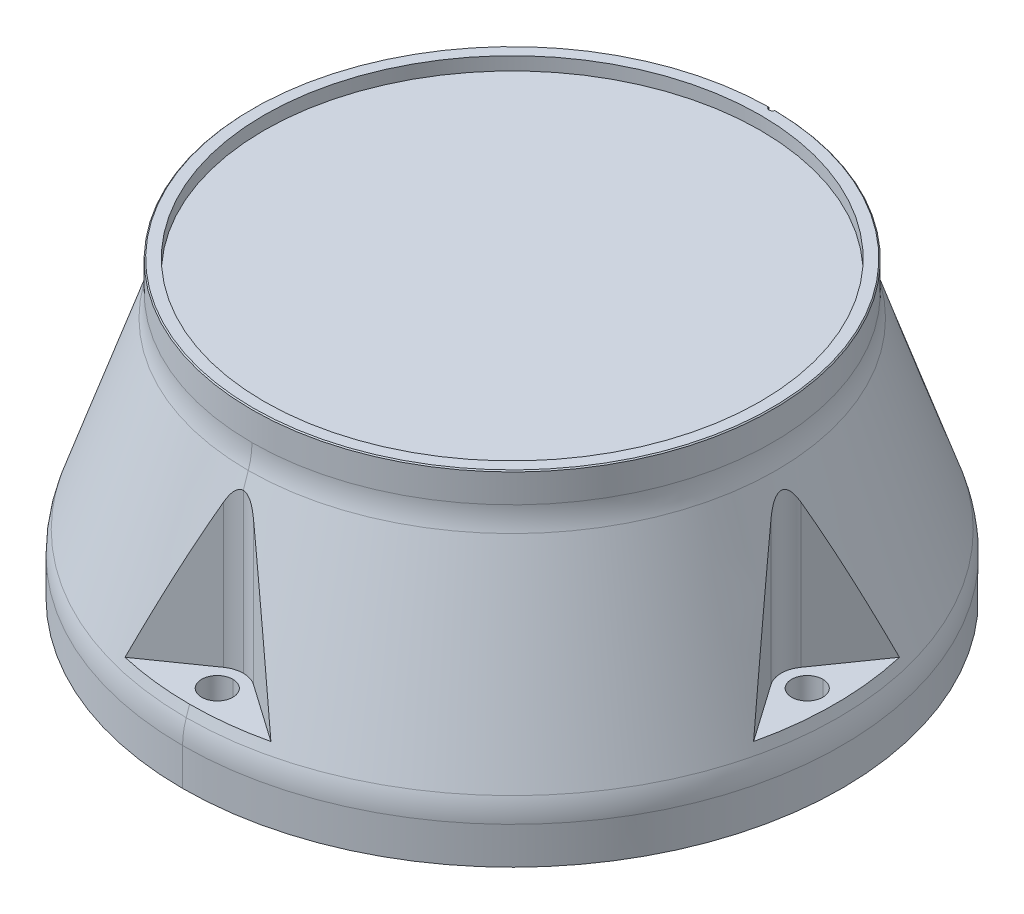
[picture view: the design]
ISO-10303-21;
HEADER;
FILE_DESCRIPTION(('STEP AP214'),'2;1');
FILE_NAME('part.step','',(''),(''),'','','');
FILE_SCHEMA(('AUTOMOTIVE_DESIGN { 1 0 10303 214 1 1 1 1 }'));
ENDSEC;
DATA;
#1=APPLICATION_CONTEXT('core data for automotive mechanical design processes');
#2=APPLICATION_PROTOCOL_DEFINITION('international standard','automotive_design',2000,#1);
#3=PRODUCT_CONTEXT('',#1,'mechanical');
#4=PRODUCT('Part','Part','',(#3));
#5=PRODUCT_RELATED_PRODUCT_CATEGORY('part','',(#4));
#6=PRODUCT_DEFINITION_FORMATION('','',#4);
#7=PRODUCT_DEFINITION_CONTEXT('part definition',#1,'design');
#8=PRODUCT_DEFINITION('design','',#6,#7);
#9=PRODUCT_DEFINITION_SHAPE('','',#8);
#10=(LENGTH_UNIT() NAMED_UNIT(*) SI_UNIT(.MILLI.,.METRE.));
#11=(NAMED_UNIT(*) PLANE_ANGLE_UNIT() SI_UNIT($,.RADIAN.));
#12=(NAMED_UNIT(*) SI_UNIT($,.STERADIAN.) SOLID_ANGLE_UNIT());
#13=UNCERTAINTY_MEASURE_WITH_UNIT(LENGTH_MEASURE(1.E-05),#10,'distance_accuracy_value','');
#14=(GEOMETRIC_REPRESENTATION_CONTEXT(3) GLOBAL_UNCERTAINTY_ASSIGNED_CONTEXT((#13)) GLOBAL_UNIT_ASSIGNED_CONTEXT((#10,
#11,#12)) REPRESENTATION_CONTEXT('',''));
#15=CARTESIAN_POINT('',(0.,0.,0.));
#16=DIRECTION('',(0.,0.,1.));
#17=DIRECTION('',(1.,0.,0.));
#18=AXIS2_PLACEMENT_3D('',#15,#16,#17);
#19=CARTESIAN_POINT('',(0.,82.,-75.));
#20=DIRECTION('',(0.,1.,0.));
#21=DIRECTION('',(0.,0.,1.));
#22=AXIS2_PLACEMENT_3D('',#19,#20,#21);
#23=CYLINDRICAL_SURFACE('',#22,1.);
#24=CARTESIAN_POINT('',(0.,84.8,-75.));
#25=DIRECTION('',(0.,1.,0.));
#26=DIRECTION('',(0.,0.,1.));
#27=AXIS2_PLACEMENT_3D('',#24,#25,#26);
#28=CIRCLE('',#27,1.);
#29=CARTESIAN_POINT('',(0.952397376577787,84.8000000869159,-74.6939519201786));
#30=VERTEX_POINT('',#29);
#31=CARTESIAN_POINT('',(0.,84.8,-74.));
#32=VERTEX_POINT('',#31);
#33=EDGE_CURVE('E2148',#30,#32,#28,.F.);
#34=ORIENTED_EDGE('',*,*,#33,.F.);
#35=CARTESIAN_POINT('',(0.952044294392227,84.7999875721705,-74.6940397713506));
#36=CARTESIAN_POINT('',(0.956875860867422,84.7849145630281,-74.7090742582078));
#37=CARTESIAN_POINT('',(0.961331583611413,84.769776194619,-74.7241610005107));
#38=CARTESIAN_POINT('',(0.967342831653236,84.7474166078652,-74.7464208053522));
#39=CARTESIAN_POINT('',(0.969186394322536,84.7402403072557,-74.753561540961));
#40=CARTESIAN_POINT('',(0.973275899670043,84.7235551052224,-74.7701550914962));
#41=CARTESIAN_POINT('',(0.97546092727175,84.7140372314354,-74.7796139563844));
#42=CARTESIAN_POINT('',(0.979838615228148,84.6936336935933,-74.7999035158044));
#43=CARTESIAN_POINT('',(0.981988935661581,84.6827443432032,-74.81073963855));
#44=CARTESIAN_POINT('',(0.986169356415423,84.6595957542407,-74.8337961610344));
#45=CARTESIAN_POINT('',(0.988151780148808,84.6473334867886,-74.8460221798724));
#46=CARTESIAN_POINT('',(0.991851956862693,84.6214387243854,-74.8718660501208));
#47=CARTESIAN_POINT('',(0.993516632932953,84.6078038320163,-74.8854891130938));
#48=CARTESIAN_POINT('',(0.996419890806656,84.579163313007,-74.9141250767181));
#49=CARTESIAN_POINT('',(0.997599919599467,84.5641557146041,-74.9291419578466));
#50=CARTESIAN_POINT('',(0.999356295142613,84.532769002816,-74.9605506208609));
#51=CARTESIAN_POINT('',(0.999868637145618,84.5163882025,-74.9769443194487));
#52=CARTESIAN_POINT('',(0.999977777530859,84.5000000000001,-74.9933333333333));
#53=B_SPLINE_CURVE_WITH_KNOTS('',3,(#35,#36,#37,#38,#39,#40,#41,#42,#43,#44,#45,#46,#47,#48,#49,
#50,#51,#52),.UNSPECIFIED.,.F.,.F.,(4,2,2,2,2,2,2,2,4),(0.,0.065484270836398,0.0963536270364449,
0.137136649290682,0.183668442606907,0.235949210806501,0.293979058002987,0.357758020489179,
0.427286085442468),.UNSPECIFIED.);
#54=CARTESIAN_POINT('',(0.999977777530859,84.5,-74.9933333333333));
#55=VERTEX_POINT('',#54);
#56=EDGE_CURVE('E766',#30,#55,#53,.T.);
#57=ORIENTED_EDGE('',*,*,#56,.T.);
#58=DIRECTION('',(0.,-1.,0.));
#59=VECTOR('',#58,1.);
#60=CARTESIAN_POINT('',(0.999977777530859,83.5,-74.9933333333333));
#61=LINE('',#60,#59);
#62=CARTESIAN_POINT('',(0.999977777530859,82.,-74.9933333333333));
#63=VERTEX_POINT('',#62);
#64=EDGE_CURVE('E688',#55,#63,#61,.T.);
#65=ORIENTED_EDGE('',*,*,#64,.T.);
#66=CARTESIAN_POINT('',(0.,82.,-75.));
#67=DIRECTION('',(0.,1.,0.));
#68=DIRECTION('',(0.,0.,1.));
#69=AXIS2_PLACEMENT_3D('',#66,#67,#68);
#70=CIRCLE('',#69,1.);
#71=CARTESIAN_POINT('',(0.,82.,-74.));
#72=VERTEX_POINT('',#71);
#73=EDGE_CURVE('E569',#72,#63,#70,.T.);
#74=ORIENTED_EDGE('',*,*,#73,.F.);
#75=DIRECTION('',(0.,1.,0.));
#76=VECTOR('',#75,1.);
#77=CARTESIAN_POINT('',(0.,82.,-74.));
#78=LINE('',#77,#76);
#79=EDGE_CURVE('E743',#72,#32,#78,.T.);
#80=ORIENTED_EDGE('',*,*,#79,.T.);
#81=EDGE_LOOP('',(#34,#57,#65,#74,#80));
#82=FACE_BOUND('',#81,.T.);
#83=ADVANCED_FACE('F15',(#82),#23,.F.);
#84=CARTESIAN_POINT('',(0.,100.390423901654,0.));
#85=DIRECTION('',(0.,1.,0.));
#86=DIRECTION('',(0.,0.,1.));
#87=AXIS2_PLACEMENT_3D('',#84,#85,#86);
#88=CYLINDRICAL_SURFACE('',#87,71.5);
#89=DIRECTION('',(0.,1.,0.));
#90=VECTOR('',#89,1.);
#91=CARTESIAN_POINT('',(0.,100.390423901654,71.5));
#92=LINE('',#91,#90);
#93=CARTESIAN_POINT('',(0.,81.,71.5));
#94=VERTEX_POINT('',#93);
#95=CARTESIAN_POINT('',(0.,81.5,71.5));
#96=VERTEX_POINT('',#95);
#97=EDGE_CURVE('E576',#94,#96,#92,.T.);
#98=ORIENTED_EDGE('',*,*,#97,.T.);
#99=ORIENTED_EDGE('',*,*,#97,.F.);
#100=CARTESIAN_POINT('',(0.,81.,0.));
#101=DIRECTION('',(0.,1.,0.));
#102=DIRECTION('',(0.,0.,1.));
#103=AXIS2_PLACEMENT_3D('',#100,#101,#102);
#104=CIRCLE('',#103,71.5);
#105=CARTESIAN_POINT('',(0.,81.,-71.5));
#106=VERTEX_POINT('',#105);
#107=EDGE_CURVE('E563',#106,#94,#104,.T.);
#108=ORIENTED_EDGE('',*,*,#107,.F.);
#109=DIRECTION('',(0.,1.,0.));
#110=VECTOR('',#109,1.);
#111=CARTESIAN_POINT('',(0.,100.390423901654,-71.5));
#112=LINE('',#111,#110);
#113=CARTESIAN_POINT('',(0.,84.8,-71.5));
#114=VERTEX_POINT('',#113);
#115=EDGE_CURVE('E689',#106,#114,#112,.T.);
#116=ORIENTED_EDGE('',*,*,#115,.T.);
#117=CARTESIAN_POINT('',(0.,84.8,0.));
#118=DIRECTION('',(0.,1.,0.));
#119=DIRECTION('',(0.,0.,1.));
#120=AXIS2_PLACEMENT_3D('',#117,#118,#119);
#121=CIRCLE('',#120,71.5);
#122=CARTESIAN_POINT('',(0.,84.8,71.5));
#123=VERTEX_POINT('',#122);
#124=EDGE_CURVE('E37',#123,#114,#121,.F.);
#125=ORIENTED_EDGE('',*,*,#124,.F.);
#126=DIRECTION('',(0.,1.,0.));
#127=VECTOR('',#126,1.);
#128=CARTESIAN_POINT('',(0.,100.390423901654,71.5));
#129=LINE('',#128,#127);
#130=CARTESIAN_POINT('',(-8.28313419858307E-13,84.5000000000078,71.5));
#131=VERTEX_POINT('',#130);
#132=EDGE_CURVE('E1265',#131,#123,#129,.T.);
#133=ORIENTED_EDGE('',*,*,#132,.F.);
#134=ORIENTED_EDGE('',*,*,#132,.T.);
#135=CARTESIAN_POINT('',(0.,84.8,0.));
#136=DIRECTION('',(0.,1.,0.));
#137=DIRECTION('',(0.,0.,1.));
#138=AXIS2_PLACEMENT_3D('',#135,#136,#137);
#139=CIRCLE('',#138,71.5);
#140=EDGE_CURVE('E2149',#114,#123,#139,.F.);
#141=ORIENTED_EDGE('',*,*,#140,.F.);
#142=ORIENTED_EDGE('',*,*,#115,.F.);
#143=CARTESIAN_POINT('',(0.,81.,0.));
#144=DIRECTION('',(0.,1.,0.));
#145=DIRECTION('',(0.,0.,1.));
#146=AXIS2_PLACEMENT_3D('',#143,#144,#145);
#147=CIRCLE('',#146,71.5);
#148=EDGE_CURVE('E551',#94,#106,#147,.T.);
#149=ORIENTED_EDGE('',*,*,#148,.F.);
#150=EDGE_LOOP('',(#98,#99,#108,#116,#125,#133,#134,#141,#142,#149));
#151=FACE_BOUND('',#150,.T.);
#152=ADVANCED_FACE('F1210',(#151),#88,.F.);
#153=CARTESIAN_POINT('',(0.,82.,-75.));
#154=DIRECTION('',(0.,1.,0.));
#155=DIRECTION('',(0.,0.,1.));
#156=AXIS2_PLACEMENT_3D('',#153,#154,#155);
#157=CYLINDRICAL_SURFACE('',#156,1.);
#158=CARTESIAN_POINT('',(0.,84.8,-75.));
#159=DIRECTION('',(0.,1.,0.));
#160=DIRECTION('',(0.,0.,1.));
#161=AXIS2_PLACEMENT_3D('',#158,#159,#160);
#162=CIRCLE('',#161,1.);
#163=CARTESIAN_POINT('',(-0.952291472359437,84.8000001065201,-74.693618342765));
#164=VERTEX_POINT('',#163);
#165=EDGE_CURVE('E537',#32,#164,#162,.F.);
#166=ORIENTED_EDGE('',*,*,#165,.F.);
#167=ORIENTED_EDGE('',*,*,#79,.F.);
#168=CARTESIAN_POINT('',(0.,82.,-75.));
#169=DIRECTION('',(0.,1.,0.));
#170=DIRECTION('',(0.,0.,1.));
#171=AXIS2_PLACEMENT_3D('',#168,#169,#170);
#172=CIRCLE('',#171,1.);
#173=CARTESIAN_POINT('',(-0.999977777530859,82.,-74.9933333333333));
#174=VERTEX_POINT('',#173);
#175=EDGE_CURVE('E571',#174,#72,#172,.T.);
#176=ORIENTED_EDGE('',*,*,#175,.F.);
#177=DIRECTION('',(0.,1.,0.));
#178=VECTOR('',#177,1.);
#179=CARTESIAN_POINT('',(-0.999977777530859,83.5,-74.9933333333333));
#180=LINE('',#179,#178);
#181=CARTESIAN_POINT('',(-0.999977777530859,84.5,-74.9933333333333));
#182=VERTEX_POINT('',#181);
#183=EDGE_CURVE('E956',#174,#182,#180,.T.);
#184=ORIENTED_EDGE('',*,*,#183,.T.);
#185=CARTESIAN_POINT('',(-0.999977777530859,84.5000000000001,-74.9933333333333));
#186=CARTESIAN_POINT('',(-0.999882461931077,84.514311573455,-74.979021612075));
#187=CARTESIAN_POINT('',(-0.999479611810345,84.5286090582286,-74.9646977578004));
#188=CARTESIAN_POINT('',(-0.998080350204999,84.5566851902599,-74.9365376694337));
#189=CARTESIAN_POINT('',(-0.997104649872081,84.5704649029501,-74.9227014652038));
#190=CARTESIAN_POINT('',(-0.994619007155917,84.5975055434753,-74.8955373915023));
#191=CARTESIAN_POINT('',(-0.993129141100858,84.6107676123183,-74.8822088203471));
#192=CARTESIAN_POINT('',(-0.989673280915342,84.6367728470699,-74.8560760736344));
#193=CARTESIAN_POINT('',(-0.987726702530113,84.649517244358,-74.8432705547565));
#194=CARTESIAN_POINT('',(-0.983413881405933,84.6744870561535,-74.8181957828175));
#195=CARTESIAN_POINT('',(-0.981066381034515,84.6867138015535,-74.8059246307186));
#196=CARTESIAN_POINT('',(-0.976006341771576,84.7106481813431,-74.7819266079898));
#197=CARTESIAN_POINT('',(-0.973311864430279,84.7223572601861,-74.7701973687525));
#198=CARTESIAN_POINT('',(-0.967610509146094,84.7452562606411,-74.7472877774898));
#199=CARTESIAN_POINT('',(-0.96462100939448,84.7564477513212,-74.7361046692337));
#200=CARTESIAN_POINT('',(-0.958379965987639,84.7783111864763,-74.7142886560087));
#201=CARTESIAN_POINT('',(-0.955145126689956,84.7889848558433,-74.7036526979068));
#202=CARTESIAN_POINT('',(-0.951727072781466,84.7996373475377,-74.6930544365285));
#203=B_SPLINE_CURVE_WITH_KNOTS('',3,(#185,#186,#187,#188,#189,#190,#191,#192,#193,#194,#195,
#196,#197,#198,#199,#200,#201,#202),.UNSPECIFIED.,.F.,.F.,(4,2,2,2,2,2,2,2,4),(0.,
0.0607175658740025,0.119364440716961,0.175940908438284,0.230447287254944,0.282883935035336,
0.333251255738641,0.381549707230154,0.427779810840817),.UNSPECIFIED.);
#204=EDGE_CURVE('E1529',#182,#164,#203,.T.);
#205=ORIENTED_EDGE('',*,*,#204,.T.);
#206=EDGE_LOOP('',(#166,#167,#176,#184,#205));
#207=FACE_BOUND('',#206,.T.);
#208=ADVANCED_FACE('F1055',(#207),#157,.F.);
#209=CARTESIAN_POINT('',(0.,85.,0.));
#210=DIRECTION('',(0.,-1.,0.));
#211=DIRECTION('',(0.,0.,-1.));
#212=AXIS2_PLACEMENT_3D('',#209,#210,#211);
#213=CONICAL_SURFACE('',#212,74.5,0.785398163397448);
#214=ORIENTED_EDGE('',*,*,#56,.F.);
#215=CARTESIAN_POINT('',(0.,84.8,0.));
#216=DIRECTION('',(0.,1.,0.));
#217=DIRECTION('',(0.,0.,1.));
#218=AXIS2_PLACEMENT_3D('',#215,#216,#217);
#219=CIRCLE('',#218,74.7);
#220=EDGE_CURVE('E10',#30,#164,#219,.F.);
#221=ORIENTED_EDGE('',*,*,#220,.T.);
#222=ORIENTED_EDGE('',*,*,#204,.F.);
#223=CARTESIAN_POINT('',(0.,84.5,0.));
#224=DIRECTION('',(0.,-1.,0.));
#225=DIRECTION('',(0.,0.,1.));
#226=AXIS2_PLACEMENT_3D('',#223,#224,#225);
#227=CIRCLE('',#226,75.);
#228=EDGE_CURVE('E731',#55,#182,#227,.T.);
#229=ORIENTED_EDGE('',*,*,#228,.F.);
#230=EDGE_LOOP('',(#214,#221,#222,#229));
#231=FACE_BOUND('',#230,.T.);
#232=ADVANCED_FACE('F1251',(#231),#213,.T.);
#233=CARTESIAN_POINT('',(63.6396103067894,2.5,-42.4264068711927));
#234=DIRECTION('',(0.,-1.,0.));
#235=DIRECTION('',(0.,0.,-1.));
#236=AXIS2_PLACEMENT_3D('',#233,#234,#235);
#237=CYLINDRICAL_SURFACE('',#236,1.24999999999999);
#238=CARTESIAN_POINT('',(63.6396103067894,10.,-42.4264068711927));
#239=DIRECTION('',(0.,-1.,0.));
#240=DIRECTION('',(0.,0.,-1.));
#241=AXIS2_PLACEMENT_3D('',#238,#239,#240);
#242=CIRCLE('',#241,1.24999999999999);
#243=CARTESIAN_POINT('',(63.6396103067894,10.,-41.1764068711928));
#244=VERTEX_POINT('',#243);
#245=CARTESIAN_POINT('',(63.6396103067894,10.,-43.6764068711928));
#246=VERTEX_POINT('',#245);
#247=EDGE_CURVE('E614',#244,#246,#242,.T.);
#248=ORIENTED_EDGE('',*,*,#247,.F.);
#249=DIRECTION('',(0.,-1.,0.));
#250=VECTOR('',#249,1.);
#251=CARTESIAN_POINT('',(63.6396103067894,2.5,-41.1764068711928));
#252=LINE('',#251,#250);
#253=CARTESIAN_POINT('',(63.6396103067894,2.5,-41.1764068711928));
#254=VERTEX_POINT('',#253);
#255=EDGE_CURVE('E24',#244,#254,#252,.T.);
#256=ORIENTED_EDGE('',*,*,#255,.T.);
#257=CARTESIAN_POINT('',(63.6396103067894,2.5,-42.4264068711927));
#258=DIRECTION('',(0.,-1.,0.));
#259=DIRECTION('',(0.,0.,-1.));
#260=AXIS2_PLACEMENT_3D('',#257,#258,#259);
#261=CIRCLE('',#260,1.24999999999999);
#262=CARTESIAN_POINT('',(63.6396103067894,2.5,-43.6764068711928));
#263=VERTEX_POINT('',#262);
#264=EDGE_CURVE('E613',#254,#263,#261,.T.);
#265=ORIENTED_EDGE('',*,*,#264,.T.);
#266=DIRECTION('',(0.,-1.,0.));
#267=VECTOR('',#266,1.);
#268=CARTESIAN_POINT('',(63.6396103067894,2.5,-43.6764068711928));
#269=LINE('',#268,#267);
#270=EDGE_CURVE('E853',#246,#263,#269,.T.);
#271=ORIENTED_EDGE('',*,*,#270,.F.);
#272=EDGE_LOOP('',(#248,#256,#265,#271));
#273=FACE_BOUND('',#272,.T.);
#274=ADVANCED_FACE('F1550',(#273),#237,.F.);
#275=CARTESIAN_POINT('',(63.6396103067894,10.,-42.4264068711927));
#276=DIRECTION('',(0.,-1.,0.));
#277=DIRECTION('',(0.,0.,-1.));
#278=AXIS2_PLACEMENT_3D('',#275,#276,#277);
#279=CONICAL_SURFACE('',#278,1.24999999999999,1.02974425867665);
#280=DIRECTION('',(0.,-0.515038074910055,-0.857167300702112));
#281=VECTOR('',#280,1.);
#282=CARTESIAN_POINT('',(63.6396103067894,10.,-43.6764068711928));
#283=LINE('',#282,#281);
#284=CARTESIAN_POINT('',(63.6396103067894,10.7510757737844,-42.4264068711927));
#285=VERTEX_POINT('',#284);
#286=EDGE_CURVE('E801',#285,#246,#283,.T.);
#287=ORIENTED_EDGE('',*,*,#286,.F.);
#288=DIRECTION('',(0.,-0.515038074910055,0.857167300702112));
#289=VECTOR('',#288,1.);
#290=CARTESIAN_POINT('',(63.6396103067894,10.,-41.1764068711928));
#291=LINE('',#290,#289);
#292=EDGE_CURVE('E609',#285,#244,#291,.T.);
#293=ORIENTED_EDGE('',*,*,#292,.T.);
#294=ORIENTED_EDGE('',*,*,#247,.T.);
#295=EDGE_LOOP('',(#287,#293,#294));
#296=FACE_BOUND('',#295,.T.);
#297=ADVANCED_FACE('F1685',(#296),#279,.F.);
#298=CARTESIAN_POINT('',(42.4264068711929,2.5,-63.6396103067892));
#299=DIRECTION('',(0.,-1.,0.));
#300=DIRECTION('',(0.,0.,-1.));
#301=AXIS2_PLACEMENT_3D('',#298,#299,#300);
#302=CYLINDRICAL_SURFACE('',#301,1.24999999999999);
#303=CARTESIAN_POINT('',(42.4264068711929,10.,-63.6396103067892));
#304=DIRECTION('',(0.,-1.,0.));
#305=DIRECTION('',(0.,0.,-1.));
#306=AXIS2_PLACEMENT_3D('',#303,#304,#305);
#307=CIRCLE('',#306,1.24999999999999);
#308=CARTESIAN_POINT('',(42.4264068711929,10.,-62.3896103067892));
#309=VERTEX_POINT('',#308);
#310=CARTESIAN_POINT('',(42.4264068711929,10.,-64.8896103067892));
#311=VERTEX_POINT('',#310);
#312=EDGE_CURVE('E714',#309,#311,#307,.T.);
#313=ORIENTED_EDGE('',*,*,#312,.F.);
#314=DIRECTION('',(0.,-1.,0.));
#315=VECTOR('',#314,1.);
#316=CARTESIAN_POINT('',(42.4264068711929,2.5,-62.3896103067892));
#317=LINE('',#316,#315);
#318=CARTESIAN_POINT('',(42.4264068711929,2.5,-62.3896103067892));
#319=VERTEX_POINT('',#318);
#320=EDGE_CURVE('E625',#309,#319,#317,.T.);
#321=ORIENTED_EDGE('',*,*,#320,.T.);
#322=CARTESIAN_POINT('',(42.4264068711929,2.5,-63.6396103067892));
#323=DIRECTION('',(0.,-1.,0.));
#324=DIRECTION('',(0.,0.,-1.));
#325=AXIS2_PLACEMENT_3D('',#322,#323,#324);
#326=CIRCLE('',#325,1.24999999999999);
#327=CARTESIAN_POINT('',(42.4264068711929,2.5,-64.8896103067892));
#328=VERTEX_POINT('',#327);
#329=EDGE_CURVE('E621',#319,#328,#326,.T.);
#330=ORIENTED_EDGE('',*,*,#329,.T.);
#331=DIRECTION('',(0.,-1.,0.));
#332=VECTOR('',#331,1.);
#333=CARTESIAN_POINT('',(42.4264068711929,2.5,-64.8896103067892));
#334=LINE('',#333,#332);
#335=EDGE_CURVE('E747',#311,#328,#334,.T.);
#336=ORIENTED_EDGE('',*,*,#335,.F.);
#337=EDGE_LOOP('',(#313,#321,#330,#336));
#338=FACE_BOUND('',#337,.T.);
#339=ADVANCED_FACE('F1681',(#338),#302,.F.);
#340=CARTESIAN_POINT('',(42.4264068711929,10.,-63.6396103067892));
#341=DIRECTION('',(0.,-1.,0.));
#342=DIRECTION('',(0.,0.,-1.));
#343=AXIS2_PLACEMENT_3D('',#340,#341,#342);
#344=CONICAL_SURFACE('',#343,1.24999999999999,1.02974425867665);
#345=DIRECTION('',(0.,-0.515038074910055,-0.857167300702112));
#346=VECTOR('',#345,1.);
#347=CARTESIAN_POINT('',(42.4264068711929,10.,-64.8896103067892));
#348=LINE('',#347,#346);
#349=CARTESIAN_POINT('',(42.4264068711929,10.7510757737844,-63.6396103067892));
#350=VERTEX_POINT('',#349);
#351=EDGE_CURVE('E797',#350,#311,#348,.T.);
#352=ORIENTED_EDGE('',*,*,#351,.F.);
#353=DIRECTION('',(0.,-0.515038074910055,0.857167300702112));
#354=VECTOR('',#353,1.);
#355=CARTESIAN_POINT('',(42.4264068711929,10.,-62.3896103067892));
#356=LINE('',#355,#354);
#357=EDGE_CURVE('E626',#350,#309,#356,.T.);
#358=ORIENTED_EDGE('',*,*,#357,.T.);
#359=ORIENTED_EDGE('',*,*,#312,.T.);
#360=EDGE_LOOP('',(#352,#358,#359));
#361=FACE_BOUND('',#360,.T.);
#362=ADVANCED_FACE('F1684',(#361),#344,.F.);
#363=CARTESIAN_POINT('',(70.0035713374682,10.,41.7193000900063));
#364=DIRECTION('',(0.,-1.,0.));
#365=DIRECTION('',(0.,0.,-1.));
#366=AXIS2_PLACEMENT_3D('',#363,#364,#365);
#367=CYLINDRICAL_SURFACE('',#366,4.);
#368=CARTESIAN_POINT('',(70.0035713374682,10.,41.7193000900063));
#369=DIRECTION('',(0.,-1.,0.));
#370=DIRECTION('',(0.,0.,-1.));
#371=AXIS2_PLACEMENT_3D('',#368,#369,#370);
#372=CIRCLE('',#371,4.);
#373=CARTESIAN_POINT('',(70.0035713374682,10.,37.7193000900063));
#374=VERTEX_POINT('',#373);
#375=CARTESIAN_POINT('',(72.8319984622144,10.,38.8908729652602));
#376=VERTEX_POINT('',#375);
#377=EDGE_CURVE('E671',#374,#376,#372,.T.);
#378=ORIENTED_EDGE('',*,*,#377,.F.);
#379=DIRECTION('',(0.,-1.,0.));
#380=VECTOR('',#379,1.);
#381=CARTESIAN_POINT('',(70.0035713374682,10.,37.7193000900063));
#382=LINE('',#381,#380);
#383=CARTESIAN_POINT('',(70.0035713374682,0.,37.7193000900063));
#384=VERTEX_POINT('',#383);
#385=EDGE_CURVE('E718',#374,#384,#382,.T.);
#386=ORIENTED_EDGE('',*,*,#385,.T.);
#387=CARTESIAN_POINT('',(70.0035713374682,0.,41.7193000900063));
#388=DIRECTION('',(0.,-1.,0.));
#389=DIRECTION('',(0.,0.,-1.));
#390=AXIS2_PLACEMENT_3D('',#387,#388,#389);
#391=CIRCLE('',#390,4.);
#392=CARTESIAN_POINT('',(72.8319984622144,0.,38.8908729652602));
#393=VERTEX_POINT('',#392);
#394=EDGE_CURVE('E643',#384,#393,#391,.T.);
#395=ORIENTED_EDGE('',*,*,#394,.T.);
#396=DIRECTION('',(0.,-1.,0.));
#397=VECTOR('',#396,1.);
#398=CARTESIAN_POINT('',(72.8319984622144,10.,38.8908729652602));
#399=LINE('',#398,#397);
#400=EDGE_CURVE('E594',#376,#393,#399,.T.);
#401=ORIENTED_EDGE('',*,*,#400,.F.);
#402=EDGE_LOOP('',(#378,#386,#395,#401));
#403=FACE_BOUND('',#402,.T.);
#404=ADVANCED_FACE('F1192',(#403),#367,.F.);
#405=CARTESIAN_POINT('',(-42.4264068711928,10.,-70.7106781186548));
#406=DIRECTION('',(0.,-1.,0.));
#407=DIRECTION('',(0.,0.,-1.));
#408=AXIS2_PLACEMENT_3D('',#405,#406,#407);
#409=CYLINDRICAL_SURFACE('',#408,4.);
#410=CARTESIAN_POINT('',(-42.4264068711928,10.,-70.7106781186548));
#411=DIRECTION('',(0.,-1.,0.));
#412=DIRECTION('',(0.,0.,-1.));
#413=AXIS2_PLACEMENT_3D('',#410,#411,#412);
#414=CIRCLE('',#413,4.);
#415=CARTESIAN_POINT('',(-42.4264068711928,10.,-66.7106781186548));
#416=VERTEX_POINT('',#415);
#417=CARTESIAN_POINT('',(-42.4264068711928,10.,-74.7106781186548));
#418=VERTEX_POINT('',#417);
#419=EDGE_CURVE('E592',#416,#418,#414,.T.);
#420=ORIENTED_EDGE('',*,*,#419,.F.);
#421=DIRECTION('',(0.,-1.,0.));
#422=VECTOR('',#421,1.);
#423=CARTESIAN_POINT('',(-42.4264068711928,10.,-66.7106781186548));
#424=LINE('',#423,#422);
#425=CARTESIAN_POINT('',(-42.4264068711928,0.,-66.7106781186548));
#426=VERTEX_POINT('',#425);
#427=EDGE_CURVE('E639',#416,#426,#424,.T.);
#428=ORIENTED_EDGE('',*,*,#427,.T.);
#429=CARTESIAN_POINT('',(-42.4264068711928,0.,-70.7106781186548));
#430=DIRECTION('',(0.,-1.,0.));
#431=DIRECTION('',(0.,0.,-1.));
#432=AXIS2_PLACEMENT_3D('',#429,#430,#431);
#433=CIRCLE('',#432,4.);
#434=CARTESIAN_POINT('',(-42.4264068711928,0.,-74.7106781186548));
#435=VERTEX_POINT('',#434);
#436=EDGE_CURVE('E644',#426,#435,#433,.T.);
#437=ORIENTED_EDGE('',*,*,#436,.T.);
#438=DIRECTION('',(0.,-1.,0.));
#439=VECTOR('',#438,1.);
#440=CARTESIAN_POINT('',(-42.4264068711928,10.,-74.7106781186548));
#441=LINE('',#440,#439);
#442=EDGE_CURVE('E699',#418,#435,#441,.T.);
#443=ORIENTED_EDGE('',*,*,#442,.F.);
#444=EDGE_LOOP('',(#420,#428,#437,#443));
#445=FACE_BOUND('',#444,.T.);
#446=ADVANCED_FACE('F1015',(#445),#409,.F.);
#447=CARTESIAN_POINT('',(0.,10.7023274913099,0.));
#448=DIRECTION('',(0.,-1.,0.));
#449=DIRECTION('',(0.,0.,-1.));
#450=AXIS2_PLACEMENT_3D('',#447,#448,#449);
#451=TOROIDAL_SURFACE('',#450,75.,20.);
#452=CARTESIAN_POINT('',(0.,17.1231131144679,0.));
#453=DIRECTION('',(0.,1.,0.));
#454=DIRECTION('',(0.,0.,1.));
#455=AXIS2_PLACEMENT_3D('',#452,#453,#454);
#456=CIRCLE('',#455,93.941317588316);
#457=CARTESIAN_POINT('',(0.,17.1231131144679,93.941317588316));
#458=VERTEX_POINT('',#457);
#459=CARTESIAN_POINT('',(0.,17.1231131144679,-93.941317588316));
#460=VERTEX_POINT('',#459);
#461=EDGE_CURVE('E872',#458,#460,#456,.T.);
#462=ORIENTED_EDGE('',*,*,#461,.F.);
#463=CARTESIAN_POINT('',(0.,10.7023274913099,75.));
#464=DIRECTION('',(1.,0.,0.));
#465=DIRECTION('',(0.,0.,-1.));
#466=AXIS2_PLACEMENT_3D('',#463,#464,#465);
#467=CIRCLE('',#466,20.);
#468=CARTESIAN_POINT('',(0.,10.7023274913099,95.));
#469=VERTEX_POINT('',#468);
#470=EDGE_CURVE('E787',#458,#469,#467,.T.);
#471=ORIENTED_EDGE('',*,*,#470,.T.);
#472=CARTESIAN_POINT('',(0.,10.7023274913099,0.));
#473=DIRECTION('',(0.,-1.,0.));
#474=DIRECTION('',(0.,0.,-1.));
#475=AXIS2_PLACEMENT_3D('',#472,#473,#474);
#476=CIRCLE('',#475,95.);
#477=CARTESIAN_POINT('',(70.4307481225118,10.7023274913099,-63.7535075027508));
#478=VERTEX_POINT('',#477);
#479=EDGE_CURVE('E680',#478,#469,#476,.T.);
#480=ORIENTED_EDGE('',*,*,#479,.F.);
#481=CARTESIAN_POINT('',(70.4307481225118,10.7023274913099,-63.7535075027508));
#482=CARTESIAN_POINT('',(70.3838464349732,10.7913709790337,-63.805323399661));
#483=CARTESIAN_POINT('',(70.3347730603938,10.878460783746,-63.8585335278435));
#484=CARTESIAN_POINT('',(70.2327006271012,11.0481313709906,-63.9674861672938));
#485=CARTESIAN_POINT('',(70.1797157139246,11.1307266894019,-64.0232192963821));
#486=CARTESIAN_POINT('',(70.0699280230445,11.2914003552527,-64.1373025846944));
#487=CARTESIAN_POINT('',(70.0131264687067,11.3694801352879,-64.1956519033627));
#488=CARTESIAN_POINT('',(69.8958172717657,11.5211329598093,-64.3150335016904));
#489=CARTESIAN_POINT('',(69.8352995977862,11.5946926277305,-64.3760729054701));
#490=CARTESIAN_POINT('',(69.710759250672,11.7371972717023,-64.5007937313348));
#491=CARTESIAN_POINT('',(69.6467228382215,11.8061214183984,-64.5644852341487));
#492=CARTESIAN_POINT('',(69.5158720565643,11.9384832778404,-64.69396363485));
#493=CARTESIAN_POINT('',(69.4490683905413,12.001939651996,-64.7597422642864));
#494=CARTESIAN_POINT('',(69.3127888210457,12.1233849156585,-64.8934686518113));
#495=CARTESIAN_POINT('',(69.2433139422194,12.1813758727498,-64.9614155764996));
#496=CARTESIAN_POINT('',(69.1017846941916,12.2919135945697,-65.0995436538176));
#497=CARTESIAN_POINT('',(69.0297236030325,12.3444445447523,-65.1697305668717));
#498=CARTESIAN_POINT('',(68.8836485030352,12.4437126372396,-65.3118632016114));
#499=CARTESIAN_POINT('',(68.8096376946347,12.4904586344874,-65.3838060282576));
#500=CARTESIAN_POINT('',(68.6601075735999,12.5778619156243,-65.5291670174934));
#501=CARTESIAN_POINT('',(68.5845946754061,12.6185405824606,-65.6025789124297));
#502=CARTESIAN_POINT('',(68.4321322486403,12.6938363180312,-65.7509340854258));
#503=CARTESIAN_POINT('',(68.3551833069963,12.7284558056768,-65.8258767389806));
#504=CARTESIAN_POINT('',(68.199905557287,12.7916613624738,-65.9773396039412));
#505=CARTESIAN_POINT('',(68.1215734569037,12.8202300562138,-66.0538636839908));
#506=CARTESIAN_POINT('',(67.9635384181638,12.87137040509,-66.2085582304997));
#507=CARTESIAN_POINT('',(67.8838299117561,12.8939024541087,-66.2867361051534));
#508=CARTESIAN_POINT('',(67.7240984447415,12.9324967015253,-66.4437925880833));
#509=CARTESIAN_POINT('',(67.6440775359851,12.9485810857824,-66.5226678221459));
#510=CARTESIAN_POINT('',(67.4837502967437,12.9743011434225,-66.6811462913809));
#511=CARTESIAN_POINT('',(67.4034440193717,12.9839379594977,-66.7607493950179));
#512=CARTESIAN_POINT('',(67.2425532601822,12.9968049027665,-66.9206966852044));
#513=CARTESIAN_POINT('',(67.1619686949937,13.0000148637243,-67.0010424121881));
#514=CARTESIAN_POINT('',(67.0815085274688,13.,-67.0815085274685));
#515=B_SPLINE_CURVE_WITH_KNOTS('',3,(#481,#482,#483,#484,#485,#486,#487,#488,#489,#490,#491,
#492,#493,#494,#495,#496,#497,#498,#499,#500,#501,#502,#503,#504,#505,#506,#507,#508,#509,#510,
#511,#512,#513,#514),.UNSPECIFIED.,.F.,.F.,(4,2,2,2,2,2,2,2,2,2,2,2,2,2,2,2,4),(0.,
0.339544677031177,0.677916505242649,1.01618038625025,1.35540136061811,1.69605678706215,
2.035499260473,2.37481280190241,2.71508325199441,3.05482623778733,3.39334204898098,
3.73172241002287,4.0710616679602,4.4125756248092,4.75290416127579,5.09317236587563,
5.43450660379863),.UNSPECIFIED.);
#516=CARTESIAN_POINT('',(67.0815085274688,13.,-67.0815085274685));
#517=VERTEX_POINT('',#516);
#518=EDGE_CURVE('E857',#478,#517,#515,.T.);
#519=ORIENTED_EDGE('',*,*,#518,.T.);
#520=CARTESIAN_POINT('',(67.0815085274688,13.,-67.0815085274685));
#521=CARTESIAN_POINT('',(67.0015213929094,13.0000144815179,-67.1614898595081));
#522=CARTESIAN_POINT('',(66.9216532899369,12.9968418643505,-67.2415940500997));
#523=CARTESIAN_POINT('',(66.7626467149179,12.9841253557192,-67.4015332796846));
#524=CARTESIAN_POINT('',(66.6835067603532,12.9746009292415,-67.4813683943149));
#525=CARTESIAN_POINT('',(66.525940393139,12.9491812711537,-67.6407626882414));
#526=CARTESIAN_POINT('',(66.4475141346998,12.9332846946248,-67.7203218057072));
#527=CARTESIAN_POINT('',(66.2913420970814,12.8951417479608,-67.8791395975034));
#528=CARTESIAN_POINT('',(66.2135996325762,12.8728734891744,-67.9583962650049));
#529=CARTESIAN_POINT('',(66.0590998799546,12.822113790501,-68.1162166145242));
#530=CARTESIAN_POINT('',(65.9823450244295,12.7936092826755,-68.1947784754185));
#531=CARTESIAN_POINT('',(65.8304208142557,12.7304937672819,-68.3505192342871));
#532=CARTESIAN_POINT('',(65.7552476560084,12.6958998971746,-68.427701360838));
#533=CARTESIAN_POINT('',(65.6064311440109,12.6206174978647,-68.5806334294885));
#534=CARTESIAN_POINT('',(65.53278853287,12.5799260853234,-68.6563826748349));
#535=CARTESIAN_POINT('',(65.3869648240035,12.4924603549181,-68.8063886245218));
#536=CARTESIAN_POINT('',(65.3147901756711,12.445663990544,-68.8806387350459));
#537=CARTESIAN_POINT('',(65.1726204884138,12.3465519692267,-69.026755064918));
#538=CARTESIAN_POINT('',(65.1026173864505,12.2942610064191,-69.0986301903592));
#539=CARTESIAN_POINT('',(64.9648364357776,12.1842268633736,-69.2398129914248));
#540=CARTESIAN_POINT('',(64.8970530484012,12.1264989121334,-69.3091271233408));
#541=CARTESIAN_POINT('',(64.7636335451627,12.0056039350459,-69.4451114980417));
#542=CARTESIAN_POINT('',(64.6979984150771,11.9424344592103,-69.5117805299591));
#543=CARTESIAN_POINT('',(64.5687874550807,11.8106707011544,-69.6423891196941));
#544=CARTESIAN_POINT('',(64.5052199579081,11.742057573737,-69.7063179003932));
#545=CARTESIAN_POINT('',(64.3801787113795,11.5995679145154,-69.8312198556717));
#546=CARTESIAN_POINT('',(64.3187160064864,11.5256685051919,-69.8921779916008));
#547=CARTESIAN_POINT('',(64.1985187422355,11.3732738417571,-70.0103280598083));
#548=CARTESIAN_POINT('',(64.1397769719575,11.2947921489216,-70.0675301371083));
#549=CARTESIAN_POINT('',(64.0249377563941,11.1332530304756,-70.1780774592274));
#550=CARTESIAN_POINT('',(63.9688412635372,11.0501939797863,-70.231421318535));
#551=CARTESIAN_POINT('',(63.8591888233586,10.8795349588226,-70.3341686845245));
#552=CARTESIAN_POINT('',(63.805642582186,10.7919199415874,-70.3835575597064));
#553=CARTESIAN_POINT('',(63.7535075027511,10.7023274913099,-70.4307481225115));
#554=B_SPLINE_CURVE_WITH_KNOTS('',3,(#520,#521,#522,#523,#524,#525,#526,#527,#528,#529,#530,
#531,#532,#533,#534,#535,#536,#537,#538,#539,#540,#541,#542,#543,#544,#545,#546,#547,#548,#549,
#550,#551,#552,#553),.UNSPECIFIED.,.F.,.F.,(4,2,2,2,2,2,2,2,2,2,2,2,2,2,2,2,4),(0.,
0.339303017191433,0.677570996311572,1.01591040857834,1.35542636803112,1.69566070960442,
2.03495239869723,2.37440503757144,2.71511933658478,3.05436304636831,3.39268329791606,
3.73115667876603,4.07085773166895,4.41213004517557,4.75243906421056,5.0928696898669,
5.43450655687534),.UNSPECIFIED.);
#555=CARTESIAN_POINT('',(63.7535075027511,10.7023274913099,-70.4307481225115));
#556=VERTEX_POINT('',#555);
#557=EDGE_CURVE('E1037',#517,#556,#554,.T.);
#558=ORIENTED_EDGE('',*,*,#557,.T.);
#559=CARTESIAN_POINT('',(0.,10.7023274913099,0.));
#560=DIRECTION('',(0.,-1.,0.));
#561=DIRECTION('',(0.,0.,-1.));
#562=AXIS2_PLACEMENT_3D('',#559,#560,#561);
#563=CIRCLE('',#562,95.);
#564=CARTESIAN_POINT('',(0.,10.7023274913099,-95.));
#565=VERTEX_POINT('',#564);
#566=EDGE_CURVE('E771',#565,#556,#563,.T.);
#567=ORIENTED_EDGE('',*,*,#566,.F.);
#568=CARTESIAN_POINT('',(0.,10.7023274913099,-75.));
#569=DIRECTION('',(-1.,0.,0.));
#570=DIRECTION('',(0.,0.,1.));
#571=AXIS2_PLACEMENT_3D('',#568,#569,#570);
#572=CIRCLE('',#571,20.);
#573=EDGE_CURVE('E695',#460,#565,#572,.T.);
#574=ORIENTED_EDGE('',*,*,#573,.F.);
#575=EDGE_LOOP('',(#462,#471,#480,#519,#558,#567,#574));
#576=FACE_BOUND('',#575,.T.);
#577=ADVANCED_FACE('F1004',(#576),#451,.T.);
#578=CARTESIAN_POINT('',(8.90327741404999E-13,85.,85.));
#579=DIRECTION('',(0.,-1.,0.));
#580=DIRECTION('',(0.,0.,-1.));
#581=AXIS2_PLACEMENT_3D('',#578,#579,#580);
#582=CYLINDRICAL_SURFACE('',#581,7.5);
#583=CARTESIAN_POINT('',(4.30182327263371,61.2778492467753,78.8563596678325));
#584=CARTESIAN_POINT('',(4.24545980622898,61.4031296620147,78.8169004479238));
#585=CARTESIAN_POINT('',(4.18776122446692,61.5278813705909,78.7776484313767));
#586=CARTESIAN_POINT('',(4.07175334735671,61.7712053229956,78.7011525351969));
#587=CARTESIAN_POINT('',(4.01355870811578,61.8898266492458,78.6638906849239));
#588=CARTESIAN_POINT('',(3.88547793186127,62.1429432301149,78.584430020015));
#589=CARTESIAN_POINT('',(3.81512547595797,62.2772269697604,78.5423048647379));
#590=CARTESIAN_POINT('',(3.68727408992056,62.5120552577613,78.468684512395));
#591=CARTESIAN_POINT('',(3.63068428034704,62.6130478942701,78.4370378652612));
#592=CARTESIAN_POINT('',(3.50331818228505,62.8334320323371,78.3680320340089));
#593=CARTESIAN_POINT('',(3.43194830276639,62.952515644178,78.3307797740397));
#594=CARTESIAN_POINT('',(3.28836054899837,63.1825840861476,78.2588710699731));
#595=CARTESIAN_POINT('',(3.21634672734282,63.293683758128,78.2241757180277));
#596=CARTESIAN_POINT('',(3.07156106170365,63.5077716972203,78.1573723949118));
#597=CARTESIAN_POINT('',(2.99900173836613,63.6108897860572,78.1252212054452));
#598=CARTESIAN_POINT('',(2.8532076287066,63.8090025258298,78.0634912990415));
#599=CARTESIAN_POINT('',(2.78019369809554,63.9041439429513,78.033864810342));
#600=CARTESIAN_POINT('',(2.65789387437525,64.0560741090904,77.9865742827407));
#601=CARTESIAN_POINT('',(2.60997667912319,64.1138667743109,77.9685902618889));
#602=CARTESIAN_POINT('',(2.51384860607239,64.2261400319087,77.9336646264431));
#603=CARTESIAN_POINT('',(2.46569773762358,64.2806672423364,77.9167081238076));
#604=CARTESIAN_POINT('',(2.36912511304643,64.386405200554,77.8838379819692));
#605=CARTESIAN_POINT('',(2.32076378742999,64.4376660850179,77.867908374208));
#606=CARTESIAN_POINT('',(2.22379223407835,64.5368681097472,77.8370920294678));
#607=CARTESIAN_POINT('',(2.17524252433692,64.5848629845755,77.82218822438));
#608=CARTESIAN_POINT('',(2.07791667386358,64.6775292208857,77.7934230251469));
#609=CARTESIAN_POINT('',(2.02920067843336,64.7222579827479,77.7795434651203));
#610=CARTESIAN_POINT('',(1.93156475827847,64.8083884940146,77.7528257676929));
#611=CARTESIAN_POINT('',(1.88270406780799,64.8498512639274,77.739968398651));
#612=CARTESIAN_POINT('',(1.78480232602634,64.9294455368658,77.7152937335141));
#613=CARTESIAN_POINT('',(1.73581892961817,64.967641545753,77.703456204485));
#614=CARTESIAN_POINT('',(1.63769340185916,65.0407010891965,77.6808187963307));
#615=CARTESIAN_POINT('',(1.58860668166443,65.0756321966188,77.6699978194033));
#616=CARTESIAN_POINT('',(1.50723247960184,65.1306966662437,77.6529405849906));
#617=CARTESIAN_POINT('',(1.47545509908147,65.1515198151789,77.6464903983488));
#618=CARTESIAN_POINT('',(1.41182386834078,65.1918053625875,77.6340116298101));
#619=CARTESIAN_POINT('',(1.37998269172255,65.2112859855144,77.6279774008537));
#620=CARTESIAN_POINT('',(1.31623097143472,65.2488862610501,77.6163310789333));
#621=CARTESIAN_POINT('',(1.28433230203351,65.2670242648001,77.6107132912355));
#622=CARTESIAN_POINT('',(1.22047165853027,65.3019392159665,77.5999000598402));
#623=CARTESIAN_POINT('',(1.18852069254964,65.3187345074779,77.5946989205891));
#624=CARTESIAN_POINT('',(1.1245618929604,65.3509640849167,77.5847191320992));
#625=CARTESIAN_POINT('',(1.09256411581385,65.3664165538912,77.5799348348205));
#626=CARTESIAN_POINT('',(1.02851812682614,65.3959606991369,77.5707887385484));
#627=CARTESIAN_POINT('',(0.996478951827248,65.4100702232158,77.566421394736));
#628=CARTESIAN_POINT('',(0.932356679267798,65.4369288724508,77.5581090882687));
#629=CARTESIAN_POINT('',(0.900281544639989,65.4496953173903,77.5541587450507));
#630=CARTESIAN_POINT('',(0.836093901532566,65.4738684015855,77.5466801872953));
#631=CARTESIAN_POINT('',(0.803988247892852,65.4852916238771,77.5431468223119));
#632=CARTESIAN_POINT('',(0.739746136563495,65.5067790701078,77.5365018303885));
#633=CARTESIAN_POINT('',(0.70761541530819,65.5168589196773,77.5333853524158));
#634=CARTESIAN_POINT('',(0.643329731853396,65.5356606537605,77.5275736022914));
#635=CARTESIAN_POINT('',(0.611179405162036,65.5443969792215,77.5248738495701));
#636=CARTESIAN_POINT('',(0.546861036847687,65.560512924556,77.5198948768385));
#637=CARTESIAN_POINT('',(0.514696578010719,65.5679055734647,77.5176116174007));
#638=CARTESIAN_POINT('',(0.450356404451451,65.5813356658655,77.51346481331));
#639=CARTESIAN_POINT('',(0.418183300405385,65.5873845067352,77.5115977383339));
#640=CARTESIAN_POINT('',(0.35383218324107,65.5981286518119,77.5082823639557));
#641=CARTESIAN_POINT('',(0.321655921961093,65.6028335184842,77.5068311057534));
#642=CARTESIAN_POINT('',(0.257304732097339,65.6108917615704,77.5043462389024));
#643=CARTESIAN_POINT('',(0.225130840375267,65.614252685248,77.5033102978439));
#644=CARTESIAN_POINT('',(0.160790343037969,65.6196245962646,77.501655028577));
#645=CARTESIAN_POINT('',(0.128624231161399,65.6216409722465,77.5010340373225));
#646=CARTESIAN_POINT('',(0.0643054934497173,65.6243279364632,77.5002067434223));
#647=CARTESIAN_POINT('',(0.0321530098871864,65.6250016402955,77.4999994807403));
#648=CARTESIAN_POINT('',(8.90327741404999E-13,65.625,77.5));
#649=B_SPLINE_CURVE_WITH_KNOTS('',3,(#583,#584,#585,#586,#587,#588,#589,#590,#591,#592,#593,
#594,#595,#596,#597,#598,#599,#600,#601,#602,#603,#604,#605,#606,#607,#608,#609,#610,#611,#612,
#613,#614,#615,#616,#617,#618,#619,#620,#621,#622,#623,#624,#625,#626,#627,#628,#629,#630,#631,
#632,#633,#634,#635,#636,#637,#638,#639,#640,#641,#642,#643,#644,#645,#646,#647,#648),
.UNSPECIFIED.,.F.,.F.,(4,2,2,2,2,2,2,2,2,2,2,2,2,2,2,2,2,2,2,2,2,2,2,2,2,2,2,2,2,2,2,2,4),(0.,
0.428790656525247,0.840601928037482,1.31255029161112,1.67255991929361,2.10371031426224,
2.51422645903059,2.90449782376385,3.27497773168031,3.50653808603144,3.73058278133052,
3.9472956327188,4.15687974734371,4.35955966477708,4.55558365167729,4.74522611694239,
4.92879009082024,5.04438046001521,5.15779731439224,5.26914401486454,5.37852979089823,
5.4860698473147,5.59188541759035,5.69610375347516,5.79885804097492,5.90028723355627,
6.0005357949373,6.09975334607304,6.1980942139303,6.29571688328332,6.39278335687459,
6.48945843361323,6.58590891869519),.UNSPECIFIED.);
#650=CARTESIAN_POINT('',(4.3018232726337,61.2778492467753,78.8563596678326));
#651=VERTEX_POINT('',#650);
#652=CARTESIAN_POINT('',(0.,65.625,77.5));
#653=VERTEX_POINT('',#652);
#654=EDGE_CURVE('E1809',#651,#653,#649,.T.);
#655=ORIENTED_EDGE('',*,*,#654,.T.);
#656=DIRECTION('',(0.,-1.,0.));
#657=VECTOR('',#656,1.);
#658=CARTESIAN_POINT('',(8.90327741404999E-13,85.,77.5));
#659=LINE('',#658,#657);
#660=CARTESIAN_POINT('',(8.90327741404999E-13,20.,77.5));
#661=VERTEX_POINT('',#660);
#662=EDGE_CURVE('E659',#653,#661,#659,.T.);
#663=ORIENTED_EDGE('',*,*,#662,.T.);
#664=CARTESIAN_POINT('',(8.90327741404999E-13,20.,85.));
#665=DIRECTION('',(0.,-1.,0.));
#666=DIRECTION('',(1.,0.,0.));
#667=AXIS2_PLACEMENT_3D('',#664,#665,#666);
#668=CIRCLE('',#667,7.5);
#669=CARTESIAN_POINT('',(4.3018232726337,20.,78.8563596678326));
#670=VERTEX_POINT('',#669);
#671=EDGE_CURVE('E655',#661,#670,#668,.T.);
#672=ORIENTED_EDGE('',*,*,#671,.T.);
#673=DIRECTION('',(0.,-1.,0.));
#674=VECTOR('',#673,1.);
#675=CARTESIAN_POINT('',(4.3018232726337,85.,78.8563596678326));
#676=LINE('',#675,#674);
#677=EDGE_CURVE('E1431',#651,#670,#676,.T.);
#678=ORIENTED_EDGE('',*,*,#677,.F.);
#679=EDGE_LOOP('',(#655,#663,#672,#678));
#680=FACE_BOUND('',#679,.T.);
#681=ADVANCED_FACE('F1014',(#680),#582,.F.);
#682=CARTESIAN_POINT('',(-85.,85.,0.));
#683=DIRECTION('',(0.,-1.,0.));
#684=DIRECTION('',(0.,0.,-1.));
#685=AXIS2_PLACEMENT_3D('',#682,#683,#684);
#686=CYLINDRICAL_SURFACE('',#685,4.5);
#687=CARTESIAN_POINT('',(-85.,20.,0.));
#688=DIRECTION('',(0.,1.,0.));
#689=DIRECTION('',(0.,0.,-1.));
#690=AXIS2_PLACEMENT_3D('',#687,#688,#689);
#691=CIRCLE('',#690,4.5);
#692=CARTESIAN_POINT('',(-85.,20.,-4.5));
#693=VERTEX_POINT('',#692);
#694=CARTESIAN_POINT('',(-85.,20.,4.5));
#695=VERTEX_POINT('',#694);
#696=EDGE_CURVE('E660',#693,#695,#691,.T.);
#697=ORIENTED_EDGE('',*,*,#696,.T.);
#698=DIRECTION('',(0.,-1.,0.));
#699=VECTOR('',#698,1.);
#700=CARTESIAN_POINT('',(-85.,85.,4.5));
#701=LINE('',#700,#699);
#702=CARTESIAN_POINT('',(-85.,0.,4.5));
#703=VERTEX_POINT('',#702);
#704=EDGE_CURVE('E752',#695,#703,#701,.T.);
#705=ORIENTED_EDGE('',*,*,#704,.T.);
#706=CARTESIAN_POINT('',(-85.,0.,0.));
#707=DIRECTION('',(0.,-1.,0.));
#708=DIRECTION('',(0.,0.,1.));
#709=AXIS2_PLACEMENT_3D('',#706,#707,#708);
#710=CIRCLE('',#709,4.5);
#711=CARTESIAN_POINT('',(-85.,0.,-4.5));
#712=VERTEX_POINT('',#711);
#713=EDGE_CURVE('E756',#703,#712,#710,.T.);
#714=ORIENTED_EDGE('',*,*,#713,.T.);
#715=DIRECTION('',(0.,-1.,0.));
#716=VECTOR('',#715,1.);
#717=CARTESIAN_POINT('',(-85.,85.,-4.5));
#718=LINE('',#717,#716);
#719=EDGE_CURVE('E898',#693,#712,#718,.T.);
#720=ORIENTED_EDGE('',*,*,#719,.F.);
#721=EDGE_LOOP('',(#697,#705,#714,#720));
#722=FACE_BOUND('',#721,.T.);
#723=ADVANCED_FACE('F1793',(#722),#686,.F.);
#724=CARTESIAN_POINT('',(8.90327741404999E-13,85.,85.));
#725=DIRECTION('',(0.,-1.,0.));
#726=DIRECTION('',(0.,0.,-1.));
#727=AXIS2_PLACEMENT_3D('',#724,#725,#726);
#728=CYLINDRICAL_SURFACE('',#727,4.5);
#729=CARTESIAN_POINT('',(8.90327741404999E-13,20.,85.));
#730=DIRECTION('',(0.,1.,0.));
#731=DIRECTION('',(0.,0.,-1.));
#732=AXIS2_PLACEMENT_3D('',#729,#730,#731);
#733=CIRCLE('',#732,4.5);
#734=CARTESIAN_POINT('',(8.90327741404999E-13,20.,80.5));
#735=VERTEX_POINT('',#734);
#736=CARTESIAN_POINT('',(8.90878832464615E-13,20.,89.5));
#737=VERTEX_POINT('',#736);
#738=EDGE_CURVE('E619',#735,#737,#733,.T.);
#739=ORIENTED_EDGE('',*,*,#738,.T.);
#740=DIRECTION('',(0.,-1.,0.));
#741=VECTOR('',#740,1.);
#742=CARTESIAN_POINT('',(8.90878832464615E-13,85.,89.5));
#743=LINE('',#742,#741);
#744=CARTESIAN_POINT('',(8.90878832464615E-13,0.,89.5));
#745=VERTEX_POINT('',#744);
#746=EDGE_CURVE('E615',#737,#745,#743,.T.);
#747=ORIENTED_EDGE('',*,*,#746,.T.);
#748=CARTESIAN_POINT('',(8.90327741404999E-13,0.,85.));
#749=DIRECTION('',(0.,-1.,0.));
#750=DIRECTION('',(1.,0.,0.));
#751=AXIS2_PLACEMENT_3D('',#748,#749,#750);
#752=CIRCLE('',#751,4.5);
#753=CARTESIAN_POINT('',(8.90327741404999E-13,0.,80.5));
#754=VERTEX_POINT('',#753);
#755=EDGE_CURVE('E620',#745,#754,#752,.T.);
#756=ORIENTED_EDGE('',*,*,#755,.T.);
#757=DIRECTION('',(0.,-1.,0.));
#758=VECTOR('',#757,1.);
#759=CARTESIAN_POINT('',(8.90327741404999E-13,85.,80.5));
#760=LINE('',#759,#758);
#761=EDGE_CURVE('E813',#735,#754,#760,.T.);
#762=ORIENTED_EDGE('',*,*,#761,.F.);
#763=EDGE_LOOP('',(#739,#747,#756,#762));
#764=FACE_BOUND('',#763,.T.);
#765=ADVANCED_FACE('F1189',(#764),#728,.F.);
#766=CARTESIAN_POINT('',(-2.96775913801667E-13,85.,-85.));
#767=DIRECTION('',(0.,-1.,0.));
#768=DIRECTION('',(0.,0.,-1.));
#769=AXIS2_PLACEMENT_3D('',#766,#767,#768);
#770=CYLINDRICAL_SURFACE('',#769,4.5);
#771=CARTESIAN_POINT('',(-2.96775913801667E-13,20.,-85.));
#772=DIRECTION('',(0.,1.,0.));
#773=DIRECTION('',(0.,0.,-1.));
#774=AXIS2_PLACEMENT_3D('',#771,#772,#773);
#775=CIRCLE('',#774,4.5);
#776=CARTESIAN_POINT('',(-2.96775913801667E-13,20.,-89.5));
#777=VERTEX_POINT('',#776);
#778=CARTESIAN_POINT('',(-2.9622482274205E-13,20.,-80.5));
#779=VERTEX_POINT('',#778);
#780=EDGE_CURVE('E966',#777,#779,#775,.T.);
#781=ORIENTED_EDGE('',*,*,#780,.T.);
#782=DIRECTION('',(0.,-1.,0.));
#783=VECTOR('',#782,1.);
#784=CARTESIAN_POINT('',(-2.9622482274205E-13,85.,-80.5));
#785=LINE('',#784,#783);
#786=CARTESIAN_POINT('',(-2.9622482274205E-13,0.,-80.5));
#787=VERTEX_POINT('',#786);
#788=EDGE_CURVE('E736',#779,#787,#785,.T.);
#789=ORIENTED_EDGE('',*,*,#788,.T.);
#790=CARTESIAN_POINT('',(-2.96775913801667E-13,0.,-85.));
#791=DIRECTION('',(0.,-1.,0.));
#792=DIRECTION('',(-1.,0.,0.));
#793=AXIS2_PLACEMENT_3D('',#790,#791,#792);
#794=CIRCLE('',#793,4.5);
#795=CARTESIAN_POINT('',(-2.96775913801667E-13,0.,-89.5));
#796=VERTEX_POINT('',#795);
#797=EDGE_CURVE('E732',#787,#796,#794,.T.);
#798=ORIENTED_EDGE('',*,*,#797,.T.);
#799=DIRECTION('',(0.,-1.,0.));
#800=VECTOR('',#799,1.);
#801=CARTESIAN_POINT('',(-2.96775913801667E-13,85.,-89.5));
#802=LINE('',#801,#800);
#803=EDGE_CURVE('E607',#777,#796,#802,.T.);
#804=ORIENTED_EDGE('',*,*,#803,.F.);
#805=EDGE_LOOP('',(#781,#789,#798,#804));
#806=FACE_BOUND('',#805,.T.);
#807=ADVANCED_FACE('F1186',(#806),#770,.F.);
#808=CARTESIAN_POINT('',(85.,85.,0.));
#809=DIRECTION('',(0.,-1.,0.));
#810=DIRECTION('',(0.,0.,-1.));
#811=AXIS2_PLACEMENT_3D('',#808,#809,#810);
#812=CYLINDRICAL_SURFACE('',#811,4.5);
#813=CARTESIAN_POINT('',(85.,20.,0.));
#814=DIRECTION('',(0.,1.,0.));
#815=DIRECTION('',(0.,0.,-1.));
#816=AXIS2_PLACEMENT_3D('',#813,#814,#815);
#817=CIRCLE('',#816,4.5);
#818=CARTESIAN_POINT('',(85.,20.,-4.5));
#819=VERTEX_POINT('',#818);
#820=CARTESIAN_POINT('',(85.,20.,4.5));
#821=VERTEX_POINT('',#820);
#822=EDGE_CURVE('E737',#819,#821,#817,.T.);
#823=ORIENTED_EDGE('',*,*,#822,.T.);
#824=DIRECTION('',(0.,-1.,0.));
#825=VECTOR('',#824,1.);
#826=CARTESIAN_POINT('',(85.,85.,4.5));
#827=LINE('',#826,#825);
#828=CARTESIAN_POINT('',(85.,0.,4.5));
#829=VERTEX_POINT('',#828);
#830=EDGE_CURVE('E742',#821,#829,#827,.T.);
#831=ORIENTED_EDGE('',*,*,#830,.T.);
#832=CARTESIAN_POINT('',(85.,0.,0.));
#833=DIRECTION('',(0.,-1.,0.));
#834=DIRECTION('',(0.,0.,-1.));
#835=AXIS2_PLACEMENT_3D('',#832,#833,#834);
#836=CIRCLE('',#835,4.5);
#837=CARTESIAN_POINT('',(85.,0.,-4.5));
#838=VERTEX_POINT('',#837);
#839=EDGE_CURVE('E738',#829,#838,#836,.T.);
#840=ORIENTED_EDGE('',*,*,#839,.T.);
#841=DIRECTION('',(0.,-1.,0.));
#842=VECTOR('',#841,1.);
#843=CARTESIAN_POINT('',(85.,85.,-4.5));
#844=LINE('',#843,#842);
#845=EDGE_CURVE('E599',#819,#838,#844,.T.);
#846=ORIENTED_EDGE('',*,*,#845,.F.);
#847=EDGE_LOOP('',(#823,#831,#840,#846));
#848=FACE_BOUND('',#847,.T.);
#849=ADVANCED_FACE('F1016',(#848),#812,.F.);
#850=CARTESIAN_POINT('',(0.,76.2976725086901,0.));
#851=DIRECTION('',(0.,1.,0.));
#852=DIRECTION('',(0.,0.,1.));
#853=AXIS2_PLACEMENT_3D('',#850,#851,#852);
#854=TOROIDAL_SURFACE('',#853,95.,20.);
#855=CARTESIAN_POINT('',(0.,76.2976725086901,0.));
#856=DIRECTION('',(0.,1.,0.));
#857=DIRECTION('',(0.,0.,1.));
#858=AXIS2_PLACEMENT_3D('',#855,#856,#857);
#859=CIRCLE('',#858,75.);
#860=CARTESIAN_POINT('',(0.,76.2976725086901,-75.));
#861=VERTEX_POINT('',#860);
#862=CARTESIAN_POINT('',(0.,76.2976725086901,75.));
#863=VERTEX_POINT('',#862);
#864=EDGE_CURVE('E779',#861,#863,#859,.T.);
#865=ORIENTED_EDGE('',*,*,#864,.F.);
#866=CARTESIAN_POINT('',(0.,76.2976725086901,-95.));
#867=DIRECTION('',(1.,0.,0.));
#868=DIRECTION('',(0.,0.,-1.));
#869=AXIS2_PLACEMENT_3D('',#866,#867,#868);
#870=CIRCLE('',#869,20.);
#871=CARTESIAN_POINT('',(0.,69.8768868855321,-76.058682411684));
#872=VERTEX_POINT('',#871);
#873=EDGE_CURVE('E685',#861,#872,#870,.T.);
#874=ORIENTED_EDGE('',*,*,#873,.T.);
#875=CARTESIAN_POINT('',(0.,69.8768868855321,0.));
#876=DIRECTION('',(0.,-1.,0.));
#877=DIRECTION('',(0.,0.,-1.));
#878=AXIS2_PLACEMENT_3D('',#875,#876,#877);
#879=CIRCLE('',#878,76.058682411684);
#880=CARTESIAN_POINT('',(0.,69.8768868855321,76.058682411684));
#881=VERTEX_POINT('',#880);
#882=EDGE_CURVE('E577',#881,#872,#879,.T.);
#883=ORIENTED_EDGE('',*,*,#882,.F.);
#884=CARTESIAN_POINT('',(0.,76.2976725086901,95.));
#885=DIRECTION('',(-1.,0.,0.));
#886=DIRECTION('',(0.,0.,1.));
#887=AXIS2_PLACEMENT_3D('',#884,#885,#886);
#888=CIRCLE('',#887,20.);
#889=EDGE_CURVE('E952',#863,#881,#888,.T.);
#890=ORIENTED_EDGE('',*,*,#889,.F.);
#891=EDGE_LOOP('',(#865,#874,#883,#890));
#892=FACE_BOUND('',#891,.T.);
#893=ADVANCED_FACE('F1452',(#892),#854,.F.);
#894=CARTESIAN_POINT('',(0.,100.390423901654,0.));
#895=DIRECTION('',(0.,1.,0.));
#896=DIRECTION('',(0.,0.,1.));
#897=AXIS2_PLACEMENT_3D('',#894,#895,#896);
#898=CYLINDRICAL_SURFACE('',#897,70.);
#899=DIRECTION('',(0.,1.,0.));
#900=VECTOR('',#899,1.);
#901=CARTESIAN_POINT('',(0.,100.390423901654,-70.));
#902=LINE('',#901,#900);
#903=CARTESIAN_POINT('',(0.,0.,-70.));
#904=VERTEX_POINT('',#903);
#905=CARTESIAN_POINT('',(0.,15.,-70.));
#906=VERTEX_POINT('',#905);
#907=EDGE_CURVE('E543',#904,#906,#902,.T.);
#908=ORIENTED_EDGE('',*,*,#907,.T.);
#909=CARTESIAN_POINT('',(0.,15.,0.));
#910=DIRECTION('',(0.,-1.,0.));
#911=DIRECTION('',(0.,0.,-1.));
#912=AXIS2_PLACEMENT_3D('',#909,#910,#911);
#913=CIRCLE('',#912,70.);
#914=CARTESIAN_POINT('',(0.,15.,70.));
#915=VERTEX_POINT('',#914);
#916=EDGE_CURVE('E30',#915,#906,#913,.T.);
#917=ORIENTED_EDGE('',*,*,#916,.F.);
#918=DIRECTION('',(0.,1.,0.));
#919=VECTOR('',#918,1.);
#920=CARTESIAN_POINT('',(0.,100.390423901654,70.));
#921=LINE('',#920,#919);
#922=CARTESIAN_POINT('',(0.,0.,70.));
#923=VERTEX_POINT('',#922);
#924=EDGE_CURVE('E541',#923,#915,#921,.T.);
#925=ORIENTED_EDGE('',*,*,#924,.F.);
#926=CARTESIAN_POINT('',(0.,0.,0.));
#927=DIRECTION('',(0.,1.,0.));
#928=DIRECTION('',(0.,0.,1.));
#929=AXIS2_PLACEMENT_3D('',#926,#927,#928);
#930=CIRCLE('',#929,70.);
#931=EDGE_CURVE('E567',#904,#923,#930,.T.);
#932=ORIENTED_EDGE('',*,*,#931,.F.);
#933=EDGE_LOOP('',(#908,#917,#925,#932));
#934=FACE_BOUND('',#933,.T.);
#935=ADVANCED_FACE('F540',(#934),#898,.F.);
#936=CARTESIAN_POINT('',(0.,100.390423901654,0.));
#937=DIRECTION('',(0.,1.,0.));
#938=DIRECTION('',(0.,0.,1.));
#939=AXIS2_PLACEMENT_3D('',#936,#937,#938);
#940=CYLINDRICAL_SURFACE('',#939,95.);
#941=CARTESIAN_POINT('',(0.,0.,0.));
#942=DIRECTION('',(0.,1.,0.));
#943=DIRECTION('',(0.,0.,1.));
#944=AXIS2_PLACEMENT_3D('',#941,#942,#943);
#945=CIRCLE('',#944,95.);
#946=CARTESIAN_POINT('',(62.7983915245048,0.,-71.2836728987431));
#947=VERTEX_POINT('',#946);
#948=CARTESIAN_POINT('',(0.,0.,-95.));
#949=VERTEX_POINT('',#948);
#950=EDGE_CURVE('E727',#947,#949,#945,.T.);
#951=ORIENTED_EDGE('',*,*,#950,.T.);
#952=DIRECTION('',(0.,1.,0.));
#953=VECTOR('',#952,1.);
#954=CARTESIAN_POINT('',(0.,100.390423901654,-95.));
#955=LINE('',#954,#953);
#956=EDGE_CURVE('E767',#949,#565,#955,.T.);
#957=ORIENTED_EDGE('',*,*,#956,.T.);
#958=ORIENTED_EDGE('',*,*,#566,.T.);
#959=CARTESIAN_POINT('',(63.7535075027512,10.7023274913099,-70.4307481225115));
#960=CARTESIAN_POINT('',(63.7152146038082,10.6365455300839,-70.4654106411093));
#961=CARTESIAN_POINT('',(63.6778878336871,10.5697076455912,-70.4991417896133));
#962=CARTESIAN_POINT('',(63.6054574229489,10.4343647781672,-70.5644964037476));
#963=CARTESIAN_POINT('',(63.5703431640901,10.3658703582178,-70.5961299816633));
#964=CARTESIAN_POINT('',(63.5023463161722,10.2272145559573,-70.6573003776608));
#965=CARTESIAN_POINT('',(63.4694562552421,10.1570599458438,-70.6868442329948));
#966=CARTESIAN_POINT('',(63.4059125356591,10.0150886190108,-70.7438483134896));
#967=CARTESIAN_POINT('',(63.3752549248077,9.94327515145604,-70.7713122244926));
#968=CARTESIAN_POINT('',(63.3161806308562,9.79798932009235,-70.8241684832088));
#969=CARTESIAN_POINT('',(63.2877638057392,9.72451706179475,-70.8495609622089));
#970=CARTESIAN_POINT('',(63.2331745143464,9.57591684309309,-70.8982861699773));
#971=CARTESIAN_POINT('',(63.2070059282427,9.50078629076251,-70.9216153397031));
#972=CARTESIAN_POINT('',(63.1569158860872,9.34887196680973,-70.9662250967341));
#973=CARTESIAN_POINT('',(63.1330024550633,9.27208340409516,-70.987498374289));
#974=CARTESIAN_POINT('',(63.0874245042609,9.11685559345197,-71.0280071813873));
#975=CARTESIAN_POINT('',(63.0657721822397,9.03840988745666,-71.0472316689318));
#976=CARTESIAN_POINT('',(63.024835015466,8.88031690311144,-71.0835488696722));
#977=CARTESIAN_POINT('',(63.0055528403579,8.80066838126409,-71.100639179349));
#978=CARTESIAN_POINT('',(62.9695621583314,8.64078897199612,-71.1325158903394));
#979=CARTESIAN_POINT('',(62.9528407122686,8.5605633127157,-71.1473138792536));
#980=CARTESIAN_POINT('',(62.9219722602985,8.39953255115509,-71.1746150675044));
#981=CARTESIAN_POINT('',(62.9078163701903,8.31873049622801,-71.1871261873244));
#982=CARTESIAN_POINT('',(62.8820789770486,8.15654897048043,-71.209861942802));
#983=CARTESIAN_POINT('',(62.8704929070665,8.07517079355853,-71.2200906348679));
#984=CARTESIAN_POINT('',(62.8498941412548,7.91183876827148,-71.2382691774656));
#985=CARTESIAN_POINT('',(62.8408813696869,7.82988493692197,-71.2462190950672));
#986=CARTESIAN_POINT('',(62.8254269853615,7.66540270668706,-71.2598472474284));
#987=CARTESIAN_POINT('',(62.8189898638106,7.58287355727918,-71.2655215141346));
#988=CARTESIAN_POINT('',(62.8086850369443,7.41724169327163,-71.2746037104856));
#989=CARTESIAN_POINT('',(62.8048263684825,7.33413798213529,-71.2780036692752));
#990=CARTESIAN_POINT('',(62.7996713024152,7.16735592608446,-71.2825454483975));
#991=CARTESIAN_POINT('',(62.7983883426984,7.0836768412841,-71.2836754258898));
#992=CARTESIAN_POINT('',(62.798391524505,6.99999999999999,-71.283672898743));
#993=B_SPLINE_CURVE_WITH_KNOTS('',3,(#959,#960,#961,#962,#963,#964,#965,#966,#967,#968,#969,
#970,#971,#972,#973,#974,#975,#976,#977,#978,#979,#980,#981,#982,#983,#984,#985,#986,#987,#988,
#989,#990,#991,#992),.UNSPECIFIED.,.F.,.F.,(4,2,2,2,2,2,2,2,2,2,2,2,2,2,2,2,4),(0.,
0.250895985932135,0.50047810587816,0.749175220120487,0.997420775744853,1.24565058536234,
1.49430054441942,1.74380434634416,1.9945912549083,2.24565810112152,2.49541120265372,
2.74428218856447,2.99270728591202,3.24112507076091,3.48997415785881,3.73969088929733,
3.99070708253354),.UNSPECIFIED.);
#994=CARTESIAN_POINT('',(62.7983915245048,7.,-71.2836728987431));
#995=VERTEX_POINT('',#994);
#996=EDGE_CURVE('E889',#556,#995,#993,.T.);
#997=ORIENTED_EDGE('',*,*,#996,.T.);
#998=DIRECTION('',(0.,1.,0.));
#999=VECTOR('',#998,1.);
#1000=CARTESIAN_POINT('',(62.7983915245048,100.390423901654,-71.2836728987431));
#1001=LINE('',#1000,#999);
#1002=EDGE_CURVE('E705',#947,#995,#1001,.T.);
#1003=ORIENTED_EDGE('',*,*,#1002,.F.);
#1004=EDGE_LOOP('',(#951,#957,#958,#997,#1003));
#1005=FACE_BOUND('',#1004,.T.);
#1006=ADVANCED_FACE('F1058',(#1005),#940,.T.);
#1007=CARTESIAN_POINT('',(0.,100.390423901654,0.));
#1008=DIRECTION('',(0.,1.,0.));
#1009=DIRECTION('',(0.,0.,1.));
#1010=AXIS2_PLACEMENT_3D('',#1007,#1008,#1009);
#1011=CYLINDRICAL_SURFACE('',#1010,95.);
#1012=ORIENTED_EDGE('',*,*,#956,.F.);
#1013=CARTESIAN_POINT('',(0.,0.,0.));
#1014=DIRECTION('',(0.,1.,0.));
#1015=DIRECTION('',(0.,0.,1.));
#1016=AXIS2_PLACEMENT_3D('',#1013,#1014,#1015);
#1017=CIRCLE('',#1016,95.);
#1018=CARTESIAN_POINT('',(0.,0.,95.));
#1019=VERTEX_POINT('',#1018);
#1020=EDGE_CURVE('E586',#949,#1019,#1017,.T.);
#1021=ORIENTED_EDGE('',*,*,#1020,.T.);
#1022=DIRECTION('',(0.,1.,0.));
#1023=VECTOR('',#1022,1.);
#1024=CARTESIAN_POINT('',(0.,100.390423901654,95.));
#1025=LINE('',#1024,#1023);
#1026=EDGE_CURVE('E582',#1019,#469,#1025,.T.);
#1027=ORIENTED_EDGE('',*,*,#1026,.T.);
#1028=CARTESIAN_POINT('',(0.,10.7023274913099,0.));
#1029=DIRECTION('',(0.,-1.,0.));
#1030=DIRECTION('',(0.,0.,-1.));
#1031=AXIS2_PLACEMENT_3D('',#1028,#1029,#1030);
#1032=CIRCLE('',#1031,95.);
#1033=EDGE_CURVE('E587',#469,#565,#1032,.T.);
#1034=ORIENTED_EDGE('',*,*,#1033,.T.);
#1035=EDGE_LOOP('',(#1012,#1021,#1027,#1034));
#1036=FACE_BOUND('',#1035,.T.);
#1037=ADVANCED_FACE('F1567',(#1036),#1011,.T.);
#1038=CARTESIAN_POINT('',(0.,73.,0.));
#1039=DIRECTION('',(0.,-1.,0.));
#1040=DIRECTION('',(0.,0.,-1.));
#1041=AXIS2_PLACEMENT_3D('',#1038,#1039,#1040);
#1042=CONICAL_SURFACE('',#1041,75.,0.32682665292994);
#1043=CARTESIAN_POINT('',(0.,69.8768868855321,0.));
#1044=DIRECTION('',(0.,-1.,0.));
#1045=DIRECTION('',(0.,0.,-1.));
#1046=AXIS2_PLACEMENT_3D('',#1043,#1044,#1045);
#1047=CIRCLE('',#1046,76.058682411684);
#1048=EDGE_CURVE('E645',#872,#881,#1047,.T.);
#1049=ORIENTED_EDGE('',*,*,#1048,.T.);
#1050=DIRECTION('',(0.,-0.947065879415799,0.321039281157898));
#1051=VECTOR('',#1050,1.);
#1052=CARTESIAN_POINT('',(0.,73.,75.));
#1053=LINE('',#1052,#1051);
#1054=EDGE_CURVE('E649',#881,#653,#1053,.T.);
#1055=ORIENTED_EDGE('',*,*,#1054,.T.);
#1056=ORIENTED_EDGE('',*,*,#654,.F.);
#1057=CARTESIAN_POINT('',(21.0157340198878,20.,90.5595659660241));
#1058=CARTESIAN_POINT('',(16.8320417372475,31.2081645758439,87.6301130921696));
#1059=CARTESIAN_POINT('',(12.9658213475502,40.8242057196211,84.9229564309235));
#1060=CARTESIAN_POINT('',(8.45174540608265,52.0515894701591,81.7621664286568));
#1061=CARTESIAN_POINT('',(4.3018232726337,61.2778492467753,78.8563596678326));
#1062=B_SPLINE_CURVE_WITH_KNOTS('',2,(#1057,#1058,#1059,#1060,#1061),.UNSPECIFIED.,.F.,.F.,(3,2,
3),(0.,0.5,1.),.UNSPECIFIED.);
#1063=CARTESIAN_POINT('',(21.0157340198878,20.,90.559565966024));
#1064=VERTEX_POINT('',#1063);
#1065=EDGE_CURVE('E1821',#1064,#651,#1062,.T.);
#1066=ORIENTED_EDGE('',*,*,#1065,.F.);
#1067=CARTESIAN_POINT('',(0.,20.,0.));
#1068=DIRECTION('',(0.,1.,0.));
#1069=DIRECTION('',(0.,0.,-1.));
#1070=AXIS2_PLACEMENT_3D('',#1067,#1068,#1069);
#1071=CIRCLE('',#1070,92.9661016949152);
#1072=CARTESIAN_POINT('',(0.,20.,92.9661016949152));
#1073=VERTEX_POINT('',#1072);
#1074=EDGE_CURVE('E1427',#1073,#1064,#1071,.T.);
#1075=ORIENTED_EDGE('',*,*,#1074,.F.);
#1076=DIRECTION('',(0.,-0.947065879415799,0.321039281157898));
#1077=VECTOR('',#1076,1.);
#1078=CARTESIAN_POINT('',(0.,73.,75.));
#1079=LINE('',#1078,#1077);
#1080=EDGE_CURVE('E942',#1073,#458,#1079,.T.);
#1081=ORIENTED_EDGE('',*,*,#1080,.T.);
#1082=ORIENTED_EDGE('',*,*,#461,.T.);
#1083=DIRECTION('',(0.,-0.947065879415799,-0.321039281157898));
#1084=VECTOR('',#1083,1.);
#1085=CARTESIAN_POINT('',(0.,73.,-75.));
#1086=LINE('',#1085,#1084);
#1087=CARTESIAN_POINT('',(0.,20.,-92.9661016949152));
#1088=VERTEX_POINT('',#1087);
#1089=EDGE_CURVE('E793',#1088,#460,#1086,.T.);
#1090=ORIENTED_EDGE('',*,*,#1089,.F.);
#1091=CARTESIAN_POINT('',(0.,20.,0.));
#1092=DIRECTION('',(0.,1.,0.));
#1093=DIRECTION('',(0.,0.,-1.));
#1094=AXIS2_PLACEMENT_3D('',#1091,#1092,#1093);
#1095=CIRCLE('',#1094,92.9661016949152);
#1096=CARTESIAN_POINT('',(21.0157340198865,20.,-90.5595659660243));
#1097=VERTEX_POINT('',#1096);
#1098=EDGE_CURVE('E899',#1097,#1088,#1095,.T.);
#1099=ORIENTED_EDGE('',*,*,#1098,.F.);
#1100=CARTESIAN_POINT('',(4.3018232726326,61.2778492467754,-78.8563596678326));
#1101=CARTESIAN_POINT('',(8.45156624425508,52.0519877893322,-81.7620409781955));
#1102=CARTESIAN_POINT('',(12.965821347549,40.8242057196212,-84.9229564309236));
#1103=CARTESIAN_POINT('',(16.831830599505,31.2087302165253,-87.6299652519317));
#1104=CARTESIAN_POINT('',(21.0157340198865,20.,-90.5595659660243));
#1105=B_SPLINE_CURVE_WITH_KNOTS('',2,(#1100,#1101,#1102,#1103,#1104),.UNSPECIFIED.,.F.,.F.,(3,2,
3),(0.,0.5,1.),.UNSPECIFIED.);
#1106=CARTESIAN_POINT('',(4.3018232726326,61.2778492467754,-78.8563596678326));
#1107=VERTEX_POINT('',#1106);
#1108=EDGE_CURVE('E762',#1107,#1097,#1105,.T.);
#1109=ORIENTED_EDGE('',*,*,#1108,.F.);
#1110=CARTESIAN_POINT('',(0.,65.625,-77.5));
#1111=CARTESIAN_POINT('',(0.0427781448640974,65.6250050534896,-77.4999983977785));
#1112=CARTESIAN_POINT('',(0.0855542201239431,65.6238103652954,-77.5003659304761));
#1113=CARTESIAN_POINT('',(0.171128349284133,65.6190548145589,-77.5018304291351));
#1114=CARTESIAN_POINT('',(0.213925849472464,65.6154848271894,-77.5029302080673));
#1115=CARTESIAN_POINT('',(0.299529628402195,65.6059799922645,-77.5058602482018));
#1116=CARTESIAN_POINT('',(0.342333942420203,65.6000290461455,-77.5076954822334));
#1117=CARTESIAN_POINT('',(0.427940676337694,65.58577071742,-77.5120950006));
#1118=CARTESIAN_POINT('',(0.470738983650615,65.5774408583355,-77.5146662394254));
#1119=CARTESIAN_POINT('',(0.556323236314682,65.5584304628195,-77.5205369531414));
#1120=CARTESIAN_POINT('',(0.599102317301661,65.5477217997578,-77.5238451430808));
#1121=CARTESIAN_POINT('',(0.68463829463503,65.5239592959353,-77.5311887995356));
#1122=CARTESIAN_POINT('',(0.727385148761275,65.5108725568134,-77.5352344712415));
#1123=CARTESIAN_POINT('',(0.812847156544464,65.4823583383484,-77.5440522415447));
#1124=CARTESIAN_POINT('',(0.855548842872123,65.4668941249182,-77.5488357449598));
#1125=CARTESIAN_POINT('',(0.940911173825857,65.4336284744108,-77.5591283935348));
#1126=CARTESIAN_POINT('',(0.983554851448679,65.4157874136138,-77.5646498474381));
#1127=CARTESIAN_POINT('',(1.06879181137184,65.3777706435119,-77.5764176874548));
#1128=CARTESIAN_POINT('',(1.11136470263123,65.3575533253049,-77.5826770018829));
#1129=CARTESIAN_POINT('',(1.19645062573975,65.3147856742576,-77.5959199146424));
#1130=CARTESIAN_POINT('',(1.23894004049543,65.2921925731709,-77.6029167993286));
#1131=CARTESIAN_POINT('',(1.32384917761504,65.2446744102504,-77.6176342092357));
#1132=CARTESIAN_POINT('',(1.3662423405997,65.2197061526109,-77.6253681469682));
#1133=CARTESIAN_POINT('',(1.45094927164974,65.167437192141,-77.6415591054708));
#1134=CARTESIAN_POINT('',(1.49323389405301,65.1400934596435,-77.6500294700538));
#1135=CARTESIAN_POINT('',(1.5679057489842,65.0896943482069,-77.6656420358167));
#1136=CARTESIAN_POINT('',(1.60051446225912,65.0669371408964,-77.6726918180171));
#1137=CARTESIAN_POINT('',(1.66570721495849,65.0200016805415,-77.6872331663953));
#1138=CARTESIAN_POINT('',(1.69827533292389,64.9958032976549,-77.6947310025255));
#1139=CARTESIAN_POINT('',(1.79701892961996,64.9202466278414,-77.7181457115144));
#1140=CARTESIAN_POINT('',(1.86199108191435,64.8674473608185,-77.7345128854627));
#1141=CARTESIAN_POINT('',(1.99182643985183,64.7562382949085,-77.7690013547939));
#1142=CARTESIAN_POINT('',(2.05655166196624,64.6976827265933,-77.7871685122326));
#1143=CARTESIAN_POINT('',(2.1858523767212,64.5749452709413,-77.8252668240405));
#1144=CARTESIAN_POINT('',(2.25028695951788,64.5106286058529,-77.8452406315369));
#1145=CARTESIAN_POINT('',(2.37895393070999,64.376358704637,-77.8869586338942));
#1146=CARTESIAN_POINT('',(2.4430443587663,64.3062821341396,-77.9087420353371));
#1147=CARTESIAN_POINT('',(2.57097384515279,64.1604815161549,-77.9540860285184));
#1148=CARTESIAN_POINT('',(2.63467191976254,64.0846452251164,-77.9776824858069));
#1149=CARTESIAN_POINT('',(2.74353611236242,63.9498607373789,-78.0196337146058));
#1150=CARTESIAN_POINT('',(2.78937189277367,63.8914021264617,-78.0378329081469));
#1151=CARTESIAN_POINT('',(2.880946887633,63.7713612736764,-78.075213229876));
#1152=CARTESIAN_POINT('',(2.92663020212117,63.7097403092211,-78.094406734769));
#1153=CARTESIAN_POINT('',(3.0657658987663,63.5170644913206,-78.1544443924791));
#1154=CARTESIAN_POINT('',(3.15647711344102,63.384206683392,-78.1958760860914));
#1155=CARTESIAN_POINT('',(3.33742971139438,63.1061169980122,-78.2826885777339));
#1156=CARTESIAN_POINT('',(3.42725602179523,62.960642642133,-78.3281508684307));
#1157=CARTESIAN_POINT('',(3.60622305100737,62.6572681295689,-78.42306772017));
#1158=CARTESIAN_POINT('',(3.69497061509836,62.4991593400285,-78.4725942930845));
#1159=CARTESIAN_POINT('',(3.87156372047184,62.1704960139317,-78.5756646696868));
#1160=CARTESIAN_POINT('',(3.95903770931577,61.9997627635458,-78.6292715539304));
#1161=CARTESIAN_POINT('',(4.13281860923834,61.6457841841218,-78.7405311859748));
#1162=CARTESIAN_POINT('',(4.21877178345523,61.4623822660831,-78.7982398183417));
#1163=CARTESIAN_POINT('',(4.3018232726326,61.2778492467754,-78.8563596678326));
#1164=B_SPLINE_CURVE_WITH_KNOTS('',3,(#1110,#1111,#1112,#1113,#1114,#1115,#1116,#1117,#1118,
#1119,#1120,#1121,#1122,#1123,#1124,#1125,#1126,#1127,#1128,#1129,#1130,#1131,#1132,#1133,#1134,
#1135,#1136,#1137,#1138,#1139,#1140,#1141,#1142,#1143,#1144,#1145,#1146,#1147,#1148,#1149,#1150,
#1151,#1152,#1153,#1154,#1155,#1156,#1157,#1158,#1159,#1160,#1161,#1162,#1163),.UNSPECIFIED.,
.F.,.F.,(4,2,2,2,2,2,2,2,2,2,2,2,2,2,2,2,2,2,2,2,2,2,2,2,2,2,4),(0.,0.128312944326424,
0.257121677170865,0.386816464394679,0.517779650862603,0.65038261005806,0.784983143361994,
0.921923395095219,1.06152830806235,1.2041046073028,1.34994027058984,1.49930442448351,
1.65244759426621,1.77358307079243,1.89734978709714,2.15312017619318,2.42046499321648,
2.69997841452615,2.99218039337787,3.29752607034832,3.52694617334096,3.76414013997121,
4.26229393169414,4.79287963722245,5.35660116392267,5.95404530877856,6.585704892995),.UNSPECIFIED.);
#1165=CARTESIAN_POINT('',(0.,65.625,-77.5));
#1166=VERTEX_POINT('',#1165);
#1167=EDGE_CURVE('E1138',#1166,#1107,#1164,.T.);
#1168=ORIENTED_EDGE('',*,*,#1167,.F.);
#1169=DIRECTION('',(0.,-0.947065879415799,-0.321039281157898));
#1170=VECTOR('',#1169,1.);
#1171=CARTESIAN_POINT('',(0.,73.,-75.));
#1172=LINE('',#1171,#1170);
#1173=EDGE_CURVE('E581',#872,#1166,#1172,.T.);
#1174=ORIENTED_EDGE('',*,*,#1173,.F.);
#1175=EDGE_LOOP('',(#1049,#1055,#1056,#1066,#1075,#1081,#1082,#1090,#1099,#1109,#1168,#1174));
#1176=FACE_BOUND('',#1175,.T.);
#1177=CARTESIAN_POINT('',(78.8563596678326,61.2778492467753,-4.30182327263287));
#1178=CARTESIAN_POINT('',(78.8114921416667,61.4202968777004,-4.23772721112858));
#1179=CARTESIAN_POINT('',(78.7668894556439,61.5620752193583,-4.17191106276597));
#1180=CARTESIAN_POINT('',(78.6802955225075,61.8375854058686,-4.03947399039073));
#1181=CARTESIAN_POINT('',(78.6382774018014,61.9713911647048,-3.97302408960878));
#1182=CARTESIAN_POINT('',(78.5646145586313,62.2061164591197,-3.85221613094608));
#1183=CARTESIAN_POINT('',(78.5328413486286,62.3074106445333,-3.79866331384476));
#1184=CARTESIAN_POINT('',(78.4475129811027,62.5795866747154,-3.6505530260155));
#1185=CARTESIAN_POINT('',(78.394349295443,62.7493231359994,-3.55363792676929));
#1186=CARTESIAN_POINT('',(78.3008599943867,63.0481974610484,-3.37334920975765));
#1187=CARTESIAN_POINT('',(78.2602377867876,63.1781982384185,-3.29156118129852));
#1188=CARTESIAN_POINT('',(78.1823638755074,63.427648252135,-3.12692594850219));
#1189=CARTESIAN_POINT('',(78.1450502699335,63.5472825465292,-3.04438976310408));
#1190=CARTESIAN_POINT('',(78.0737751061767,63.7759811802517,-2.87838442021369));
#1191=CARTESIAN_POINT('',(78.0397440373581,63.8852582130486,-2.79524027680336));
#1192=CARTESIAN_POINT('',(77.9856975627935,64.0588895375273,-2.65571834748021));
#1193=CARTESIAN_POINT('',(77.9652607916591,64.1245654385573,-2.60114614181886));
#1194=CARTESIAN_POINT('',(77.9257418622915,64.2516134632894,-2.49161328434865));
#1195=CARTESIAN_POINT('',(77.9066375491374,64.3130549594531,-2.43674136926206));
#1196=CARTESIAN_POINT('',(77.8697842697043,64.4316271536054,-2.32664278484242));
#1197=CARTESIAN_POINT('',(77.8520113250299,64.4888331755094,-2.27150545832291));
#1198=CARTESIAN_POINT('',(77.8178206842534,64.5989289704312,-2.16090813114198));
#1199=CARTESIAN_POINT('',(77.8013771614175,64.6519001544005,-2.10553741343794));
#1200=CARTESIAN_POINT('',(77.7698448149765,64.7535190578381,-1.99450765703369));
#1201=CARTESIAN_POINT('',(77.7547283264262,64.8022543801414,-1.938936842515));
#1202=CARTESIAN_POINT('',(77.7258473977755,64.8953987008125,-1.82753676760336));
#1203=CARTESIAN_POINT('',(77.7120535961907,64.9399011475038,-1.77179371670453));
#1204=CARTESIAN_POINT('',(77.6921956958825,65.0039839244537,-1.6872471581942));
#1205=CARTESIAN_POINT('',(77.6858015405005,65.0246209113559,-1.65931790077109));
#1206=CARTESIAN_POINT('',(77.6733465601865,65.0648229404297,-1.60341959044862));
#1207=CARTESIAN_POINT('',(77.6672817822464,65.0844006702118,-1.57546055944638));
#1208=CARTESIAN_POINT('',(77.6537908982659,65.1279512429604,-1.51147188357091));
#1209=CARTESIAN_POINT('',(77.6464329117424,65.1517043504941,-1.47527778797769));
#1210=CARTESIAN_POINT('',(77.6322651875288,65.1974414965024,-1.40278944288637));
#1211=CARTESIAN_POINT('',(77.6254470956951,65.2194524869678,-1.36651385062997));
#1212=CARTESIAN_POINT('',(77.6123596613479,65.2617056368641,-1.29387169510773));
#1213=CARTESIAN_POINT('',(77.6060818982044,65.2819749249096,-1.25752245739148));
#1214=CARTESIAN_POINT('',(77.5940754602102,65.3207444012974,-1.18474254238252));
#1215=CARTESIAN_POINT('',(77.5883383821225,65.3392716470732,-1.14832768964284));
#1216=CARTESIAN_POINT('',(77.5774134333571,65.3745572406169,-1.07542618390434));
#1217=CARTESIAN_POINT('',(77.5722172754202,65.3913422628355,-1.03895370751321));
#1218=CARTESIAN_POINT('',(77.5623740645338,65.4231438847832,-0.965946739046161));
#1219=CARTESIAN_POINT('',(77.5577189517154,65.4381864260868,-0.92942465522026));
#1220=CARTESIAN_POINT('',(77.5489574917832,65.4665039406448,-0.856328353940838));
#1221=CARTESIAN_POINT('',(77.5448434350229,65.4798037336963,-0.819764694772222));
#1222=CARTESIAN_POINT('',(77.53716350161,65.5046370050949,-0.74659518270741));
#1223=CARTESIAN_POINT('',(77.5335903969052,65.5161937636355,-0.709998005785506));
#1224=CARTESIAN_POINT('',(77.5269915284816,65.5375426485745,-0.636771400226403));
#1225=CARTESIAN_POINT('',(77.523959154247,65.5473560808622,-0.60014879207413));
#1226=CARTESIAN_POINT('',(77.5184406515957,65.5652204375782,-0.526881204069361));
#1227=CARTESIAN_POINT('',(77.5159486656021,65.5732902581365,-0.490241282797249));
#1228=CARTESIAN_POINT('',(77.511509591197,65.5876699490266,-0.416948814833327));
#1229=CARTESIAN_POINT('',(77.5095575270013,65.5939958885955,-0.38029972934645));
#1230=CARTESIAN_POINT('',(77.5061967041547,65.6048907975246,-0.306998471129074));
#1231=CARTESIAN_POINT('',(77.5047839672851,65.6094726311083,-0.270348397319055));
#1232=CARTESIAN_POINT('',(77.5024999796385,65.6168826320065,-0.197054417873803));
#1233=CARTESIAN_POINT('',(77.5016258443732,65.6197201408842,-0.16041154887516));
#1234=CARTESIAN_POINT('',(77.5004170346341,65.6236452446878,-0.0871408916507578));
#1235=CARTESIAN_POINT('',(77.5000806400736,65.6247384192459,-0.0505134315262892));
#1236=CARTESIAN_POINT('',(77.499944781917,65.625179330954,0.0228967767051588));
#1237=CARTESIAN_POINT('',(77.5001474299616,65.624520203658,0.0596795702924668));
#1238=CARTESIAN_POINT('',(77.501093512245,65.621446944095,0.13326274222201));
#1239=CARTESIAN_POINT('',(77.5018383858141,65.619028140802,0.17006290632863));
#1240=CARTESIAN_POINT('',(77.50386861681,65.6124396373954,0.243673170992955));
#1241=CARTESIAN_POINT('',(77.5051566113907,65.6082613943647,0.280482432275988));
#1242=CARTESIAN_POINT('',(77.5082727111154,65.5981578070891,0.354103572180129));
#1243=CARTESIAN_POINT('',(77.5101045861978,65.5922202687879,0.390913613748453));
#1244=CARTESIAN_POINT('',(77.5143080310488,65.5786016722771,0.464529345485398));
#1245=CARTESIAN_POINT('',(77.5166844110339,65.5709050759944,0.50133187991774));
#1246=CARTESIAN_POINT('',(77.5219764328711,65.5537715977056,0.574925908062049));
#1247=CARTESIAN_POINT('',(77.524897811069,65.5443162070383,0.611712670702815));
#1248=CARTESIAN_POINT('',(77.5312793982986,65.5236679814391,0.685268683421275));
#1249=CARTESIAN_POINT('',(77.5347461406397,65.5124540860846,0.722031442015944));
#1250=CARTESIAN_POINT('',(77.5422180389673,65.4882912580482,0.795533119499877));
#1251=CARTESIAN_POINT('',(77.5462303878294,65.4753191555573,0.832263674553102));
#1252=CARTESIAN_POINT('',(77.5547931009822,65.4476418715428,0.905694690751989));
#1253=CARTESIAN_POINT('',(77.5593511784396,65.4329118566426,0.942384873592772));
#1254=CARTESIAN_POINT('',(77.5690049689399,65.4017202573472,1.01572889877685));
#1255=CARTESIAN_POINT('',(77.5741087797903,65.3852326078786,1.05237056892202));
#1256=CARTESIAN_POINT('',(77.5848536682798,65.3505268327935,1.1256112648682));
#1257=CARTESIAN_POINT('',(77.5905031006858,65.3322818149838,1.16219629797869));
#1258=CARTESIAN_POINT('',(77.6023388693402,65.2940619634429,1.23531733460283));
#1259=CARTESIAN_POINT('',(77.608533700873,65.2740597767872,1.27183764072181));
#1260=CARTESIAN_POINT('',(77.6214598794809,65.2323260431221,1.34482262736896));
#1261=CARTESIAN_POINT('',(77.6281997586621,65.2105670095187,1.38127005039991));
#1262=CARTESIAN_POINT('',(77.6422156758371,65.1653191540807,1.45410279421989));
#1263=CARTESIAN_POINT('',(77.6495001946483,65.14180297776,1.4904694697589));
#1264=CARTESIAN_POINT('',(77.6628573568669,65.0986833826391,1.55472667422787));
#1265=CARTESIAN_POINT('',(77.6688603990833,65.0793045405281,1.58278292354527));
#1266=CARTESIAN_POINT('',(77.6811938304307,65.0394934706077,1.63887646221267));
#1267=CARTESIAN_POINT('',(77.6875282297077,65.0190483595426,1.66690370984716));
#1268=CARTESIAN_POINT('',(77.707208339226,64.9555357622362,1.75174922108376));
#1269=CARTESIAN_POINT('',(77.7208889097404,64.9113954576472,1.80769097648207));
#1270=CARTESIAN_POINT('',(77.7495510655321,64.8189492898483,1.91949164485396));
#1271=CARTESIAN_POINT('',(77.7645624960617,64.7705483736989,1.97526383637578));
#1272=CARTESIAN_POINT('',(77.7958925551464,64.6695721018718,2.0866995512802));
#1273=CARTESIAN_POINT('',(77.8122393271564,64.6169075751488,2.1422741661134));
#1274=CARTESIAN_POINT('',(77.8462444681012,64.5073989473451,2.25328244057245));
#1275=CARTESIAN_POINT('',(77.8639291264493,64.4504719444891,2.30862600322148));
#1276=CARTESIAN_POINT('',(77.9006138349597,64.33243122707,2.41913962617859));
#1277=CARTESIAN_POINT('',(77.919638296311,64.2712407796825,2.47421941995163));
#1278=CARTESIAN_POINT('',(77.9590062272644,64.1446694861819,2.58417205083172));
#1279=CARTESIAN_POINT('',(77.9793722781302,64.0792180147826,2.63895523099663));
#1280=CARTESIAN_POINT('',(78.0312585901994,63.9125080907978,2.77384730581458));
#1281=CARTESIAN_POINT('',(78.0631243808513,63.8101597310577,2.85247761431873));
#1282=CARTESIAN_POINT('',(78.1297403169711,63.596325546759,3.00952185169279));
#1283=CARTESIAN_POINT('',(78.1645503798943,63.4846546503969,3.08765667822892));
#1284=CARTESIAN_POINT('',(78.2370892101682,63.2521473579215,3.24358460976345));
#1285=CARTESIAN_POINT('',(78.2748719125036,63.1311490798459,3.32111034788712));
#1286=CARTESIAN_POINT('',(78.3533812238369,62.8799659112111,3.47568351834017));
#1287=CARTESIAN_POINT('',(78.3941561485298,62.7496394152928,3.55247534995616));
#1288=CARTESIAN_POINT('',(78.4786710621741,62.4797792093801,3.70544129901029));
#1289=CARTESIAN_POINT('',(78.5224543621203,62.3401212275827,3.78137153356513));
#1290=CARTESIAN_POINT('',(78.6129993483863,62.0515867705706,3.93247762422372));
#1291=CARTESIAN_POINT('',(78.659799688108,61.9026012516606,4.00742117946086));
#1292=CARTESIAN_POINT('',(78.7563934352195,61.5953770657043,4.1563902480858));
#1293=CARTESIAN_POINT('',(78.806221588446,61.4370411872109,4.23019320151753));
#1294=CARTESIAN_POINT('',(78.8563596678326,61.2778492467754,4.30182327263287));
#1295=B_SPLINE_CURVE_WITH_KNOTS('',3,(#1177,#1178,#1179,#1180,#1181,#1182,#1183,#1184,#1185,
#1186,#1187,#1188,#1189,#1190,#1191,#1192,#1193,#1194,#1195,#1196,#1197,#1198,#1199,#1200,#1201,
#1202,#1203,#1204,#1205,#1206,#1207,#1208,#1209,#1210,#1211,#1212,#1213,#1214,#1215,#1216,#1217,
#1218,#1219,#1220,#1221,#1222,#1223,#1224,#1225,#1226,#1227,#1228,#1229,#1230,#1231,#1232,#1233,
#1234,#1235,#1236,#1237,#1238,#1239,#1240,#1241,#1242,#1243,#1244,#1245,#1246,#1247,#1248,#1249,
#1250,#1251,#1252,#1253,#1254,#1255,#1256,#1257,#1258,#1259,#1260,#1261,#1262,#1263,#1264,#1265,
#1266,#1267,#1268,#1269,#1270,#1271,#1272,#1273,#1274,#1275,#1276,#1277,#1278,#1279,#1280,#1281,
#1282,#1283,#1284,#1285,#1286,#1287,#1288,#1289,#1290,#1291,#1292,#1293,#1294),.UNSPECIFIED.,
.F.,.F.,(4,2,2,2,2,2,2,2,2,2,2,2,2,2,2,2,2,2,2,2,2,2,2,2,2,2,2,2,2,2,2,2,2,2,2,2,2,2,2,2,2,2,2,
2,2,2,2,2,2,2,2,2,2,2,2,2,2,2,4),(0.,0.487578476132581,0.953105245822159,1.30979185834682,
1.91725369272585,2.39374259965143,2.8437719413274,3.26799016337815,3.53134638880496,
3.78497898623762,4.02916433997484,4.26421216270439,4.49046969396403,4.70832620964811,
4.81424693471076,4.91823526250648,5.0499464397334,5.17884391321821,5.30508141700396,
5.42882259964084,5.55024120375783,5.66952112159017,5.78685630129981,5.90245048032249,
6.01651672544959,6.12927676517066,6.24096010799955,6.35180295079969,6.46204689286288,
6.57193748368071,6.68225919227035,6.79287482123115,6.90403385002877,7.0159821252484,
7.12896034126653,7.24320268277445,7.35893566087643,7.47637716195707,7.59573571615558,
7.71720998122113,7.84098842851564,7.96724921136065,8.09616019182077,8.22787910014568,
8.33173523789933,8.43752141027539,8.65510688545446,8.88109969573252,9.11589816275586,
9.35985747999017,9.61329432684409,9.87649117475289,10.2751620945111,10.6970428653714,
11.1426969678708,11.6126023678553,12.1071667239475,12.6267396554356,13.1716226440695),.UNSPECIFIED.);
#1296=CARTESIAN_POINT('',(78.8563596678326,61.2778492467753,-4.30182327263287));
#1297=VERTEX_POINT('',#1296);
#1298=CARTESIAN_POINT('',(78.8563596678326,61.2778492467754,4.30182327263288));
#1299=VERTEX_POINT('',#1298);
#1300=EDGE_CURVE('E1377',#1297,#1299,#1295,.T.);
#1301=ORIENTED_EDGE('',*,*,#1300,.F.);
#1302=CARTESIAN_POINT('',(90.5595659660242,20.,-21.0157340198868));
#1303=CARTESIAN_POINT('',(87.6301130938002,31.2081645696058,-16.8320417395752));
#1304=CARTESIAN_POINT('',(84.9229564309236,40.8242057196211,-12.9658213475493));
#1305=CARTESIAN_POINT('',(81.7621664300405,52.0515894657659,-8.45174540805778));
#1306=CARTESIAN_POINT('',(78.8563596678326,61.2778492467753,-4.30182327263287));
#1307=B_SPLINE_CURVE_WITH_KNOTS('',2,(#1302,#1303,#1304,#1305,#1306),.UNSPECIFIED.,.F.,.F.,(3,2,
3),(0.,0.5,1.),.UNSPECIFIED.);
#1308=CARTESIAN_POINT('',(90.5595659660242,20.,-21.0157340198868));
#1309=VERTEX_POINT('',#1308);
#1310=EDGE_CURVE('E1382',#1309,#1297,#1307,.T.);
#1311=ORIENTED_EDGE('',*,*,#1310,.F.);
#1312=CARTESIAN_POINT('',(0.,20.,0.));
#1313=DIRECTION('',(0.,1.,0.));
#1314=DIRECTION('',(0.,0.,-1.));
#1315=AXIS2_PLACEMENT_3D('',#1312,#1313,#1314);
#1316=CIRCLE('',#1315,92.9661016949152);
#1317=CARTESIAN_POINT('',(90.5595659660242,20.,21.0157340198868));
#1318=VERTEX_POINT('',#1317);
#1319=EDGE_CURVE('E980',#1318,#1309,#1316,.T.);
#1320=ORIENTED_EDGE('',*,*,#1319,.F.);
#1321=CARTESIAN_POINT('',(78.8563596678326,61.2778492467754,4.30182327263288));
#1322=CARTESIAN_POINT('',(81.7620409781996,52.051987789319,8.45156624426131));
#1323=CARTESIAN_POINT('',(84.9229564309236,40.8242057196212,12.9658213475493));
#1324=CARTESIAN_POINT('',(87.629965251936,31.2087302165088,16.8318305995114));
#1325=CARTESIAN_POINT('',(90.5595659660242,20.,21.0157340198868));
#1326=B_SPLINE_CURVE_WITH_KNOTS('',2,(#1321,#1322,#1323,#1324,#1325),.UNSPECIFIED.,.F.,.F.,(3,2,
3),(0.,0.5,1.),.UNSPECIFIED.);
#1327=EDGE_CURVE('E936',#1299,#1318,#1326,.T.);
#1328=ORIENTED_EDGE('',*,*,#1327,.F.);
#1329=EDGE_LOOP('',(#1301,#1311,#1320,#1328));
#1330=FACE_BOUND('',#1329,.T.);
#1331=ADVANCED_FACE('F1018',(#1176,#1330),#1042,.T.);
#1332=CARTESIAN_POINT('',(0.,100.390423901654,0.));
#1333=DIRECTION('',(0.,1.,0.));
#1334=DIRECTION('',(0.,0.,1.));
#1335=AXIS2_PLACEMENT_3D('',#1332,#1333,#1334);
#1336=CYLINDRICAL_SURFACE('',#1335,75.);
#1337=DIRECTION('',(0.,1.,0.));
#1338=VECTOR('',#1337,1.);
#1339=CARTESIAN_POINT('',(0.,100.390423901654,75.));
#1340=LINE('',#1339,#1338);
#1341=CARTESIAN_POINT('',(0.,81.5,75.));
#1342=VERTEX_POINT('',#1341);
#1343=EDGE_CURVE('E783',#863,#1342,#1340,.T.);
#1344=ORIENTED_EDGE('',*,*,#1343,.T.);
#1345=ORIENTED_EDGE('',*,*,#1343,.F.);
#1346=CARTESIAN_POINT('',(0.,76.2976725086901,0.));
#1347=DIRECTION('',(0.,1.,0.));
#1348=DIRECTION('',(0.,0.,1.));
#1349=AXIS2_PLACEMENT_3D('',#1346,#1347,#1348);
#1350=CIRCLE('',#1349,75.);
#1351=EDGE_CURVE('E712',#863,#861,#1350,.T.);
#1352=ORIENTED_EDGE('',*,*,#1351,.T.);
#1353=DIRECTION('',(0.,1.,0.));
#1354=VECTOR('',#1353,1.);
#1355=CARTESIAN_POINT('',(0.,100.390423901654,-75.));
#1356=LINE('',#1355,#1354);
#1357=CARTESIAN_POINT('',(0.,82.,-75.));
#1358=VERTEX_POINT('',#1357);
#1359=EDGE_CURVE('E708',#861,#1358,#1356,.T.);
#1360=ORIENTED_EDGE('',*,*,#1359,.T.);
#1361=CARTESIAN_POINT('',(0.,82.,0.));
#1362=DIRECTION('',(0.,-1.,0.));
#1363=DIRECTION('',(0.,0.,1.));
#1364=AXIS2_PLACEMENT_3D('',#1361,#1362,#1363);
#1365=CIRCLE('',#1364,75.);
#1366=EDGE_CURVE('E713',#1358,#63,#1365,.T.);
#1367=ORIENTED_EDGE('',*,*,#1366,.T.);
#1368=ORIENTED_EDGE('',*,*,#64,.F.);
#1369=ORIENTED_EDGE('',*,*,#228,.T.);
#1370=ORIENTED_EDGE('',*,*,#183,.F.);
#1371=CARTESIAN_POINT('',(0.,82.,0.));
#1372=DIRECTION('',(0.,-1.,0.));
#1373=DIRECTION('',(1.04805053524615E-13,0.,1.));
#1374=AXIS2_PLACEMENT_3D('',#1371,#1372,#1373);
#1375=CIRCLE('',#1374,75.);
#1376=EDGE_CURVE('E580',#174,#1358,#1375,.T.);
#1377=ORIENTED_EDGE('',*,*,#1376,.T.);
#1378=ORIENTED_EDGE('',*,*,#1359,.F.);
#1379=ORIENTED_EDGE('',*,*,#864,.T.);
#1380=EDGE_LOOP('',(#1344,#1345,#1352,#1360,#1367,#1368,#1369,#1370,#1377,#1378,#1379));
#1381=FACE_BOUND('',#1380,.T.);
#1382=ADVANCED_FACE('F1570',(#1381),#1336,.T.);
#1383=CARTESIAN_POINT('',(0.,73.,0.));
#1384=DIRECTION('',(0.,-1.,0.));
#1385=DIRECTION('',(0.,0.,-1.));
#1386=AXIS2_PLACEMENT_3D('',#1383,#1384,#1385);
#1387=CONICAL_SURFACE('',#1386,75.,0.32682665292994);
#1388=ORIENTED_EDGE('',*,*,#1054,.F.);
#1389=ORIENTED_EDGE('',*,*,#882,.T.);
#1390=ORIENTED_EDGE('',*,*,#1173,.T.);
#1391=CARTESIAN_POINT('',(-4.30182327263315,61.2778492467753,-78.8563596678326));
#1392=CARTESIAN_POINT('',(-4.24545980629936,61.4031296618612,-78.8169004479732));
#1393=CARTESIAN_POINT('',(-4.18776122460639,61.5278813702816,-78.7776484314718));
#1394=CARTESIAN_POINT('',(-4.07175334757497,61.7712053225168,-78.7011525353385));
#1395=CARTESIAN_POINT('',(-4.01355870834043,61.8898266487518,-78.6638906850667));
#1396=CARTESIAN_POINT('',(-3.88547793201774,62.1429432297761,-78.5844300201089));
#1397=CARTESIAN_POINT('',(-3.81512547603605,62.2772269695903,-78.5423048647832));
#1398=CARTESIAN_POINT('',(-3.68727408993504,62.5120552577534,-78.4686845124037));
#1399=CARTESIAN_POINT('',(-3.63068428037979,62.6130478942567,-78.4370378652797));
#1400=CARTESIAN_POINT('',(-3.50331818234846,62.833432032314,-78.368032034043));
#1401=CARTESIAN_POINT('',(-3.43194830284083,62.9525156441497,-78.3307797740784));
#1402=CARTESIAN_POINT('',(-3.28836054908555,63.1825840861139,-78.2588710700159));
#1403=CARTESIAN_POINT('',(-3.21634672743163,63.2936837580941,-78.2241757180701));
#1404=CARTESIAN_POINT('',(-3.07156106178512,63.5077716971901,-78.1573723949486));
#1405=CARTESIAN_POINT('',(-2.99900173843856,63.6108897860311,-78.1252212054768));
#1406=CARTESIAN_POINT('',(-2.85320762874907,63.8090025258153,-78.063491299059));
#1407=CARTESIAN_POINT('',(-2.78019369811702,63.9041439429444,-78.0338648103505));
#1408=CARTESIAN_POINT('',(-2.65789387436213,64.0560741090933,-77.9865742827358));
#1409=CARTESIAN_POINT('',(-2.60997667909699,64.1138667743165,-77.9685902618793));
#1410=CARTESIAN_POINT('',(-2.51384860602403,64.2261400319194,-77.933664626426));
#1411=CARTESIAN_POINT('',(-2.46569773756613,64.2806672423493,-77.9167081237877));
#1412=CARTESIAN_POINT('',(-2.36912511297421,64.3864052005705,-77.8838379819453));
#1413=CARTESIAN_POINT('',(-2.32076378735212,64.4376660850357,-77.8679083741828));
#1414=CARTESIAN_POINT('',(-2.2237922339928,64.5368681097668,-77.8370920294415));
#1415=CARTESIAN_POINT('',(-2.17524252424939,64.5848629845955,-77.8221882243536));
#1416=CARTESIAN_POINT('',(-2.07791667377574,64.6775292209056,-77.7934230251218));
#1417=CARTESIAN_POINT('',(-2.02920067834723,64.7222579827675,-77.7795434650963));
#1418=CARTESIAN_POINT('',(-1.93156475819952,64.8083884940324,-77.752825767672));
#1419=CARTESIAN_POINT('',(-1.88270406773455,64.8498512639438,-77.7399683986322));
#1420=CARTESIAN_POINT('',(-1.78480232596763,64.9294455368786,-77.7152937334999));
#1421=CARTESIAN_POINT('',(-1.73581892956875,64.9676415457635,-77.7034562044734));
#1422=CARTESIAN_POINT('',(-1.63769340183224,65.0407010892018,-77.6808187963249));
#1423=CARTESIAN_POINT('',(-1.58860668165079,65.0756321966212,-77.6699978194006));
#1424=CARTESIAN_POINT('',(-1.50723247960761,65.1306966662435,-77.6529405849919));
#1425=CARTESIAN_POINT('',(-1.47545509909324,65.1515198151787,-77.6464903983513));
#1426=CARTESIAN_POINT('',(-1.41182386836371,65.1918053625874,-77.6340116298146));
#1427=CARTESIAN_POINT('',(-1.37998269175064,65.2112859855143,-77.6279774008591));
#1428=CARTESIAN_POINT('',(-1.31623097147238,65.24888626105,-77.6163310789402));
#1429=CARTESIAN_POINT('',(-1.28433230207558,65.2670242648,-77.6107132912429));
#1430=CARTESIAN_POINT('',(-1.22047165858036,65.3019392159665,-77.5999000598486));
#1431=CARTESIAN_POINT('',(-1.18852069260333,65.3187345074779,-77.5946989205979));
#1432=CARTESIAN_POINT('',(-1.12456189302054,65.3509640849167,-77.5847191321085));
#1433=CARTESIAN_POINT('',(-1.09256411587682,65.3664165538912,-77.5799348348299));
#1434=CARTESIAN_POINT('',(-1.02851812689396,65.3959606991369,-77.5707887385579));
#1435=CARTESIAN_POINT('',(-0.996478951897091,65.4100702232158,-77.5664213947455));
#1436=CARTESIAN_POINT('',(-0.932356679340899,65.4369288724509,-77.5581090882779));
#1437=CARTESIAN_POINT('',(-0.900281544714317,65.4496953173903,-77.5541587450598));
#1438=CARTESIAN_POINT('',(-0.836093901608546,65.4738684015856,-77.5466801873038));
#1439=CARTESIAN_POINT('',(-0.803988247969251,65.4852916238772,-77.5431468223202));
#1440=CARTESIAN_POINT('',(-0.739746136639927,65.5067790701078,-77.5365018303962));
#1441=CARTESIAN_POINT('',(-0.707615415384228,65.5168589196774,-77.5333853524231));
#1442=CARTESIAN_POINT('',(-0.643329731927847,65.5356606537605,-77.5275736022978));
#1443=CARTESIAN_POINT('',(-0.611179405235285,65.5443969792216,-77.5248738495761));
#1444=CARTESIAN_POINT('',(-0.546861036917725,65.5605129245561,-77.5198948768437));
#1445=CARTESIAN_POINT('',(-0.51469657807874,65.5679055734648,-77.5176116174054));
#1446=CARTESIAN_POINT('',(-0.450356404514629,65.5813356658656,-77.5134648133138));
#1447=CARTESIAN_POINT('',(-0.418183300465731,65.5873845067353,-77.5115977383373));
#1448=CARTESIAN_POINT('',(-0.353832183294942,65.598128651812,-77.5082823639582));
#1449=CARTESIAN_POINT('',(-0.321655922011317,65.6028335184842,-77.5068311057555));
#1450=CARTESIAN_POINT('',(-0.257304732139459,65.6108917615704,-77.5043462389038));
#1451=CARTESIAN_POINT('',(-0.225130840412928,65.6142526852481,-77.5033102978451));
#1452=CARTESIAN_POINT('',(-0.160790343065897,65.6196245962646,-77.5016550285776));
#1453=CARTESIAN_POINT('',(-0.128624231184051,65.6216409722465,-77.5010340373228));
#1454=CARTESIAN_POINT('',(-0.0643054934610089,65.6243279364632,-77.5002067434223));
#1455=CARTESIAN_POINT('',(-0.0321530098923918,65.6250016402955,-77.4999994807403));
#1456=CARTESIAN_POINT('',(0.,65.625,-77.5));
#1457=B_SPLINE_CURVE_WITH_KNOTS('',3,(#1391,#1392,#1393,#1394,#1395,#1396,#1397,#1398,#1399,
#1400,#1401,#1402,#1403,#1404,#1405,#1406,#1407,#1408,#1409,#1410,#1411,#1412,#1413,#1414,#1415,
#1416,#1417,#1418,#1419,#1420,#1421,#1422,#1423,#1424,#1425,#1426,#1427,#1428,#1429,#1430,#1431,
#1432,#1433,#1434,#1435,#1436,#1437,#1438,#1439,#1440,#1441,#1442,#1443,#1444,#1445,#1446,#1447,
#1448,#1449,#1450,#1451,#1452,#1453,#1454,#1455,#1456),.UNSPECIFIED.,.F.,.F.,(4,2,2,2,2,2,2,2,2,
2,2,2,2,2,2,2,2,2,2,2,2,2,2,2,2,2,2,2,2,2,2,2,4),(0.,0.428790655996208,0.840601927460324,
1.31255029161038,1.67255991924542,2.10371031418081,2.51422645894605,2.90449782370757,
3.27497773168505,3.50653808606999,3.73058278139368,3.947295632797,4.15687974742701,
4.35955966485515,4.55558365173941,4.74522611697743,4.92879009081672,5.0443804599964,
5.15779731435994,5.26914401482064,5.37852979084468,5.48606984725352,5.59188541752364,
5.69610375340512,5.79885804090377,5.90028723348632,6.00053579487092,6.09975334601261,
6.19809421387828,6.29571688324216,6.39278335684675,6.4894584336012,6.58590891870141),.UNSPECIFIED.);
#1458=CARTESIAN_POINT('',(-4.30182327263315,61.2778492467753,-78.8563596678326));
#1459=VERTEX_POINT('',#1458);
#1460=EDGE_CURVE('E1401',#1459,#1166,#1457,.T.);
#1461=ORIENTED_EDGE('',*,*,#1460,.F.);
#1462=CARTESIAN_POINT('',(-21.0157340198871,20.,-90.5595659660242));
#1463=CARTESIAN_POINT('',(-16.8320417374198,31.2081645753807,-87.6301130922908));
#1464=CARTESIAN_POINT('',(-12.9658213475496,40.8242057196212,-84.9229564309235));
#1465=CARTESIAN_POINT('',(-8.45174540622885,52.0515894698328,-81.7621664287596));
#1466=CARTESIAN_POINT('',(-4.30182327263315,61.2778492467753,-78.8563596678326));
#1467=B_SPLINE_CURVE_WITH_KNOTS('',2,(#1462,#1463,#1464,#1465,#1466),.UNSPECIFIED.,.F.,.F.,(3,2,
3),(0.,0.5,1.),.UNSPECIFIED.);
#1468=CARTESIAN_POINT('',(-21.0157340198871,20.,-90.5595659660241));
#1469=VERTEX_POINT('',#1468);
#1470=EDGE_CURVE('E1706',#1469,#1459,#1467,.T.);
#1471=ORIENTED_EDGE('',*,*,#1470,.F.);
#1472=CARTESIAN_POINT('',(0.,20.,0.));
#1473=DIRECTION('',(0.,1.,0.));
#1474=DIRECTION('',(0.,0.,-1.));
#1475=AXIS2_PLACEMENT_3D('',#1472,#1473,#1474);
#1476=CIRCLE('',#1475,92.9661016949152);
#1477=EDGE_CURVE('E1406',#1088,#1469,#1476,.T.);
#1478=ORIENTED_EDGE('',*,*,#1477,.F.);
#1479=ORIENTED_EDGE('',*,*,#1089,.T.);
#1480=CARTESIAN_POINT('',(0.,17.1231131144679,0.));
#1481=DIRECTION('',(0.,1.,0.));
#1482=DIRECTION('',(0.,0.,1.));
#1483=AXIS2_PLACEMENT_3D('',#1480,#1481,#1482);
#1484=CIRCLE('',#1483,93.941317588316);
#1485=EDGE_CURVE('E723',#460,#458,#1484,.T.);
#1486=ORIENTED_EDGE('',*,*,#1485,.T.);
#1487=ORIENTED_EDGE('',*,*,#1080,.F.);
#1488=CARTESIAN_POINT('',(0.,20.,0.));
#1489=DIRECTION('',(0.,1.,0.));
#1490=DIRECTION('',(0.,0.,-1.));
#1491=AXIS2_PLACEMENT_3D('',#1488,#1489,#1490);
#1492=CIRCLE('',#1491,92.9661016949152);
#1493=CARTESIAN_POINT('',(-21.0157340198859,20.,90.5595659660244));
#1494=VERTEX_POINT('',#1493);
#1495=EDGE_CURVE('E1422',#1494,#1073,#1492,.T.);
#1496=ORIENTED_EDGE('',*,*,#1495,.F.);
#1497=CARTESIAN_POINT('',(-4.30182327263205,61.2778492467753,78.8563596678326));
#1498=CARTESIAN_POINT('',(-8.45156624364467,52.0519877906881,81.7620409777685));
#1499=CARTESIAN_POINT('',(-12.9658213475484,40.8242057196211,84.9229564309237));
#1500=CARTESIAN_POINT('',(-16.8318305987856,31.2087302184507,87.6299652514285));
#1501=CARTESIAN_POINT('',(-21.0157340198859,19.9999999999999,90.5595659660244));
#1502=B_SPLINE_CURVE_WITH_KNOTS('',2,(#1497,#1498,#1499,#1500,#1501),.UNSPECIFIED.,.F.,.F.,(3,2,
3),(0.,0.5,1.),.UNSPECIFIED.);
#1503=CARTESIAN_POINT('',(-4.30182327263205,61.2778492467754,78.8563596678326));
#1504=VERTEX_POINT('',#1503);
#1505=EDGE_CURVE('E1327',#1504,#1494,#1502,.T.);
#1506=ORIENTED_EDGE('',*,*,#1505,.F.);
#1507=CARTESIAN_POINT('',(9.21797461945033E-13,65.625,77.5));
#1508=CARTESIAN_POINT('',(-0.0427781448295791,65.6250050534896,77.4999983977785));
#1509=CARTESIAN_POINT('',(-0.0855542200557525,65.6238103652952,77.5003659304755));
#1510=CARTESIAN_POINT('',(-0.171128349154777,65.6190548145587,77.5018304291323));
#1511=CARTESIAN_POINT('',(-0.213925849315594,65.615484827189,77.502930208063));
#1512=CARTESIAN_POINT('',(-0.299529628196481,65.6059799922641,77.5058602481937));
#1513=CARTESIAN_POINT('',(-0.342333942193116,65.600029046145,77.5076954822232));
#1514=CARTESIAN_POINT('',(-0.427940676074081,65.5857707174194,77.512095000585));
#1515=CARTESIAN_POINT('',(-0.470738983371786,65.5774408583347,77.514666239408));
#1516=CARTESIAN_POINT('',(-0.556323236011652,65.5584304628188,77.520536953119));
#1517=CARTESIAN_POINT('',(-0.59910231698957,65.5477217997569,77.5238451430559));
#1518=CARTESIAN_POINT('',(-0.684638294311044,65.5239592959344,77.531188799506));
#1519=CARTESIAN_POINT('',(-0.72738514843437,65.5108725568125,77.5352344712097));
#1520=CARTESIAN_POINT('',(-0.812847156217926,65.4823583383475,77.5440522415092));
#1521=CARTESIAN_POINT('',(-0.855548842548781,65.4668941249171,77.5488357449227));
#1522=CARTESIAN_POINT('',(-0.940911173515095,65.4336284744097,77.5591283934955));
#1523=CARTESIAN_POINT('',(-0.983554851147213,65.4157874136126,77.5646498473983));
#1524=CARTESIAN_POINT('',(-1.06879181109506,65.3777706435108,77.576417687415));
#1525=CARTESIAN_POINT('',(-1.11136470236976,65.3575533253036,77.5826770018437));
#1526=CARTESIAN_POINT('',(-1.19645062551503,65.3147856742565,77.5959199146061));
#1527=CARTESIAN_POINT('',(-1.23894004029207,65.2921925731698,77.6029167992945));
#1528=CARTESIAN_POINT('',(-1.32384917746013,65.2446744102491,77.6176342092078));
#1529=CARTESIAN_POINT('',(-1.3662423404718,65.2197061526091,77.6253681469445));
#1530=CARTESIAN_POINT('',(-1.45094927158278,65.1674371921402,77.6415591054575));
#1531=CARTESIAN_POINT('',(-1.49323389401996,65.1400934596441,77.650029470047));
#1532=CARTESIAN_POINT('',(-1.56790574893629,65.0896943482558,77.6656420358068));
#1533=CARTESIAN_POINT('',(-1.60051446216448,65.0669371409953,77.6726918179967));
#1534=CARTESIAN_POINT('',(-1.66570721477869,65.0200016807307,77.6872331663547));
#1535=CARTESIAN_POINT('',(-1.69827533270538,64.9958032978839,77.694731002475));
#1536=CARTESIAN_POINT('',(-1.79701892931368,64.9202466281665,77.7181457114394));
#1537=CARTESIAN_POINT('',(-1.86199108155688,64.8674473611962,77.7345128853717));
#1538=CARTESIAN_POINT('',(-1.99182643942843,64.7562382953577,77.7690013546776));
#1539=CARTESIAN_POINT('',(-2.05655166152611,64.6976827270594,77.7871685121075));
#1540=CARTESIAN_POINT('',(-2.18585237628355,64.5749452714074,77.8252668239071));
#1541=CARTESIAN_POINT('',(-2.25028695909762,64.5106286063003,77.8452406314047));
#1542=CARTESIAN_POINT('',(-2.37895393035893,64.3763587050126,77.8869586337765));
#1543=CARTESIAN_POINT('',(-2.44304435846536,64.3062821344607,77.9087420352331));
#1544=CARTESIAN_POINT('',(-2.57097384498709,64.1604815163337,77.9540860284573));
#1545=CARTESIAN_POINT('',(-2.63467191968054,64.0846452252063,77.9776824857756));
#1546=CARTESIAN_POINT('',(-2.74353611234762,63.9498607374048,78.0196337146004));
#1547=CARTESIAN_POINT('',(-2.78937189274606,63.8914021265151,78.0378329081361));
#1548=CARTESIAN_POINT('',(-2.88094688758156,63.7713612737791,78.0752132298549));
#1549=CARTESIAN_POINT('',(-2.92663020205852,63.7097403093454,78.0944067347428));
#1550=CARTESIAN_POINT('',(-3.06576589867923,63.5170644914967,78.1544443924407));
#1551=CARTESIAN_POINT('',(-3.15647711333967,63.384206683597,78.1958760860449));
#1552=CARTESIAN_POINT('',(-3.33742971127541,63.1061169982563,78.2826885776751));
#1553=CARTESIAN_POINT('',(-3.42725602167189,62.9606426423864,78.3281508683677));
#1554=CARTESIAN_POINT('',(-3.60622305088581,62.6572681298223,78.4230677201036));
#1555=CARTESIAN_POINT('',(-3.69497061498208,62.4991593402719,78.4725942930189));
#1556=CARTESIAN_POINT('',(-3.87156372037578,62.1704960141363,78.575664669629));
#1557=CARTESIAN_POINT('',(-3.95903770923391,61.9997627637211,78.6292715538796));
#1558=CARTESIAN_POINT('',(-4.13281860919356,61.6457841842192,78.7405311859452));
#1559=CARTESIAN_POINT('',(-4.21877178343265,61.4623822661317,78.7982398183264));
#1560=CARTESIAN_POINT('',(-4.30182327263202,61.2778492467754,78.8563596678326));
#1561=B_SPLINE_CURVE_WITH_KNOTS('',3,(#1507,#1508,#1509,#1510,#1511,#1512,#1513,#1514,#1515,
#1516,#1517,#1518,#1519,#1520,#1521,#1522,#1523,#1524,#1525,#1526,#1527,#1528,#1529,#1530,#1531,
#1532,#1533,#1534,#1535,#1536,#1537,#1538,#1539,#1540,#1541,#1542,#1543,#1544,#1545,#1546,#1547,
#1548,#1549,#1550,#1551,#1552,#1553,#1554,#1555,#1556,#1557,#1558,#1559,#1560),.UNSPECIFIED.,
.F.,.F.,(4,2,2,2,2,2,2,2,2,2,2,2,2,2,2,2,2,2,2,2,2,2,2,2,2,2,4),(0.,0.128312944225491,
0.25712167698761,0.386816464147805,0.5177796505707,0.65038260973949,0.784983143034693,
0.92192339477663,1.0615283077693,1.20410460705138,1.34994027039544,1.49930442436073,
1.65244759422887,1.77358307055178,1.89734978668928,2.15312017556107,2.42046499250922,
2.69997841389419,2.99218039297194,3.29752607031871,3.52694617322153,3.76414013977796,
4.26229393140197,4.79287963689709,5.35660116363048,5.95404530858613,6.58570489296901),.UNSPECIFIED.);
#1562=EDGE_CURVE('E1662',#653,#1504,#1561,.T.);
#1563=ORIENTED_EDGE('',*,*,#1562,.F.);
#1564=EDGE_LOOP('',(#1388,#1389,#1390,#1461,#1471,#1478,#1479,#1486,#1487,#1496,#1506,#1563));
#1565=FACE_BOUND('',#1564,.T.);
#1566=CARTESIAN_POINT('',(-78.8563596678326,61.2778492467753,4.30182327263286));
#1567=CARTESIAN_POINT('',(-78.8114921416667,61.4202968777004,4.23772721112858));
#1568=CARTESIAN_POINT('',(-78.7668894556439,61.5620752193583,4.17191106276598));
#1569=CARTESIAN_POINT('',(-78.6802955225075,61.8375854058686,4.03947399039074));
#1570=CARTESIAN_POINT('',(-78.6382774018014,61.9713911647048,3.97302408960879));
#1571=CARTESIAN_POINT('',(-78.5646145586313,62.2061164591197,3.85221613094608));
#1572=CARTESIAN_POINT('',(-78.5328413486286,62.3074106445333,3.79866331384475));
#1573=CARTESIAN_POINT('',(-78.4475129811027,62.5795866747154,3.65055302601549));
#1574=CARTESIAN_POINT('',(-78.394349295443,62.7493231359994,3.55363792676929));
#1575=CARTESIAN_POINT('',(-78.3008599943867,63.0481974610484,3.37334920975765));
#1576=CARTESIAN_POINT('',(-78.2602377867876,63.1781982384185,3.29156118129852));
#1577=CARTESIAN_POINT('',(-78.1823638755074,63.427648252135,3.12692594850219));
#1578=CARTESIAN_POINT('',(-78.1450502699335,63.5472825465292,3.04438976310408));
#1579=CARTESIAN_POINT('',(-78.0737751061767,63.7759811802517,2.87838442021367));
#1580=CARTESIAN_POINT('',(-78.0397440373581,63.8852582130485,2.79524027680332));
#1581=CARTESIAN_POINT('',(-77.9856975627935,64.0588895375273,2.65571834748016));
#1582=CARTESIAN_POINT('',(-77.9652607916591,64.1245654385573,2.60114614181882));
#1583=CARTESIAN_POINT('',(-77.9257418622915,64.2516134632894,2.49161328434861));
#1584=CARTESIAN_POINT('',(-77.9066375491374,64.3130549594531,2.43674136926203));
#1585=CARTESIAN_POINT('',(-77.8697842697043,64.4316271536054,2.3266427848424));
#1586=CARTESIAN_POINT('',(-77.8520113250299,64.4888331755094,2.27150545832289));
#1587=CARTESIAN_POINT('',(-77.8178206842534,64.5989289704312,2.16090813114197));
#1588=CARTESIAN_POINT('',(-77.8013771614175,64.6519001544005,2.10553741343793));
#1589=CARTESIAN_POINT('',(-77.7698448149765,64.7535190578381,1.99450765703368));
#1590=CARTESIAN_POINT('',(-77.7547283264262,64.8022543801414,1.938936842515));
#1591=CARTESIAN_POINT('',(-77.7258473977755,64.8953987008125,1.82753676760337));
#1592=CARTESIAN_POINT('',(-77.7120535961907,64.9399011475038,1.77179371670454));
#1593=CARTESIAN_POINT('',(-77.6921956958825,65.0039839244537,1.68724715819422));
#1594=CARTESIAN_POINT('',(-77.6858015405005,65.0246209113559,1.65931790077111));
#1595=CARTESIAN_POINT('',(-77.6733465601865,65.0648229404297,1.60341959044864));
#1596=CARTESIAN_POINT('',(-77.6672817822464,65.0844006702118,1.5754605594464));
#1597=CARTESIAN_POINT('',(-77.6537908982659,65.1279512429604,1.51147188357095));
#1598=CARTESIAN_POINT('',(-77.6464329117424,65.1517043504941,1.47527778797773));
#1599=CARTESIAN_POINT('',(-77.6322651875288,65.1974414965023,1.40278944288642));
#1600=CARTESIAN_POINT('',(-77.6254470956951,65.2194524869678,1.36651385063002));
#1601=CARTESIAN_POINT('',(-77.612359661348,65.2617056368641,1.29387169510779));
#1602=CARTESIAN_POINT('',(-77.6060818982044,65.2819749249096,1.25752245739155));
#1603=CARTESIAN_POINT('',(-77.5940754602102,65.3207444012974,1.18474254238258));
#1604=CARTESIAN_POINT('',(-77.5883383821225,65.3392716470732,1.14832768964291));
#1605=CARTESIAN_POINT('',(-77.5774134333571,65.3745572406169,1.07542618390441));
#1606=CARTESIAN_POINT('',(-77.5722172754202,65.3913422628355,1.03895370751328));
#1607=CARTESIAN_POINT('',(-77.5623740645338,65.4231438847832,0.965946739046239));
#1608=CARTESIAN_POINT('',(-77.5577189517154,65.4381864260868,0.929424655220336));
#1609=CARTESIAN_POINT('',(-77.5489574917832,65.4665039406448,0.856328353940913));
#1610=CARTESIAN_POINT('',(-77.5448434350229,65.4798037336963,0.819764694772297));
#1611=CARTESIAN_POINT('',(-77.53716350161,65.5046370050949,0.746595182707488));
#1612=CARTESIAN_POINT('',(-77.5335903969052,65.5161937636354,0.709998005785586));
#1613=CARTESIAN_POINT('',(-77.5269915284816,65.5375426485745,0.636771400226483));
#1614=CARTESIAN_POINT('',(-77.523959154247,65.5473560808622,0.600148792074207));
#1615=CARTESIAN_POINT('',(-77.5184406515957,65.5652204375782,0.526881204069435));
#1616=CARTESIAN_POINT('',(-77.5159486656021,65.5732902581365,0.490241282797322));
#1617=CARTESIAN_POINT('',(-77.511509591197,65.5876699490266,0.416948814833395));
#1618=CARTESIAN_POINT('',(-77.5095575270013,65.5939958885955,0.380299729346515));
#1619=CARTESIAN_POINT('',(-77.5061967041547,65.6048907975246,0.306998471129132));
#1620=CARTESIAN_POINT('',(-77.5047839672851,65.6094726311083,0.270348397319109));
#1621=CARTESIAN_POINT('',(-77.5024999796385,65.6168826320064,0.197054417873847));
#1622=CARTESIAN_POINT('',(-77.5016258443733,65.6197201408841,0.160411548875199));
#1623=CARTESIAN_POINT('',(-77.5004170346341,65.6236452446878,0.0871408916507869));
#1624=CARTESIAN_POINT('',(-77.5000806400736,65.6247384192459,0.0505134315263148));
#1625=CARTESIAN_POINT('',(-77.499944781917,65.625179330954,-0.0228967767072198));
#1626=CARTESIAN_POINT('',(-77.5001474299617,65.6245202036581,-0.0596795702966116));
#1627=CARTESIAN_POINT('',(-77.5010935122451,65.6214469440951,-0.133262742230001));
#1628=CARTESIAN_POINT('',(-77.5018383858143,65.6190281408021,-0.170062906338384));
#1629=CARTESIAN_POINT('',(-77.5038686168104,65.6124396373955,-0.243673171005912));
#1630=CARTESIAN_POINT('',(-77.5051566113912,65.6082613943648,-0.280482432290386));
#1631=CARTESIAN_POINT('',(-77.5082727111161,65.5981578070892,-0.354103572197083));
#1632=CARTESIAN_POINT('',(-77.5101045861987,65.592220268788,-0.390913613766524));
#1633=CARTESIAN_POINT('',(-77.51430803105,65.5786016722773,-0.464529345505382));
#1634=CARTESIAN_POINT('',(-77.5166844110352,65.5709050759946,-0.501331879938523));
#1635=CARTESIAN_POINT('',(-77.5219764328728,65.5537715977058,-0.574925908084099));
#1636=CARTESIAN_POINT('',(-77.5248978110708,65.5443162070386,-0.611712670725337));
#1637=CARTESIAN_POINT('',(-77.5312793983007,65.5236679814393,-0.685268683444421));
#1638=CARTESIAN_POINT('',(-77.5347461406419,65.5124540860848,-0.722031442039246));
#1639=CARTESIAN_POINT('',(-77.5422180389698,65.4882912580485,-0.795533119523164));
#1640=CARTESIAN_POINT('',(-77.546230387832,65.4753191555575,-0.832263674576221));
#1641=CARTESIAN_POINT('',(-77.554793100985,65.447641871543,-0.90569469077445));
#1642=CARTESIAN_POINT('',(-77.5593511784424,65.4329118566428,-0.942384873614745));
#1643=CARTESIAN_POINT('',(-77.5690049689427,65.4017202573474,-1.01572889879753));
#1644=CARTESIAN_POINT('',(-77.5741087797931,65.3852326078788,-1.0523705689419));
#1645=CARTESIAN_POINT('',(-77.5848536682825,65.3505268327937,-1.12561126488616));
#1646=CARTESIAN_POINT('',(-77.5905031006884,65.3322818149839,-1.16219629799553));
#1647=CARTESIAN_POINT('',(-77.6023388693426,65.2940619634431,-1.23531733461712));
#1648=CARTESIAN_POINT('',(-77.6085337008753,65.2740597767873,-1.27183764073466));
#1649=CARTESIAN_POINT('',(-77.6214598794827,65.2323260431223,-1.34482262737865));
#1650=CARTESIAN_POINT('',(-77.6281997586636,65.2105670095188,-1.38127005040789));
#1651=CARTESIAN_POINT('',(-77.6422156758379,65.1653191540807,-1.45410279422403));
#1652=CARTESIAN_POINT('',(-77.6495001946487,65.1418029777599,-1.49046946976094));
#1653=CARTESIAN_POINT('',(-77.6628573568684,65.0986833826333,-1.55472667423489));
#1654=CARTESIAN_POINT('',(-77.6688603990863,65.0793045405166,-1.58278292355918));
#1655=CARTESIAN_POINT('',(-77.6811938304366,65.0394934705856,-1.6388764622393));
#1656=CARTESIAN_POINT('',(-77.6875282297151,65.0190483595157,-1.66690370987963));
#1657=CARTESIAN_POINT('',(-77.7072083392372,64.9555357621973,-1.75174922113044));
#1658=CARTESIAN_POINT('',(-77.720888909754,64.9113954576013,-1.8076909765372));
#1659=CARTESIAN_POINT('',(-77.7495510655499,64.8189492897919,-1.91949164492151));
#1660=CARTESIAN_POINT('',(-77.7645624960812,64.7705483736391,-1.97526383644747));
#1661=CARTESIAN_POINT('',(-77.7958925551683,64.6695721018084,-2.08669955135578));
#1662=CARTESIAN_POINT('',(-77.8122393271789,64.6169075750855,-2.14227416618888));
#1663=CARTESIAN_POINT('',(-77.8462444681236,64.5073989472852,-2.25328244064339));
#1664=CARTESIAN_POINT('',(-77.8639291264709,64.4504719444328,-2.30862600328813));
#1665=CARTESIAN_POINT('',(-77.9006138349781,64.3324312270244,-2.41913962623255));
#1666=CARTESIAN_POINT('',(-77.9196382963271,64.271240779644,-2.47421941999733));
#1667=CARTESIAN_POINT('',(-77.9590062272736,64.1446694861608,-2.58417205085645));
#1668=CARTESIAN_POINT('',(-77.9793722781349,64.0792180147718,-2.63895523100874));
#1669=CARTESIAN_POINT('',(-78.0312585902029,63.91250809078,-2.77384730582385));
#1670=CARTESIAN_POINT('',(-78.0631243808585,63.8101597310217,-2.85247761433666));
#1671=CARTESIAN_POINT('',(-78.1297403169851,63.596325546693,-3.00952185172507));
#1672=CARTESIAN_POINT('',(-78.1645503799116,63.4846546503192,-3.08765667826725));
#1673=CARTESIAN_POINT('',(-78.2370892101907,63.2521473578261,-3.24358460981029));
#1674=CARTESIAN_POINT('',(-78.274871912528,63.1311490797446,-3.32111034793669));
#1675=CARTESIAN_POINT('',(-78.3533812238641,62.8799659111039,-3.475683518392));
#1676=CARTESIAN_POINT('',(-78.3941561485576,62.7496394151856,-3.55247535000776));
#1677=CARTESIAN_POINT('',(-78.4786710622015,62.4797792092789,-3.70544129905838));
#1678=CARTESIAN_POINT('',(-78.5224543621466,62.3401212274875,-3.78137153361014));
#1679=CARTESIAN_POINT('',(-78.6129993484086,62.0515867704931,-3.93247762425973));
#1680=CARTESIAN_POINT('',(-78.6597996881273,61.9026012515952,-4.00742117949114));
#1681=CARTESIAN_POINT('',(-78.7563934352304,61.5953770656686,-4.15639024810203));
#1682=CARTESIAN_POINT('',(-78.8062215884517,61.4370411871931,-4.2301932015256));
#1683=CARTESIAN_POINT('',(-78.8563596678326,61.2778492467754,-4.30182327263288));
#1684=B_SPLINE_CURVE_WITH_KNOTS('',3,(#1566,#1567,#1568,#1569,#1570,#1571,#1572,#1573,#1574,
#1575,#1576,#1577,#1578,#1579,#1580,#1581,#1582,#1583,#1584,#1585,#1586,#1587,#1588,#1589,#1590,
#1591,#1592,#1593,#1594,#1595,#1596,#1597,#1598,#1599,#1600,#1601,#1602,#1603,#1604,#1605,#1606,
#1607,#1608,#1609,#1610,#1611,#1612,#1613,#1614,#1615,#1616,#1617,#1618,#1619,#1620,#1621,#1622,
#1623,#1624,#1625,#1626,#1627,#1628,#1629,#1630,#1631,#1632,#1633,#1634,#1635,#1636,#1637,#1638,
#1639,#1640,#1641,#1642,#1643,#1644,#1645,#1646,#1647,#1648,#1649,#1650,#1651,#1652,#1653,#1654,
#1655,#1656,#1657,#1658,#1659,#1660,#1661,#1662,#1663,#1664,#1665,#1666,#1667,#1668,#1669,#1670,
#1671,#1672,#1673,#1674,#1675,#1676,#1677,#1678,#1679,#1680,#1681,#1682,#1683),.UNSPECIFIED.,
.F.,.F.,(4,2,2,2,2,2,2,2,2,2,2,2,2,2,2,2,2,2,2,2,2,2,2,2,2,2,2,2,2,2,2,2,2,2,2,2,2,2,2,2,2,2,2,
2,2,2,2,2,2,2,2,2,2,2,2,2,2,2,4),(0.,0.487578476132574,0.953105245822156,1.30979185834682,
1.91725369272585,2.39374259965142,2.8437719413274,3.26799016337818,3.53134638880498,
3.78497898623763,4.02916433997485,4.26421216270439,4.49046969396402,4.70832620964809,
4.81424693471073,4.91823526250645,5.04994643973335,5.17884391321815,5.3050814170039,
5.42882259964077,5.55024120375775,5.66952112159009,5.78685630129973,5.9024504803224,
6.0165167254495,6.12927676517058,6.24096010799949,6.35180295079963,6.46204689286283,
6.57193748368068,6.68225919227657,6.79287482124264,6.90403385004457,7.01598212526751,
7.128960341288,7.24320268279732,7.35893566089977,7.47637716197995,7.59573571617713,
7.7172099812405,7.84098842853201,7.96724921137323,8.0961601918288,8.22787910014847,
8.33173523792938,8.43752141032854,8.65510688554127,8.88109969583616,9.1158981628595,
9.35985748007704,9.61329432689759,9.87649117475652,10.2751620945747,10.6970428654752,
11.1426969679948,11.6126023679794,12.1071667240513,12.6267396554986,13.1716226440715),.UNSPECIFIED.);
#1685=CARTESIAN_POINT('',(-78.8563596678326,61.2778492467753,4.30182327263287));
#1686=VERTEX_POINT('',#1685);
#1687=CARTESIAN_POINT('',(-78.8563596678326,61.2778492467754,-4.30182327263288));
#1688=VERTEX_POINT('',#1687);
#1689=EDGE_CURVE('E1725',#1686,#1688,#1684,.T.);
#1690=ORIENTED_EDGE('',*,*,#1689,.F.);
#1691=CARTESIAN_POINT('',(-90.5595659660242,20.,21.0157340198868));
#1692=CARTESIAN_POINT('',(-87.6301130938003,31.2081645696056,16.8320417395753));
#1693=CARTESIAN_POINT('',(-84.9229564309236,40.8242057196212,12.9658213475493));
#1694=CARTESIAN_POINT('',(-81.7621664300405,52.0515894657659,8.4517454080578));
#1695=CARTESIAN_POINT('',(-78.8563596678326,61.2778492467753,4.30182327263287));
#1696=B_SPLINE_CURVE_WITH_KNOTS('',2,(#1691,#1692,#1693,#1694,#1695),.UNSPECIFIED.,.F.,.F.,(3,2,
3),(0.,0.5,1.),.UNSPECIFIED.);
#1697=CARTESIAN_POINT('',(-90.5595659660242,20.,21.0157340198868));
#1698=VERTEX_POINT('',#1697);
#1699=EDGE_CURVE('E1647',#1698,#1686,#1696,.T.);
#1700=ORIENTED_EDGE('',*,*,#1699,.F.);
#1701=CARTESIAN_POINT('',(0.,20.,0.));
#1702=DIRECTION('',(0.,1.,0.));
#1703=DIRECTION('',(0.,0.,-1.));
#1704=AXIS2_PLACEMENT_3D('',#1701,#1702,#1703);
#1705=CIRCLE('',#1704,92.9661016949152);
#1706=CARTESIAN_POINT('',(-90.5595659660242,20.,-21.0157340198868));
#1707=VERTEX_POINT('',#1706);
#1708=EDGE_CURVE('E1638',#1707,#1698,#1705,.T.);
#1709=ORIENTED_EDGE('',*,*,#1708,.F.);
#1710=CARTESIAN_POINT('',(-78.8563596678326,61.2778492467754,-4.30182327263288));
#1711=CARTESIAN_POINT('',(-81.7620409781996,52.051987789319,-8.45156624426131));
#1712=CARTESIAN_POINT('',(-84.9229564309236,40.8242057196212,-12.9658213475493));
#1713=CARTESIAN_POINT('',(-87.629965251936,31.2087302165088,-16.8318305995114));
#1714=CARTESIAN_POINT('',(-90.5595659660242,20.,-21.0157340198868));
#1715=B_SPLINE_CURVE_WITH_KNOTS('',2,(#1710,#1711,#1712,#1713,#1714),.UNSPECIFIED.,.F.,.F.,(3,2,
3),(0.,0.5,1.),.UNSPECIFIED.);
#1716=EDGE_CURVE('E905',#1688,#1707,#1715,.T.);
#1717=ORIENTED_EDGE('',*,*,#1716,.F.);
#1718=EDGE_LOOP('',(#1690,#1700,#1709,#1717));
#1719=FACE_BOUND('',#1718,.T.);
#1720=ADVANCED_FACE('F1105',(#1565,#1719),#1387,.T.);
#1721=CARTESIAN_POINT('',(0.,100.390423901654,0.));
#1722=DIRECTION('',(0.,1.,0.));
#1723=DIRECTION('',(0.,0.,1.));
#1724=AXIS2_PLACEMENT_3D('',#1721,#1722,#1723);
#1725=CYLINDRICAL_SURFACE('',#1724,95.);
#1726=ORIENTED_EDGE('',*,*,#1026,.F.);
#1727=CARTESIAN_POINT('',(0.,0.,0.));
#1728=DIRECTION('',(0.,1.,0.));
#1729=DIRECTION('',(0.,0.,1.));
#1730=AXIS2_PLACEMENT_3D('',#1727,#1728,#1729);
#1731=CIRCLE('',#1730,95.);
#1732=CARTESIAN_POINT('',(71.2836728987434,0.,-62.7983915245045));
#1733=VERTEX_POINT('',#1732);
#1734=EDGE_CURVE('E719',#1019,#1733,#1731,.T.);
#1735=ORIENTED_EDGE('',*,*,#1734,.T.);
#1736=DIRECTION('',(0.,-1.,0.));
#1737=VECTOR('',#1736,1.);
#1738=CARTESIAN_POINT('',(71.2836728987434,100.390423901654,-62.7983915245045));
#1739=LINE('',#1738,#1737);
#1740=CARTESIAN_POINT('',(71.2836728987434,7.,-62.7983915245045));
#1741=VERTEX_POINT('',#1740);
#1742=EDGE_CURVE('E955',#1741,#1733,#1739,.T.);
#1743=ORIENTED_EDGE('',*,*,#1742,.F.);
#1744=CARTESIAN_POINT('',(71.2836728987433,6.99999999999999,-62.7983915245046));
#1745=CARTESIAN_POINT('',(71.2836754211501,7.08359983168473,-62.7983883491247));
#1746=CARTESIAN_POINT('',(71.2825470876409,7.1672018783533,-62.7996694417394));
#1747=CARTESIAN_POINT('',(71.2780121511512,7.33383478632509,-62.8048167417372));
#1748=CARTESIAN_POINT('',(71.2746172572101,7.41686637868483,-62.8086696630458));
#1749=CARTESIAN_POINT('',(71.2655487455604,7.58235892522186,-62.8189589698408));
#1750=CARTESIAN_POINT('',(71.259882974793,7.66482085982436,-62.8253864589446));
#1751=CARTESIAN_POINT('',(71.2462753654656,7.82917359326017,-62.8408175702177));
#1752=CARTESIAN_POINT('',(71.2383373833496,7.91106512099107,-62.849816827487));
#1753=CARTESIAN_POINT('',(71.2201862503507,8.07427747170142,-62.8703845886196));
#1754=CARTESIAN_POINT('',(71.2099729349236,8.15559825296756,-62.881953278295));
#1755=CARTESIAN_POINT('',(71.1872714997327,8.31766993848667,-62.907651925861));
#1756=CARTESIAN_POINT('',(71.1747792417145,8.39841952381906,-62.9217865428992));
#1757=CARTESIAN_POINT('',(71.1475192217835,8.55935023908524,-62.9526086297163));
#1758=CARTESIAN_POINT('',(71.1327434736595,8.63952829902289,-62.9693050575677));
#1759=CARTESIAN_POINT('',(71.1009151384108,8.79931761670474,-63.0052414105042));
#1760=CARTESIAN_POINT('',(71.0838509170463,8.87892363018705,-63.02449432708));
#1761=CARTESIAN_POINT('',(71.0475656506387,9.0370330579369,-63.0653959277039));
#1762=CARTESIAN_POINT('',(71.0283443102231,9.11553631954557,-63.0870449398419));
#1763=CARTESIAN_POINT('',(70.9878367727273,9.27087976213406,-63.1326219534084));
#1764=CARTESIAN_POINT('',(70.9665615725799,9.34772637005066,-63.1565378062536));
#1765=CARTESIAN_POINT('',(70.9219433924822,9.49975756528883,-63.2066378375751));
#1766=CARTESIAN_POINT('',(70.8986076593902,9.57494689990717,-63.2328140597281));
#1767=CARTESIAN_POINT('',(70.8498646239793,9.7236654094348,-63.2874238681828));
#1768=CARTESIAN_POINT('',(70.8244608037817,9.79719711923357,-63.315853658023));
#1769=CARTESIAN_POINT('',(70.7715771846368,9.94260261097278,-63.374959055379));
#1770=CARTESIAN_POINT('',(70.7440971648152,10.0144762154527,-63.4056349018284));
#1771=CARTESIAN_POINT('',(70.6870561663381,10.1565685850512,-63.4692202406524));
#1772=CARTESIAN_POINT('',(70.6574914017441,10.2267840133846,-63.5021337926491));
#1773=CARTESIAN_POINT('',(70.5962744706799,10.3655622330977,-63.5701827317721));
#1774=CARTESIAN_POINT('',(70.5646151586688,10.4341181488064,-63.6053257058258));
#1775=CARTESIAN_POINT('',(70.4992043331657,10.5695848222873,-63.6778186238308));
#1776=CARTESIAN_POINT('',(70.4654425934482,10.6364848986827,-63.7151793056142));
#1777=CARTESIAN_POINT('',(70.4307481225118,10.7023274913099,-63.7535075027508));
#1778=B_SPLINE_CURVE_WITH_KNOTS('',3,(#1744,#1745,#1746,#1747,#1748,#1749,#1750,#1751,#1752,
#1753,#1754,#1755,#1756,#1757,#1758,#1759,#1760,#1761,#1762,#1763,#1764,#1765,#1766,#1767,#1768,
#1769,#1770,#1771,#1772,#1773,#1774,#1775,#1776,#1777),.UNSPECIFIED.,.F.,.F.,(4,2,2,2,2,2,2,2,2,
2,2,2,2,2,2,2,4),(0.,0.250785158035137,0.500284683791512,0.748929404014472,0.99715459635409,
1.24539774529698,1.49409624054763,1.74368507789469,1.9945946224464,2.24553856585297,
2.49520644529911,2.74402878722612,2.99244051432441,3.24087870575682,3.48978030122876,
3.7395798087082,3.99070707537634),.UNSPECIFIED.);
#1779=EDGE_CURVE('E724',#1741,#478,#1778,.T.);
#1780=ORIENTED_EDGE('',*,*,#1779,.T.);
#1781=ORIENTED_EDGE('',*,*,#479,.T.);
#1782=EDGE_LOOP('',(#1726,#1735,#1743,#1780,#1781));
#1783=FACE_BOUND('',#1782,.T.);
#1784=ADVANCED_FACE('F1094',(#1783),#1725,.T.);
#1785=CARTESIAN_POINT('',(-95.,0.,0.));
#1786=DIRECTION('',(0.,-1.,0.));
#1787=DIRECTION('',(0.,0.,-1.));
#1788=AXIS2_PLACEMENT_3D('',#1785,#1786,#1787);
#1789=PLANE('',#1788);
#1790=DIRECTION('',(0.707106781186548,0.,-0.707106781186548));
#1791=VECTOR('',#1790,1.);
#1792=CARTESIAN_POINT('',(27.5771644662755,0.,-55.8614357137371));
#1793=LINE('',#1792,#1791);
#1794=CARTESIAN_POINT('',(33.2920292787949,0.,-61.5763005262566));
#1795=VERTEX_POINT('',#1794);
#1796=CARTESIAN_POINT('',(39.5979797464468,0.,-67.8822509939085));
#1797=VERTEX_POINT('',#1796);
#1798=EDGE_CURVE('E883',#1795,#1797,#1793,.T.);
#1799=ORIENTED_EDGE('',*,*,#1798,.F.);
#1800=CARTESIAN_POINT('',(0.,0.,0.));
#1801=DIRECTION('',(0.,1.,0.));
#1802=DIRECTION('',(0.,0.,1.));
#1803=AXIS2_PLACEMENT_3D('',#1800,#1801,#1802);
#1804=CIRCLE('',#1803,70.);
#1805=EDGE_CURVE('E676',#1795,#904,#1804,.T.);
#1806=ORIENTED_EDGE('',*,*,#1805,.T.);
#1807=ORIENTED_EDGE('',*,*,#931,.T.);
#1808=CARTESIAN_POINT('',(0.,0.,0.));
#1809=DIRECTION('',(0.,1.,0.));
#1810=DIRECTION('',(0.,0.,1.));
#1811=AXIS2_PLACEMENT_3D('',#1808,#1809,#1810);
#1812=CIRCLE('',#1811,70.);
#1813=CARTESIAN_POINT('',(61.5763005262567,0.,-33.2920292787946));
#1814=VERTEX_POINT('',#1813);
#1815=EDGE_CURVE('E548',#923,#1814,#1812,.T.);
#1816=ORIENTED_EDGE('',*,*,#1815,.T.);
#1817=DIRECTION('',(-0.707106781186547,0.,0.707106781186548));
#1818=VECTOR('',#1817,1.);
#1819=CARTESIAN_POINT('',(55.8614357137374,0.,-27.5771644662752));
#1820=LINE('',#1819,#1818);
#1821=CARTESIAN_POINT('',(67.8822509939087,0.,-39.5979797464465));
#1822=VERTEX_POINT('',#1821);
#1823=EDGE_CURVE('E820',#1822,#1814,#1820,.T.);
#1824=ORIENTED_EDGE('',*,*,#1823,.F.);
#1825=CARTESIAN_POINT('',(64.3467170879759,0.,-43.1335136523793));
#1826=DIRECTION('',(0.,1.,0.));
#1827=DIRECTION('',(0.,0.,-1.));
#1828=AXIS2_PLACEMENT_3D('',#1825,#1826,#1827);
#1829=CIRCLE('',#1828,5.);
#1830=CARTESIAN_POINT('',(67.8822509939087,0.,-46.669047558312));
#1831=VERTEX_POINT('',#1830);
#1832=EDGE_CURVE('E834',#1822,#1831,#1829,.T.);
#1833=ORIENTED_EDGE('',*,*,#1832,.T.);
#1834=DIRECTION('',(0.707106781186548,0.,0.707106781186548));
#1835=VECTOR('',#1834,1.);
#1836=CARTESIAN_POINT('',(43.1335136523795,0.,-71.4177848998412));
#1837=LINE('',#1836,#1835);
#1838=CARTESIAN_POINT('',(61.5182899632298,0.,-53.033008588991));
#1839=VERTEX_POINT('',#1838);
#1840=EDGE_CURVE('E930',#1839,#1831,#1837,.T.);
#1841=ORIENTED_EDGE('',*,*,#1840,.F.);
#1842=DIRECTION('',(-0.707106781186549,0.,0.707106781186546));
#1843=VECTOR('',#1842,1.);
#1844=CARTESIAN_POINT('',(53.5579527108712,0.,-45.0726713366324));
#1845=LINE('',#1844,#1843);
#1846=EDGE_CURVE('E863',#1733,#1839,#1845,.T.);
#1847=ORIENTED_EDGE('',*,*,#1846,.F.);
#1848=ORIENTED_EDGE('',*,*,#1734,.F.);
#1849=ORIENTED_EDGE('',*,*,#1020,.F.);
#1850=ORIENTED_EDGE('',*,*,#950,.F.);
#1851=DIRECTION('',(0.707106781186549,0.,-0.707106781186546));
#1852=VECTOR('',#1851,1.);
#1853=CARTESIAN_POINT('',(45.0726713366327,0.,-53.557952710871));
#1854=LINE('',#1853,#1852);
#1855=CARTESIAN_POINT('',(53.0330085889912,0.,-61.5182899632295));
#1856=VERTEX_POINT('',#1855);
#1857=EDGE_CURVE('E700',#1856,#947,#1854,.T.);
#1858=ORIENTED_EDGE('',*,*,#1857,.F.);
#1859=DIRECTION('',(0.707106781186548,0.,0.707106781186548));
#1860=VECTOR('',#1859,1.);
#1861=CARTESIAN_POINT('',(43.1335136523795,0.,-71.4177848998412));
#1862=LINE('',#1861,#1860);
#1863=CARTESIAN_POINT('',(46.6690475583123,0.,-67.8822509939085));
#1864=VERTEX_POINT('',#1863);
#1865=EDGE_CURVE('E665',#1864,#1856,#1862,.T.);
#1866=ORIENTED_EDGE('',*,*,#1865,.F.);
#1867=CARTESIAN_POINT('',(43.1335136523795,0.,-64.3467170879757));
#1868=DIRECTION('',(0.,1.,0.));
#1869=DIRECTION('',(0.,0.,-1.));
#1870=AXIS2_PLACEMENT_3D('',#1867,#1868,#1869);
#1871=CIRCLE('',#1870,5.);
#1872=EDGE_CURVE('E637',#1864,#1797,#1871,.T.);
#1873=ORIENTED_EDGE('',*,*,#1872,.T.);
#1874=EDGE_LOOP('',(#1799,#1806,#1807,#1816,#1824,#1833,#1841,#1847,#1848,#1849,#1850,#1858,
#1866,#1873));
#1875=FACE_BOUND('',#1874,.T.);
#1876=CARTESIAN_POINT('',(71.4177848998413,0.,43.1335136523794));
#1877=DIRECTION('',(0.,-1.,0.));
#1878=DIRECTION('',(0.,0.,-1.));
#1879=AXIS2_PLACEMENT_3D('',#1876,#1877,#1878);
#1880=CIRCLE('',#1879,4.);
#1881=CARTESIAN_POINT('',(74.2462120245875,0.,40.3050865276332));
#1882=VERTEX_POINT('',#1881);
#1883=CARTESIAN_POINT('',(68.5893577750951,0.,45.9619407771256));
#1884=VERTEX_POINT('',#1883);
#1885=EDGE_CURVE('E588',#1882,#1884,#1880,.T.);
#1886=ORIENTED_EDGE('',*,*,#1885,.F.);
#1887=DIRECTION('',(0.707106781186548,0.,0.707106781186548));
#1888=VECTOR('',#1887,1.);
#1889=CARTESIAN_POINT('',(74.2462120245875,0.,40.3050865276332));
#1890=LINE('',#1889,#1888);
#1891=EDGE_CURVE('E597',#393,#1882,#1890,.T.);
#1892=ORIENTED_EDGE('',*,*,#1891,.F.);
#1893=ORIENTED_EDGE('',*,*,#394,.F.);
#1894=CARTESIAN_POINT('',(70.0035713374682,0.,41.7193000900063));
#1895=DIRECTION('',(0.,-1.,0.));
#1896=DIRECTION('',(0.,0.,-1.));
#1897=AXIS2_PLACEMENT_3D('',#1894,#1895,#1896);
#1898=CIRCLE('',#1897,4.);
#1899=CARTESIAN_POINT('',(67.175144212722,0.,44.5477272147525));
#1900=VERTEX_POINT('',#1899);
#1901=EDGE_CURVE('E694',#1900,#384,#1898,.T.);
#1902=ORIENTED_EDGE('',*,*,#1901,.F.);
#1903=DIRECTION('',(-0.707106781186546,0.,-0.707106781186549));
#1904=VECTOR('',#1903,1.);
#1905=CARTESIAN_POINT('',(68.5893577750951,0.,45.9619407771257));
#1906=LINE('',#1905,#1904);
#1907=EDGE_CURVE('E910',#1884,#1900,#1906,.T.);
#1908=ORIENTED_EDGE('',*,*,#1907,.F.);
#1909=EDGE_LOOP('',(#1886,#1892,#1893,#1902,#1908));
#1910=FACE_BOUND('',#1909,.T.);
#1911=CARTESIAN_POINT('',(-42.4264068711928,0.,-70.7106781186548));
#1912=DIRECTION('',(0.,-1.,0.));
#1913=DIRECTION('',(0.,0.,-1.));
#1914=AXIS2_PLACEMENT_3D('',#1911,#1912,#1913);
#1915=CIRCLE('',#1914,4.);
#1916=EDGE_CURVE('E843',#435,#426,#1915,.T.);
#1917=ORIENTED_EDGE('',*,*,#1916,.F.);
#1918=ORIENTED_EDGE('',*,*,#436,.F.);
#1919=EDGE_LOOP('',(#1917,#1918));
#1920=FACE_BOUND('',#1919,.T.);
#1921=CARTESIAN_POINT('',(-85.,0.,0.));
#1922=DIRECTION('',(0.,-1.,0.));
#1923=DIRECTION('',(0.,0.,1.));
#1924=AXIS2_PLACEMENT_3D('',#1921,#1922,#1923);
#1925=CIRCLE('',#1924,4.5);
#1926=EDGE_CURVE('E894',#712,#703,#1925,.T.);
#1927=ORIENTED_EDGE('',*,*,#1926,.F.);
#1928=ORIENTED_EDGE('',*,*,#713,.F.);
#1929=EDGE_LOOP('',(#1927,#1928));
#1930=FACE_BOUND('',#1929,.T.);
#1931=CARTESIAN_POINT('',(8.90327741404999E-13,0.,85.));
#1932=DIRECTION('',(0.,-1.,0.));
#1933=DIRECTION('',(1.,0.,0.));
#1934=AXIS2_PLACEMENT_3D('',#1931,#1932,#1933);
#1935=CIRCLE('',#1934,4.5);
#1936=EDGE_CURVE('E816',#754,#745,#1935,.T.);
#1937=ORIENTED_EDGE('',*,*,#1936,.F.);
#1938=ORIENTED_EDGE('',*,*,#755,.F.);
#1939=EDGE_LOOP('',(#1937,#1938));
#1940=FACE_BOUND('',#1939,.T.);
#1941=CARTESIAN_POINT('',(-2.96775913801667E-13,0.,-85.));
#1942=DIRECTION('',(0.,-1.,0.));
#1943=DIRECTION('',(-1.,0.,0.));
#1944=AXIS2_PLACEMENT_3D('',#1941,#1942,#1943);
#1945=CIRCLE('',#1944,4.5);
#1946=EDGE_CURVE('E603',#796,#787,#1945,.T.);
#1947=ORIENTED_EDGE('',*,*,#1946,.F.);
#1948=ORIENTED_EDGE('',*,*,#797,.F.);
#1949=EDGE_LOOP('',(#1947,#1948));
#1950=FACE_BOUND('',#1949,.T.);
#1951=CARTESIAN_POINT('',(85.,0.,0.));
#1952=DIRECTION('',(0.,-1.,0.));
#1953=DIRECTION('',(0.,0.,-1.));
#1954=AXIS2_PLACEMENT_3D('',#1951,#1952,#1953);
#1955=CIRCLE('',#1954,4.5);
#1956=EDGE_CURVE('E602',#838,#829,#1955,.T.);
#1957=ORIENTED_EDGE('',*,*,#1956,.F.);
#1958=ORIENTED_EDGE('',*,*,#839,.F.);
#1959=EDGE_LOOP('',(#1957,#1958));
#1960=FACE_BOUND('',#1959,.T.);
#1961=ADVANCED_FACE('F1104',(#1875,#1910,#1920,#1930,#1940,#1950,#1960),#1789,.T.);
#1962=CARTESIAN_POINT('',(0.,100.390423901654,0.));
#1963=DIRECTION('',(0.,1.,0.));
#1964=DIRECTION('',(0.,0.,1.));
#1965=AXIS2_PLACEMENT_3D('',#1962,#1963,#1964);
#1966=CYLINDRICAL_SURFACE('',#1965,70.);
#1967=ORIENTED_EDGE('',*,*,#924,.T.);
#1968=EDGE_CURVE('E531',#906,#915,#913,.T.);
#1969=ORIENTED_EDGE('',*,*,#1968,.F.);
#1970=ORIENTED_EDGE('',*,*,#907,.F.);
#1971=ORIENTED_EDGE('',*,*,#1805,.F.);
#1972=DIRECTION('',(0.,-1.,0.));
#1973=VECTOR('',#1972,1.);
#1974=CARTESIAN_POINT('',(33.2920292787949,100.390423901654,-61.5763005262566));
#1975=LINE('',#1974,#1973);
#1976=CARTESIAN_POINT('',(33.2920292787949,2.5,-61.5763005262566));
#1977=VERTEX_POINT('',#1976);
#1978=EDGE_CURVE('E802',#1977,#1795,#1975,.T.);
#1979=ORIENTED_EDGE('',*,*,#1978,.F.);
#1980=CARTESIAN_POINT('',(0.,2.5,0.));
#1981=DIRECTION('',(0.,-1.,0.));
#1982=DIRECTION('',(0.,0.,-1.));
#1983=AXIS2_PLACEMENT_3D('',#1980,#1981,#1982);
#1984=CIRCLE('',#1983,70.);
#1985=CARTESIAN_POINT('',(45.0726713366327,2.5,-53.557952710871));
#1986=VERTEX_POINT('',#1985);
#1987=EDGE_CURVE('E633',#1977,#1986,#1984,.T.);
#1988=ORIENTED_EDGE('',*,*,#1987,.T.);
#1989=DIRECTION('',(0.,-1.,0.));
#1990=VECTOR('',#1989,1.);
#1991=CARTESIAN_POINT('',(45.0726713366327,13.,-53.557952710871));
#1992=LINE('',#1991,#1990);
#1993=CARTESIAN_POINT('',(45.0726713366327,7.,-53.557952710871));
#1994=VERTEX_POINT('',#1993);
#1995=EDGE_CURVE('E867',#1994,#1986,#1992,.T.);
#1996=ORIENTED_EDGE('',*,*,#1995,.F.);
#1997=CARTESIAN_POINT('',(45.0726713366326,6.99999999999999,-53.5579527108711));
#1998=CARTESIAN_POINT('',(45.0726646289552,7.09817773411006,-53.5579576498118));
#1999=CARTESIAN_POINT('',(45.0745045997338,7.19635676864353,-53.5564098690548));
#2000=CARTESIAN_POINT('',(45.0818731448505,7.39225385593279,-53.5502078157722));
#2001=CARTESIAN_POINT('',(45.0873933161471,7.48997244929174,-53.5455606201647));
#2002=CARTESIAN_POINT('',(45.1021185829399,7.68494887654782,-53.5331578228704));
#2003=CARTESIAN_POINT('',(45.1113242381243,7.7822066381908,-53.5254017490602));
#2004=CARTESIAN_POINT('',(45.1334035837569,7.97626192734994,-53.5067854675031));
#2005=CARTESIAN_POINT('',(45.1462866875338,8.07305761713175,-53.4959172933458));
#2006=CARTESIAN_POINT('',(45.1756680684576,8.26591960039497,-53.471107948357));
#2007=CARTESIAN_POINT('',(45.1921741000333,8.3619838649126,-53.457160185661));
#2008=CARTESIAN_POINT('',(45.2287369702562,8.55272309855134,-53.4262288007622));
#2009=CARTESIAN_POINT('',(45.2487861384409,8.64740059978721,-53.4092517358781));
#2010=CARTESIAN_POINT('',(45.2924155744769,8.83536818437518,-53.3722578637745));
#2011=CARTESIAN_POINT('',(45.3159968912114,8.92865784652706,-53.3522401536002));
#2012=CARTESIAN_POINT('',(45.3666692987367,9.11385307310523,-53.3091589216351));
#2013=CARTESIAN_POINT('',(45.3937698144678,9.20575415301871,-53.286087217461));
#2014=CARTESIAN_POINT('',(45.4511406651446,9.38716166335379,-53.2371601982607));
#2015=CARTESIAN_POINT('',(45.4813909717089,9.47667916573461,-53.21132244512));
#2016=CARTESIAN_POINT('',(45.5450757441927,9.65346682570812,-53.156822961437));
#2017=CARTESIAN_POINT('',(45.5785032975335,9.7407413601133,-53.1281673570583));
#2018=CARTESIAN_POINT('',(45.6485181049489,9.91304718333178,-53.0680216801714));
#2019=CARTESIAN_POINT('',(45.6851062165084,9.99807785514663,-53.0365308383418));
#2020=CARTESIAN_POINT('',(45.761416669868,10.1659012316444,-52.9707021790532));
#2021=CARTESIAN_POINT('',(45.8011471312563,10.2486873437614,-52.9363569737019));
#2022=CARTESIAN_POINT('',(45.8837189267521,10.4120281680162,-52.864802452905));
#2023=CARTESIAN_POINT('',(45.9265749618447,10.4925694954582,-52.8275795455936));
#2024=CARTESIAN_POINT('',(46.0150315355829,10.6505840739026,-52.7505478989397));
#2025=CARTESIAN_POINT('',(46.0606257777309,10.7280637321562,-52.710745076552));
#2026=CARTESIAN_POINT('',(46.1545315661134,10.8799612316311,-52.6285389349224));
#2027=CARTESIAN_POINT('',(46.2028436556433,10.9543784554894,-52.5861350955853));
#2028=CARTESIAN_POINT('',(46.3021570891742,11.1001586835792,-52.4987108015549));
#2029=CARTESIAN_POINT('',(46.3531651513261,11.1715131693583,-52.4536837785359));
#2030=CARTESIAN_POINT('',(46.4572999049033,11.3104477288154,-52.3614753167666));
#2031=CARTESIAN_POINT('',(46.5104136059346,11.3780461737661,-52.3143068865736));
#2032=CARTESIAN_POINT('',(46.6187724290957,11.5095318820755,-52.2177681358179));
#2033=CARTESIAN_POINT('',(46.6740123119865,11.5734274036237,-52.1684031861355));
#2034=CARTESIAN_POINT('',(46.786597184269,11.6975153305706,-52.0674566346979));
#2035=CARTESIAN_POINT('',(46.8439423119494,11.7577074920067,-52.0158748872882));
#2036=CARTESIAN_POINT('',(46.9607113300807,11.8743975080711,-51.9104786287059));
#2037=CARTESIAN_POINT('',(47.0201399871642,11.9308859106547,-51.8566589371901));
#2038=CARTESIAN_POINT('',(47.1409621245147,12.0400963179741,-51.7468489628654));
#2039=CARTESIAN_POINT('',(47.2023615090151,12.0928051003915,-51.690852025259));
#2040=CARTESIAN_POINT('',(47.3266386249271,12.1939518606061,-51.5770913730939));
#2041=CARTESIAN_POINT('',(47.3895123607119,12.2423999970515,-51.5193323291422));
#2042=CARTESIAN_POINT('',(47.5167156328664,12.3350349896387,-51.402035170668));
#2043=CARTESIAN_POINT('',(47.5810451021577,12.3792220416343,-51.3424971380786));
#2044=CARTESIAN_POINT('',(47.7111374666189,12.4633452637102,-51.221628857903));
#2045=CARTESIAN_POINT('',(47.7769033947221,12.5032711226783,-51.1602947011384));
#2046=CARTESIAN_POINT('',(47.90953745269,12.578704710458,-51.0361095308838));
#2047=CARTESIAN_POINT('',(47.9764056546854,12.6142121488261,-50.9732584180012));
#2048=CARTESIAN_POINT('',(48.1109131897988,12.6805878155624,-50.8463229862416));
#2049=CARTESIAN_POINT('',(48.1785502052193,12.7114673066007,-50.7822421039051));
#2050=CARTESIAN_POINT('',(48.3145795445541,12.7685978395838,-50.6528401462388));
#2051=CARTESIAN_POINT('',(48.3829718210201,12.7948491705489,-50.5875191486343));
#2052=CARTESIAN_POINT('',(48.5204964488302,12.8427347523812,-50.4556292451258));
#2053=CARTESIAN_POINT('',(48.5896301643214,12.8643579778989,-50.3890577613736));
#2054=CARTESIAN_POINT('',(48.7285861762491,12.9029869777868,-50.254693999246));
#2055=CARTESIAN_POINT('',(48.7984101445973,12.91997300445,-50.1868977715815));
#2056=CARTESIAN_POINT('',(48.9381169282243,12.9490771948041,-50.0506763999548));
#2057=CARTESIAN_POINT('',(49.0079991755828,12.9612072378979,-49.9822532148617));
#2058=CARTESIAN_POINT('',(49.1478152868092,12.9806085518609,-49.8447776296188));
#2059=CARTESIAN_POINT('',(49.2177491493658,12.9878799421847,-49.7757252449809));
#2060=CARTESIAN_POINT('',(49.357663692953,12.9975857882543,-49.63699015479));
#2061=CARTESIAN_POINT('',(49.4276440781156,13.0000085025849,-49.567306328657));
#2062=CARTESIAN_POINT('',(49.4974746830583,12.9999999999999,-49.4974746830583));
#2063=B_SPLINE_CURVE_WITH_KNOTS('',3,(#1997,#1998,#1999,#2000,#2001,#2002,#2003,#2004,#2005,
#2006,#2007,#2008,#2009,#2010,#2011,#2012,#2013,#2014,#2015,#2016,#2017,#2018,#2019,#2020,#2021,
#2022,#2023,#2024,#2025,#2026,#2027,#2028,#2029,#2030,#2031,#2032,#2033,#2034,#2035,#2036,#2037,
#2038,#2039,#2040,#2041,#2042,#2043,#2044,#2045,#2046,#2047,#2048,#2049,#2050,#2051,#2052,#2053,
#2054,#2055,#2056,#2057,#2058,#2059,#2060,#2061,#2062),.UNSPECIFIED.,.F.,.F.,(4,2,2,2,2,2,2,2,2,
2,2,2,2,2,2,2,2,2,2,2,2,2,2,2,2,2,2,2,2,2,2,2,4),(0.,0.29450532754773,0.588340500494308,
0.882220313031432,1.17685923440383,1.47213505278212,1.76677929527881,2.06151120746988,
2.35704939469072,2.65081149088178,2.94394848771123,3.23716526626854,3.53116613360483,
3.82665217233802,4.12148298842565,4.41637295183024,4.71203600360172,5.00609556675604,
5.29947186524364,5.59286746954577,5.8869848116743,6.18208538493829,6.47646211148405,
6.77082530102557,7.06588536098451,7.36096480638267,7.65531405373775,7.9496449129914,
8.24466932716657,8.54093118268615,8.83646378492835,9.13198912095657,9.42822923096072),.UNSPECIFIED.);
#2064=CARTESIAN_POINT('',(49.4974746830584,13.,-49.4974746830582));
#2065=VERTEX_POINT('',#2064);
#2066=EDGE_CURVE('E638',#1994,#2065,#2063,.T.);
#2067=ORIENTED_EDGE('',*,*,#2066,.T.);
#2068=CARTESIAN_POINT('',(49.4974746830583,12.9999999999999,-49.4974746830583));
#2069=CARTESIAN_POINT('',(49.5669056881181,13.0000082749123,-49.4280446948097));
#2070=CARTESIAN_POINT('',(49.6361905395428,12.9976127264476,-49.358466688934));
#2071=CARTESIAN_POINT('',(49.7741396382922,12.9880162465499,-49.2193515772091));
#2072=CARTESIAN_POINT('',(49.8428049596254,12.9808265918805,-49.1498147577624));
#2073=CARTESIAN_POINT('',(49.9795182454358,12.9616436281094,-49.0107872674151));
#2074=CARTESIAN_POINT('',(50.0475661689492,12.9496500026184,-48.9412965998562));
#2075=CARTESIAN_POINT('',(50.1830487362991,12.9208737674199,-48.8023673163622));
#2076=CARTESIAN_POINT('',(50.2504814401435,12.9040793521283,-48.7329292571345));
#2077=CARTESIAN_POINT('',(50.3845820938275,12.8657558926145,-48.5942713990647));
#2078=CARTESIAN_POINT('',(50.4512476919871,12.844215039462,-48.5250525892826));
#2079=CARTESIAN_POINT('',(50.5833312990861,12.7964792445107,-48.3873503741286));
#2080=CARTESIAN_POINT('',(50.6487517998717,12.7702949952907,-48.3188656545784));
#2081=CARTESIAN_POINT('',(50.7783582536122,12.7132840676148,-48.1826438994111));
#2082=CARTESIAN_POINT('',(50.8425440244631,12.682456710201,-48.1149069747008));
#2083=CARTESIAN_POINT('',(50.9696949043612,12.6161714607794,-47.980191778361));
#2084=CARTESIAN_POINT('',(51.0326564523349,12.5807018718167,-47.9132159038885));
#2085=CARTESIAN_POINT('',(51.1567182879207,12.5055380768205,-47.7807321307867));
#2086=CARTESIAN_POINT('',(51.217826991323,12.465868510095,-47.7152181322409));
#2087=CARTESIAN_POINT('',(51.3382672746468,12.382285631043,-47.5856083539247));
#2088=CARTESIAN_POINT('',(51.3976025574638,12.3383821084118,-47.5215097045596));
#2089=CARTESIAN_POINT('',(51.514516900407,12.2463424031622,-47.3947463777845));
#2090=CARTESIAN_POINT('',(51.5720957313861,12.198205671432,-47.3320818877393));
#2091=CARTESIAN_POINT('',(51.6855184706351,12.0977102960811,-47.2082011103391));
#2092=CARTESIAN_POINT('',(51.7413576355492,12.0453413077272,-47.1469888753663));
#2093=CARTESIAN_POINT('',(51.8513552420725,11.936356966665,-47.0259894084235));
#2094=CARTESIAN_POINT('',(51.9055028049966,11.8797199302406,-46.9662118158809));
#2095=CARTESIAN_POINT('',(52.0115411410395,11.7626836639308,-46.8487548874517));
#2096=CARTESIAN_POINT('',(52.0634369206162,11.7022935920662,-46.7910709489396));
#2097=CARTESIAN_POINT('',(52.16499836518,11.5777613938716,-46.6778184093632));
#2098=CARTESIAN_POINT('',(52.2146638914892,11.5136190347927,-46.6222499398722));
#2099=CARTESIAN_POINT('',(52.3117916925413,11.3815923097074,-46.513243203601));
#2100=CARTESIAN_POINT('',(52.3592481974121,11.3136990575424,-46.459810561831));
#2101=CARTESIAN_POINT('',(52.4515234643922,11.1748677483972,-46.3556091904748));
#2102=CARTESIAN_POINT('',(52.4963543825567,11.103946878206,-46.3048283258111));
#2103=CARTESIAN_POINT('',(52.5834217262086,10.9590472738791,-46.2059313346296));
#2104=CARTESIAN_POINT('',(52.625664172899,10.8850763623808,-46.1578090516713));
#2105=CARTESIAN_POINT('',(52.7075828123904,10.734085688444,-46.064244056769));
#2106=CARTESIAN_POINT('',(52.7472590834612,10.6570660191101,-46.0188012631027));
#2107=CARTESIAN_POINT('',(52.8240730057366,10.4999860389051,-45.9306078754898));
#2108=CARTESIAN_POINT('',(52.8612044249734,10.4199189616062,-45.8878639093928));
#2109=CARTESIAN_POINT('',(52.932912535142,10.2568422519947,-45.8051282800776));
#2110=CARTESIAN_POINT('',(52.9674796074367,10.1738231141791,-45.7651470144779));
#2111=CARTESIAN_POINT('',(53.0337347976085,10.0054950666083,-45.6883523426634));
#2112=CARTESIAN_POINT('',(53.0654299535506,9.9201924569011,-45.6515312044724));
#2113=CARTESIAN_POINT('',(53.1259679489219,9.74730479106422,-45.5810671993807));
#2114=CARTESIAN_POINT('',(53.1548110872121,9.65971997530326,-45.5474239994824));
#2115=CARTESIAN_POINT('',(53.2096706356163,9.48227438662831,-45.4833237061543));
#2116=CARTESIAN_POINT('',(53.2356803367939,9.39240880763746,-45.4528741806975));
#2117=CARTESIAN_POINT('',(53.2847822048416,9.21081998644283,-45.3953016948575));
#2118=CARTESIAN_POINT('',(53.3078739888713,9.11909650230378,-45.3681791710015));
#2119=CARTESIAN_POINT('',(53.3510084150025,8.93423169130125,-45.31744705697));
#2120=CARTESIAN_POINT('',(53.3710584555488,8.84109443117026,-45.293828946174));
#2121=CARTESIAN_POINT('',(53.4081307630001,8.65340746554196,-45.2501092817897));
#2122=CARTESIAN_POINT('',(53.4251531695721,8.55885782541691,-45.2300075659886));
#2123=CARTESIAN_POINT('',(53.456190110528,8.36835041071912,-45.1933216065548));
#2124=CARTESIAN_POINT('',(53.4701973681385,8.27238981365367,-45.1767458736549));
#2125=CARTESIAN_POINT('',(53.4952100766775,8.07912608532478,-45.1471247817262));
#2126=CARTESIAN_POINT('',(53.506202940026,7.98181905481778,-45.1340942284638));
#2127=CARTESIAN_POINT('',(53.5250321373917,7.78671629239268,-45.111762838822));
#2128=CARTESIAN_POINT('',(53.5328761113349,7.68892233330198,-45.102452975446));
#2129=CARTESIAN_POINT('',(53.5454200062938,7.49284915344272,-45.0875603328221));
#2130=CARTESIAN_POINT('',(53.5501198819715,7.39456992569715,-45.0819776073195));
#2131=CARTESIAN_POINT('',(53.5563926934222,7.1975270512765,-45.0745250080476));
#2132=CARTESIAN_POINT('',(53.5579578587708,7.09876280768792,-45.0726643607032));
#2133=CARTESIAN_POINT('',(53.5579527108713,6.99999999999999,-45.0726713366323));
#2134=B_SPLINE_CURVE_WITH_KNOTS('',3,(#2068,#2069,#2070,#2071,#2072,#2073,#2074,#2075,#2076,
#2077,#2078,#2079,#2080,#2081,#2082,#2083,#2084,#2085,#2086,#2087,#2088,#2089,#2090,#2091,#2092,
#2093,#2094,#2095,#2096,#2097,#2098,#2099,#2100,#2101,#2102,#2103,#2104,#2105,#2106,#2107,#2108,
#2109,#2110,#2111,#2112,#2113,#2114,#2115,#2116,#2117,#2118,#2119,#2120,#2121,#2122,#2123,#2124,
#2125,#2126,#2127,#2128,#2129,#2130,#2131,#2132,#2133),.UNSPECIFIED.,.F.,.F.,(4,2,2,2,2,2,2,2,2,
2,2,2,2,2,2,2,2,2,2,2,2,2,2,2,2,2,2,2,2,2,2,2,4),(0.,0.294540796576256,0.588391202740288,
0.882260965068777,1.17685969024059,1.47219981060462,1.7668684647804,2.06158025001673,
2.35704945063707,2.65087239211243,2.9440315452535,3.23722878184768,3.53116570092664,
3.82671229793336,4.12156406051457,4.41643413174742,4.71203552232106,5.00613786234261,
5.2995278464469,5.59290887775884,5.88698442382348,6.18211242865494,6.47649642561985,
6.77084954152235,7.06588512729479,7.3609593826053,7.65530400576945,7.94963504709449,
8.24466865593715,8.54091613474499,8.83644044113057,9.13196900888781,9.42822924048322),.UNSPECIFIED.);
#2135=CARTESIAN_POINT('',(53.5579527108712,7.,-45.0726713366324));
#2136=VERTEX_POINT('',#2135);
#2137=EDGE_CURVE('E1507',#2065,#2136,#2134,.T.);
#2138=ORIENTED_EDGE('',*,*,#2137,.T.);
#2139=DIRECTION('',(0.,-1.,0.));
#2140=VECTOR('',#2139,1.);
#2141=CARTESIAN_POINT('',(53.5579527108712,13.,-45.0726713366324));
#2142=LINE('',#2141,#2140);
#2143=CARTESIAN_POINT('',(53.5579527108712,2.5,-45.0726713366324));
#2144=VERTEX_POINT('',#2143);
#2145=EDGE_CURVE('E559',#2136,#2144,#2142,.T.);
#2146=ORIENTED_EDGE('',*,*,#2145,.T.);
#2147=CARTESIAN_POINT('',(0.,2.5,0.));
#2148=DIRECTION('',(0.,-1.,0.));
#2149=DIRECTION('',(0.,0.,-1.));
#2150=AXIS2_PLACEMENT_3D('',#2147,#2148,#2149);
#2151=CIRCLE('',#2150,70.);
#2152=CARTESIAN_POINT('',(61.5763005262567,2.5,-33.2920292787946));
#2153=VERTEX_POINT('',#2152);
#2154=EDGE_CURVE('E550',#2144,#2153,#2151,.T.);
#2155=ORIENTED_EDGE('',*,*,#2154,.T.);
#2156=DIRECTION('',(0.,1.,0.));
#2157=VECTOR('',#2156,1.);
#2158=CARTESIAN_POINT('',(61.5763005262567,100.390423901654,-33.2920292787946));
#2159=LINE('',#2158,#2157);
#2160=EDGE_CURVE('E817',#1814,#2153,#2159,.T.);
#2161=ORIENTED_EDGE('',*,*,#2160,.F.);
#2162=ORIENTED_EDGE('',*,*,#1815,.F.);
#2163=EDGE_LOOP('',(#1967,#1969,#1970,#1971,#1979,#1988,#1996,#2067,#2138,#2146,#2155,#2161,#2162));
#2164=FACE_BOUND('',#2163,.T.);
#2165=ADVANCED_FACE('F545',(#2164),#1966,.F.);
#2166=CARTESIAN_POINT('',(-71.5,81.,0.));
#2167=DIRECTION('',(0.,1.,0.));
#2168=DIRECTION('',(1.,0.,0.));
#2169=AXIS2_PLACEMENT_3D('',#2166,#2167,#2168);
#2170=PLANE('',#2169);
#2171=ORIENTED_EDGE('',*,*,#148,.T.);
#2172=ORIENTED_EDGE('',*,*,#107,.T.);
#2173=EDGE_LOOP('',(#2171,#2172));
#2174=FACE_BOUND('',#2173,.T.);
#2175=ADVANCED_FACE('F1490',(#2174),#2170,.T.);
#2176=CARTESIAN_POINT('',(45.0726713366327,13.,-53.557952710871));
#2177=DIRECTION('',(-0.707106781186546,0.,-0.707106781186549));
#2178=DIRECTION('',(-0.707106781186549,0.,0.707106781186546));
#2179=AXIS2_PLACEMENT_3D('',#2176,#2177,#2178);
#2180=PLANE('',#2179);
#2181=DIRECTION('',(-0.707106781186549,0.,0.707106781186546));
#2182=VECTOR('',#2181,1.);
#2183=CARTESIAN_POINT('',(45.0726713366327,2.5,-53.557952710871));
#2184=LINE('',#2183,#2182);
#2185=CARTESIAN_POINT('',(53.0330085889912,2.5,-61.5182899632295));
#2186=VERTEX_POINT('',#2185);
#2187=EDGE_CURVE('E862',#2186,#1986,#2184,.T.);
#2188=ORIENTED_EDGE('',*,*,#2187,.F.);
#2189=DIRECTION('',(0.,-1.,0.));
#2190=VECTOR('',#2189,1.);
#2191=CARTESIAN_POINT('',(53.0330085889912,13.,-61.5182899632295));
#2192=LINE('',#2191,#2190);
#2193=EDGE_CURVE('E704',#2186,#1856,#2192,.T.);
#2194=ORIENTED_EDGE('',*,*,#2193,.T.);
#2195=ORIENTED_EDGE('',*,*,#1857,.T.);
#2196=ORIENTED_EDGE('',*,*,#1002,.T.);
#2197=DIRECTION('',(-0.707106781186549,0.,0.707106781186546));
#2198=VECTOR('',#2197,1.);
#2199=CARTESIAN_POINT('',(45.0726713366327,7.,-53.557952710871));
#2200=LINE('',#2199,#2198);
#2201=EDGE_CURVE('E1077',#995,#1994,#2200,.T.);
#2202=ORIENTED_EDGE('',*,*,#2201,.T.);
#2203=ORIENTED_EDGE('',*,*,#1995,.T.);
#2204=EDGE_LOOP('',(#2188,#2194,#2195,#2196,#2202,#2203));
#2205=FACE_BOUND('',#2204,.T.);
#2206=ADVANCED_FACE('F1290',(#2205),#2180,.F.);
#2207=CARTESIAN_POINT('',(53.5579527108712,13.,-45.0726713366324));
#2208=DIRECTION('',(0.707106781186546,0.,0.707106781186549));
#2209=DIRECTION('',(0.,-1.,0.));
#2210=AXIS2_PLACEMENT_3D('',#2207,#2208,#2209);
#2211=PLANE('',#2210);
#2212=ORIENTED_EDGE('',*,*,#1846,.T.);
#2213=DIRECTION('',(0.,1.,0.));
#2214=VECTOR('',#2213,1.);
#2215=CARTESIAN_POINT('',(61.5182899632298,13.,-53.033008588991));
#2216=LINE('',#2215,#2214);
#2217=CARTESIAN_POINT('',(61.5182899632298,2.5,-53.033008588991));
#2218=VERTEX_POINT('',#2217);
#2219=EDGE_CURVE('E868',#1839,#2218,#2216,.T.);
#2220=ORIENTED_EDGE('',*,*,#2219,.T.);
#2221=DIRECTION('',(0.707106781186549,0.,-0.707106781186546));
#2222=VECTOR('',#2221,1.);
#2223=CARTESIAN_POINT('',(53.5579527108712,2.5,-45.0726713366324));
#2224=LINE('',#2223,#2222);
#2225=EDGE_CURVE('E775',#2144,#2218,#2224,.T.);
#2226=ORIENTED_EDGE('',*,*,#2225,.F.);
#2227=ORIENTED_EDGE('',*,*,#2145,.F.);
#2228=DIRECTION('',(0.707106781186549,0.,-0.707106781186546));
#2229=VECTOR('',#2228,1.);
#2230=CARTESIAN_POINT('',(53.5579527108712,7.,-45.0726713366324));
#2231=LINE('',#2230,#2229);
#2232=EDGE_CURVE('E879',#2136,#1741,#2231,.T.);
#2233=ORIENTED_EDGE('',*,*,#2232,.T.);
#2234=ORIENTED_EDGE('',*,*,#1742,.T.);
#2235=EDGE_LOOP('',(#2212,#2220,#2226,#2227,#2233,#2234));
#2236=FACE_BOUND('',#2235,.T.);
#2237=ADVANCED_FACE('F1493',(#2236),#2211,.F.);
#2238=CARTESIAN_POINT('',(0.,76.2976725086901,0.));
#2239=DIRECTION('',(0.,1.,0.));
#2240=DIRECTION('',(0.,0.,1.));
#2241=AXIS2_PLACEMENT_3D('',#2238,#2239,#2240);
#2242=TOROIDAL_SURFACE('',#2241,95.,20.);
#2243=ORIENTED_EDGE('',*,*,#873,.F.);
#2244=ORIENTED_EDGE('',*,*,#1351,.F.);
#2245=ORIENTED_EDGE('',*,*,#889,.T.);
#2246=ORIENTED_EDGE('',*,*,#1048,.F.);
#2247=EDGE_LOOP('',(#2243,#2244,#2245,#2246));
#2248=FACE_BOUND('',#2247,.T.);
#2249=ADVANCED_FACE('F1560',(#2248),#2242,.F.);
#2250=CARTESIAN_POINT('',(0.,82.,-75.));
#2251=DIRECTION('',(0.,1.,0.));
#2252=DIRECTION('',(1.,0.,0.));
#2253=AXIS2_PLACEMENT_3D('',#2250,#2251,#2252);
#2254=PLANE('',#2253);
#2255=ORIENTED_EDGE('',*,*,#175,.T.);
#2256=ORIENTED_EDGE('',*,*,#73,.T.);
#2257=ORIENTED_EDGE('',*,*,#1366,.F.);
#2258=ORIENTED_EDGE('',*,*,#1376,.F.);
#2259=EDGE_LOOP('',(#2255,#2256,#2257,#2258));
#2260=FACE_BOUND('',#2259,.T.);
#2261=ADVANCED_FACE('F1367',(#2260),#2254,.T.);
#2262=CARTESIAN_POINT('',(85.,85.,0.));
#2263=DIRECTION('',(0.,-1.,0.));
#2264=DIRECTION('',(0.,0.,-1.));
#2265=AXIS2_PLACEMENT_3D('',#2262,#2263,#2264);
#2266=CYLINDRICAL_SURFACE('',#2265,4.5);
#2267=ORIENTED_EDGE('',*,*,#830,.F.);
#2268=CARTESIAN_POINT('',(85.,20.,0.));
#2269=DIRECTION('',(0.,1.,0.));
#2270=DIRECTION('',(0.,0.,-1.));
#2271=AXIS2_PLACEMENT_3D('',#2268,#2269,#2270);
#2272=CIRCLE('',#2271,4.5);
#2273=EDGE_CURVE('E572',#821,#819,#2272,.T.);
#2274=ORIENTED_EDGE('',*,*,#2273,.T.);
#2275=ORIENTED_EDGE('',*,*,#845,.T.);
#2276=ORIENTED_EDGE('',*,*,#1956,.T.);
#2277=EDGE_LOOP('',(#2267,#2274,#2275,#2276));
#2278=FACE_BOUND('',#2277,.T.);
#2279=ADVANCED_FACE('F1351',(#2278),#2266,.F.);
#2280=CARTESIAN_POINT('',(85.,20.,0.));
#2281=DIRECTION('',(0.,-1.,0.));
#2282=DIRECTION('',(0.,0.,-1.));
#2283=AXIS2_PLACEMENT_3D('',#2280,#2281,#2282);
#2284=PLANE('',#2283);
#2285=ORIENTED_EDGE('',*,*,#1319,.T.);
#2286=DIRECTION('',(0.57357643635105,0.,-0.819152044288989));
#2287=VECTOR('',#2286,1.);
#2288=CARTESIAN_POINT('',(78.8563596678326,20.,-4.30182327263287));
#2289=LINE('',#2288,#2287);
#2290=CARTESIAN_POINT('',(78.8563596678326,20.,-4.30182327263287));
#2291=VERTEX_POINT('',#2290);
#2292=EDGE_CURVE('E654',#2291,#1309,#2289,.T.);
#2293=ORIENTED_EDGE('',*,*,#2292,.F.);
#2294=CARTESIAN_POINT('',(85.,20.,0.));
#2295=DIRECTION('',(0.,-1.,0.));
#2296=DIRECTION('',(0.,0.,-1.));
#2297=AXIS2_PLACEMENT_3D('',#2294,#2295,#2296);
#2298=CIRCLE('',#2297,7.5);
#2299=CARTESIAN_POINT('',(78.8563596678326,20.,4.30182327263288));
#2300=VERTEX_POINT('',#2299);
#2301=EDGE_CURVE('E931',#2300,#2291,#2298,.T.);
#2302=ORIENTED_EDGE('',*,*,#2301,.F.);
#2303=DIRECTION('',(-0.573576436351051,0.,-0.819152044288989));
#2304=VECTOR('',#2303,1.);
#2305=CARTESIAN_POINT('',(78.8563596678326,20.,4.30182327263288));
#2306=LINE('',#2305,#2304);
#2307=EDGE_CURVE('E1374',#1318,#2300,#2306,.T.);
#2308=ORIENTED_EDGE('',*,*,#2307,.F.);
#2309=EDGE_LOOP('',(#2285,#2293,#2302,#2308));
#2310=FACE_BOUND('',#2309,.T.);
#2311=ORIENTED_EDGE('',*,*,#822,.F.);
#2312=ORIENTED_EDGE('',*,*,#2273,.F.);
#2313=EDGE_LOOP('',(#2311,#2312));
#2314=FACE_BOUND('',#2313,.T.);
#2315=ADVANCED_FACE('F1172',(#2310,#2314),#2284,.F.);
#2316=CARTESIAN_POINT('',(85.,85.,0.));
#2317=DIRECTION('',(0.,-1.,0.));
#2318=DIRECTION('',(0.,0.,-1.));
#2319=AXIS2_PLACEMENT_3D('',#2316,#2317,#2318);
#2320=CYLINDRICAL_SURFACE('',#2319,7.5);
#2321=ORIENTED_EDGE('',*,*,#1300,.T.);
#2322=DIRECTION('',(0.,-1.,0.));
#2323=VECTOR('',#2322,1.);
#2324=CARTESIAN_POINT('',(78.8563596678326,85.,4.30182327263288));
#2325=LINE('',#2324,#2323);
#2326=EDGE_CURVE('E935',#1299,#2300,#2325,.T.);
#2327=ORIENTED_EDGE('',*,*,#2326,.T.);
#2328=ORIENTED_EDGE('',*,*,#2301,.T.);
#2329=DIRECTION('',(0.,-1.,0.));
#2330=VECTOR('',#2329,1.);
#2331=CARTESIAN_POINT('',(78.8563596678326,85.,-4.30182327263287));
#2332=LINE('',#2331,#2330);
#2333=EDGE_CURVE('E1386',#1297,#2291,#2332,.T.);
#2334=ORIENTED_EDGE('',*,*,#2333,.F.);
#2335=EDGE_LOOP('',(#2321,#2327,#2328,#2334));
#2336=FACE_BOUND('',#2335,.T.);
#2337=ADVANCED_FACE('F1357',(#2336),#2320,.F.);
#2338=CARTESIAN_POINT('',(78.8563596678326,85.,4.30182327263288));
#2339=DIRECTION('',(-0.819152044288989,0.,0.573576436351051));
#2340=DIRECTION('',(0.,1.,0.));
#2341=AXIS2_PLACEMENT_3D('',#2338,#2339,#2340);
#2342=PLANE('',#2341);
#2343=ORIENTED_EDGE('',*,*,#1327,.T.);
#2344=ORIENTED_EDGE('',*,*,#2307,.T.);
#2345=ORIENTED_EDGE('',*,*,#2326,.F.);
#2346=EDGE_LOOP('',(#2343,#2344,#2345));
#2347=FACE_BOUND('',#2346,.T.);
#2348=ADVANCED_FACE('F1364',(#2347),#2342,.F.);
#2349=CARTESIAN_POINT('',(78.8563596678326,85.,-4.30182327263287));
#2350=DIRECTION('',(-0.819152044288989,0.,-0.57357643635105));
#2351=DIRECTION('',(-0.57357643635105,0.,0.819152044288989));
#2352=AXIS2_PLACEMENT_3D('',#2349,#2350,#2351);
#2353=PLANE('',#2352);
#2354=ORIENTED_EDGE('',*,*,#1310,.T.);
#2355=ORIENTED_EDGE('',*,*,#2333,.T.);
#2356=ORIENTED_EDGE('',*,*,#2292,.T.);
#2357=EDGE_LOOP('',(#2354,#2355,#2356));
#2358=FACE_BOUND('',#2357,.T.);
#2359=ADVANCED_FACE('F1381',(#2358),#2353,.F.);
#2360=CARTESIAN_POINT('',(-2.96775913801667E-13,85.,-85.));
#2361=DIRECTION('',(0.,-1.,0.));
#2362=DIRECTION('',(0.,0.,-1.));
#2363=AXIS2_PLACEMENT_3D('',#2360,#2361,#2362);
#2364=CYLINDRICAL_SURFACE('',#2363,4.5);
#2365=ORIENTED_EDGE('',*,*,#788,.F.);
#2366=CARTESIAN_POINT('',(-2.96775913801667E-13,20.,-85.));
#2367=DIRECTION('',(0.,1.,0.));
#2368=DIRECTION('',(0.,0.,-1.));
#2369=AXIS2_PLACEMENT_3D('',#2366,#2367,#2368);
#2370=CIRCLE('',#2369,4.5);
#2371=EDGE_CURVE('E650',#779,#777,#2370,.T.);
#2372=ORIENTED_EDGE('',*,*,#2371,.T.);
#2373=ORIENTED_EDGE('',*,*,#803,.T.);
#2374=ORIENTED_EDGE('',*,*,#1946,.T.);
#2375=EDGE_LOOP('',(#2365,#2372,#2373,#2374));
#2376=FACE_BOUND('',#2375,.T.);
#2377=ADVANCED_FACE('F1184',(#2376),#2364,.F.);
#2378=CARTESIAN_POINT('',(8.90327741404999E-13,85.,85.));
#2379=DIRECTION('',(0.,-1.,0.));
#2380=DIRECTION('',(0.,0.,-1.));
#2381=AXIS2_PLACEMENT_3D('',#2378,#2379,#2380);
#2382=CYLINDRICAL_SURFACE('',#2381,4.5);
#2383=ORIENTED_EDGE('',*,*,#746,.F.);
#2384=CARTESIAN_POINT('',(8.90327741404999E-13,20.,85.));
#2385=DIRECTION('',(0.,1.,0.));
#2386=DIRECTION('',(0.,0.,-1.));
#2387=AXIS2_PLACEMENT_3D('',#2384,#2385,#2386);
#2388=CIRCLE('',#2387,4.5);
#2389=EDGE_CURVE('E608',#737,#735,#2388,.T.);
#2390=ORIENTED_EDGE('',*,*,#2389,.T.);
#2391=ORIENTED_EDGE('',*,*,#761,.T.);
#2392=ORIENTED_EDGE('',*,*,#1936,.T.);
#2393=EDGE_LOOP('',(#2383,#2390,#2391,#2392));
#2394=FACE_BOUND('',#2393,.T.);
#2395=ADVANCED_FACE('F1180',(#2394),#2382,.F.);
#2396=CARTESIAN_POINT('',(-85.,85.,0.));
#2397=DIRECTION('',(0.,-1.,0.));
#2398=DIRECTION('',(0.,0.,-1.));
#2399=AXIS2_PLACEMENT_3D('',#2396,#2397,#2398);
#2400=CYLINDRICAL_SURFACE('',#2399,4.5);
#2401=ORIENTED_EDGE('',*,*,#704,.F.);
#2402=CARTESIAN_POINT('',(-85.,20.,0.));
#2403=DIRECTION('',(0.,1.,0.));
#2404=DIRECTION('',(0.,0.,-1.));
#2405=AXIS2_PLACEMENT_3D('',#2402,#2403,#2404);
#2406=CIRCLE('',#2405,4.5);
#2407=EDGE_CURVE('E909',#695,#693,#2406,.T.);
#2408=ORIENTED_EDGE('',*,*,#2407,.T.);
#2409=ORIENTED_EDGE('',*,*,#719,.T.);
#2410=ORIENTED_EDGE('',*,*,#1926,.T.);
#2411=EDGE_LOOP('',(#2401,#2408,#2409,#2410));
#2412=FACE_BOUND('',#2411,.T.);
#2413=ADVANCED_FACE('F1183',(#2412),#2400,.F.);
#2414=CARTESIAN_POINT('',(-2.96775913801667E-13,20.,-85.));
#2415=DIRECTION('',(0.,-1.,0.));
#2416=DIRECTION('',(0.,0.,-1.));
#2417=AXIS2_PLACEMENT_3D('',#2414,#2415,#2416);
#2418=PLANE('',#2417);
#2419=ORIENTED_EDGE('',*,*,#1098,.T.);
#2420=ORIENTED_EDGE('',*,*,#1477,.T.);
#2421=DIRECTION('',(-0.819152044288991,0.,-0.573576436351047));
#2422=VECTOR('',#2421,1.);
#2423=CARTESIAN_POINT('',(-4.30182327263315,20.,-78.8563596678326));
#2424=LINE('',#2423,#2422);
#2425=CARTESIAN_POINT('',(-4.30182327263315,20.,-78.8563596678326));
#2426=VERTEX_POINT('',#2425);
#2427=EDGE_CURVE('E1635',#2426,#1469,#2424,.T.);
#2428=ORIENTED_EDGE('',*,*,#2427,.F.);
#2429=CARTESIAN_POINT('',(-2.96775913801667E-13,20.,-85.));
#2430=DIRECTION('',(0.,-1.,0.));
#2431=DIRECTION('',(-1.,0.,0.));
#2432=AXIS2_PLACEMENT_3D('',#2429,#2430,#2431);
#2433=CIRCLE('',#2432,7.5);
#2434=CARTESIAN_POINT('',(4.3018232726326,20.,-78.8563596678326));
#2435=VERTEX_POINT('',#2434);
#2436=EDGE_CURVE('E757',#2435,#2426,#2433,.T.);
#2437=ORIENTED_EDGE('',*,*,#2436,.F.);
#2438=DIRECTION('',(-0.819152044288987,0.,0.573576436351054));
#2439=VECTOR('',#2438,1.);
#2440=CARTESIAN_POINT('',(4.3018232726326,20.,-78.8563596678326));
#2441=LINE('',#2440,#2439);
#2442=EDGE_CURVE('E2017',#1097,#2435,#2441,.T.);
#2443=ORIENTED_EDGE('',*,*,#2442,.F.);
#2444=EDGE_LOOP('',(#2419,#2420,#2428,#2437,#2443));
#2445=FACE_BOUND('',#2444,.T.);
#2446=ORIENTED_EDGE('',*,*,#780,.F.);
#2447=ORIENTED_EDGE('',*,*,#2371,.F.);
#2448=EDGE_LOOP('',(#2446,#2447));
#2449=FACE_BOUND('',#2448,.T.);
#2450=ADVANCED_FACE('F1113',(#2445,#2449),#2418,.F.);
#2451=CARTESIAN_POINT('',(-2.96775913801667E-13,85.,-85.));
#2452=DIRECTION('',(0.,-1.,0.));
#2453=DIRECTION('',(0.,0.,-1.));
#2454=AXIS2_PLACEMENT_3D('',#2451,#2452,#2453);
#2455=CYLINDRICAL_SURFACE('',#2454,7.5);
#2456=ORIENTED_EDGE('',*,*,#1460,.T.);
#2457=ORIENTED_EDGE('',*,*,#1167,.T.);
#2458=DIRECTION('',(0.,-1.,0.));
#2459=VECTOR('',#2458,1.);
#2460=CARTESIAN_POINT('',(4.3018232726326,85.,-78.8563596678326));
#2461=LINE('',#2460,#2459);
#2462=EDGE_CURVE('E761',#1107,#2435,#2461,.T.);
#2463=ORIENTED_EDGE('',*,*,#2462,.T.);
#2464=ORIENTED_EDGE('',*,*,#2436,.T.);
#2465=DIRECTION('',(0.,-1.,0.));
#2466=VECTOR('',#2465,1.);
#2467=CARTESIAN_POINT('',(-4.30182327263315,85.,-78.8563596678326));
#2468=LINE('',#2467,#2466);
#2469=EDGE_CURVE('E1403',#1459,#2426,#2468,.T.);
#2470=ORIENTED_EDGE('',*,*,#2469,.F.);
#2471=EDGE_LOOP('',(#2456,#2457,#2463,#2464,#2470));
#2472=FACE_BOUND('',#2471,.T.);
#2473=ADVANCED_FACE('F1108',(#2472),#2455,.F.);
#2474=CARTESIAN_POINT('',(4.3018232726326,85.,-78.8563596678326));
#2475=DIRECTION('',(0.573576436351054,0.,0.819152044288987));
#2476=DIRECTION('',(0.,-1.,0.));
#2477=AXIS2_PLACEMENT_3D('',#2474,#2475,#2476);
#2478=PLANE('',#2477);
#2479=ORIENTED_EDGE('',*,*,#1108,.T.);
#2480=ORIENTED_EDGE('',*,*,#2442,.T.);
#2481=ORIENTED_EDGE('',*,*,#2462,.F.);
#2482=EDGE_LOOP('',(#2479,#2480,#2481));
#2483=FACE_BOUND('',#2482,.T.);
#2484=ADVANCED_FACE('F1112',(#2483),#2478,.F.);
#2485=CARTESIAN_POINT('',(-4.30182327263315,85.,-78.8563596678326));
#2486=DIRECTION('',(-0.573576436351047,0.,0.819152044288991));
#2487=DIRECTION('',(0.,1.,0.));
#2488=AXIS2_PLACEMENT_3D('',#2485,#2486,#2487);
#2489=PLANE('',#2488);
#2490=ORIENTED_EDGE('',*,*,#1470,.T.);
#2491=ORIENTED_EDGE('',*,*,#2469,.T.);
#2492=ORIENTED_EDGE('',*,*,#2427,.T.);
#2493=EDGE_LOOP('',(#2490,#2491,#2492));
#2494=FACE_BOUND('',#2493,.T.);
#2495=ADVANCED_FACE('F1171',(#2494),#2489,.F.);
#2496=CARTESIAN_POINT('',(-85.,20.,0.));
#2497=DIRECTION('',(0.,-1.,0.));
#2498=DIRECTION('',(0.,0.,-1.));
#2499=AXIS2_PLACEMENT_3D('',#2496,#2497,#2498);
#2500=PLANE('',#2499);
#2501=ORIENTED_EDGE('',*,*,#1708,.T.);
#2502=DIRECTION('',(-0.57357643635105,0.,0.819152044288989));
#2503=VECTOR('',#2502,1.);
#2504=CARTESIAN_POINT('',(-78.8563596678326,20.,4.30182327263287));
#2505=LINE('',#2504,#2503);
#2506=CARTESIAN_POINT('',(-78.8563596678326,20.,4.30182327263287));
#2507=VERTEX_POINT('',#2506);
#2508=EDGE_CURVE('E1426',#2507,#1698,#2505,.T.);
#2509=ORIENTED_EDGE('',*,*,#2508,.F.);
#2510=CARTESIAN_POINT('',(-85.,20.,0.));
#2511=DIRECTION('',(0.,-1.,0.));
#2512=DIRECTION('',(0.,0.,1.));
#2513=AXIS2_PLACEMENT_3D('',#2510,#2511,#2512);
#2514=CIRCLE('',#2513,7.5);
#2515=CARTESIAN_POINT('',(-78.8563596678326,20.,-4.30182327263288));
#2516=VERTEX_POINT('',#2515);
#2517=EDGE_CURVE('E900',#2516,#2507,#2514,.T.);
#2518=ORIENTED_EDGE('',*,*,#2517,.F.);
#2519=DIRECTION('',(0.573576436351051,0.,0.819152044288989));
#2520=VECTOR('',#2519,1.);
#2521=CARTESIAN_POINT('',(-78.8563596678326,20.,-4.30182327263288));
#2522=LINE('',#2521,#2520);
#2523=EDGE_CURVE('E1846',#1707,#2516,#2522,.T.);
#2524=ORIENTED_EDGE('',*,*,#2523,.F.);
#2525=EDGE_LOOP('',(#2501,#2509,#2518,#2524));
#2526=FACE_BOUND('',#2525,.T.);
#2527=ORIENTED_EDGE('',*,*,#696,.F.);
#2528=ORIENTED_EDGE('',*,*,#2407,.F.);
#2529=EDGE_LOOP('',(#2527,#2528));
#2530=FACE_BOUND('',#2529,.T.);
#2531=ADVANCED_FACE('F1690',(#2526,#2530),#2500,.F.);
#2532=CARTESIAN_POINT('',(-85.,85.,0.));
#2533=DIRECTION('',(0.,-1.,0.));
#2534=DIRECTION('',(0.,0.,-1.));
#2535=AXIS2_PLACEMENT_3D('',#2532,#2533,#2534);
#2536=CYLINDRICAL_SURFACE('',#2535,7.5);
#2537=ORIENTED_EDGE('',*,*,#1689,.T.);
#2538=DIRECTION('',(0.,-1.,0.));
#2539=VECTOR('',#2538,1.);
#2540=CARTESIAN_POINT('',(-78.8563596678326,85.,-4.30182327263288));
#2541=LINE('',#2540,#2539);
#2542=EDGE_CURVE('E904',#1688,#2516,#2541,.T.);
#2543=ORIENTED_EDGE('',*,*,#2542,.T.);
#2544=ORIENTED_EDGE('',*,*,#2517,.T.);
#2545=DIRECTION('',(0.,-1.,0.));
#2546=VECTOR('',#2545,1.);
#2547=CARTESIAN_POINT('',(-78.8563596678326,85.,4.30182327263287));
#2548=LINE('',#2547,#2546);
#2549=EDGE_CURVE('E1642',#1686,#2507,#2548,.T.);
#2550=ORIENTED_EDGE('',*,*,#2549,.F.);
#2551=EDGE_LOOP('',(#2537,#2543,#2544,#2550));
#2552=FACE_BOUND('',#2551,.T.);
#2553=ADVANCED_FACE('F1732',(#2552),#2536,.F.);
#2554=CARTESIAN_POINT('',(-78.8563596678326,85.,-4.30182327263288));
#2555=DIRECTION('',(0.819152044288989,0.,-0.573576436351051));
#2556=DIRECTION('',(0.,-1.,0.));
#2557=AXIS2_PLACEMENT_3D('',#2554,#2555,#2556);
#2558=PLANE('',#2557);
#2559=ORIENTED_EDGE('',*,*,#1716,.T.);
#2560=ORIENTED_EDGE('',*,*,#2523,.T.);
#2561=ORIENTED_EDGE('',*,*,#2542,.F.);
#2562=EDGE_LOOP('',(#2559,#2560,#2561));
#2563=FACE_BOUND('',#2562,.T.);
#2564=ADVANCED_FACE('F1222',(#2563),#2558,.F.);
#2565=CARTESIAN_POINT('',(-78.8563596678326,85.,4.30182327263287));
#2566=DIRECTION('',(0.819152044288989,0.,0.57357643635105));
#2567=DIRECTION('',(0.,-1.,0.));
#2568=AXIS2_PLACEMENT_3D('',#2565,#2566,#2567);
#2569=PLANE('',#2568);
#2570=ORIENTED_EDGE('',*,*,#1699,.T.);
#2571=ORIENTED_EDGE('',*,*,#2549,.T.);
#2572=ORIENTED_EDGE('',*,*,#2508,.T.);
#2573=EDGE_LOOP('',(#2570,#2571,#2572));
#2574=FACE_BOUND('',#2573,.T.);
#2575=ADVANCED_FACE('F1178',(#2574),#2569,.F.);
#2576=CARTESIAN_POINT('',(8.90327741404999E-13,20.,85.));
#2577=DIRECTION('',(0.,-1.,0.));
#2578=DIRECTION('',(0.,0.,-1.));
#2579=AXIS2_PLACEMENT_3D('',#2576,#2577,#2578);
#2580=PLANE('',#2579);
#2581=ORIENTED_EDGE('',*,*,#1495,.T.);
#2582=ORIENTED_EDGE('',*,*,#1074,.T.);
#2583=DIRECTION('',(0.819152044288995,0.,0.573576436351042));
#2584=VECTOR('',#2583,1.);
#2585=CARTESIAN_POINT('',(4.3018232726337,20.,78.8563596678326));
#2586=LINE('',#2585,#2584);
#2587=EDGE_CURVE('E698',#670,#1064,#2586,.T.);
#2588=ORIENTED_EDGE('',*,*,#2587,.F.);
#2589=ORIENTED_EDGE('',*,*,#671,.F.);
#2590=CARTESIAN_POINT('',(8.90327741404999E-13,20.,85.));
#2591=DIRECTION('',(0.,-1.,0.));
#2592=DIRECTION('',(1.,0.,0.));
#2593=AXIS2_PLACEMENT_3D('',#2590,#2591,#2592);
#2594=CIRCLE('',#2593,7.5);
#2595=CARTESIAN_POINT('',(-4.30182327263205,20.,78.8563596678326));
#2596=VERTEX_POINT('',#2595);
#2597=EDGE_CURVE('E1323',#2596,#661,#2594,.T.);
#2598=ORIENTED_EDGE('',*,*,#2597,.F.);
#2599=DIRECTION('',(0.819152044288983,0.,-0.57357643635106));
#2600=VECTOR('',#2599,1.);
#2601=CARTESIAN_POINT('',(-4.30182327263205,20.,78.8563596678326));
#2602=LINE('',#2601,#2600);
#2603=EDGE_CURVE('E1851',#1494,#2596,#2602,.T.);
#2604=ORIENTED_EDGE('',*,*,#2603,.F.);
#2605=EDGE_LOOP('',(#2581,#2582,#2588,#2589,#2598,#2604));
#2606=FACE_BOUND('',#2605,.T.);
#2607=ORIENTED_EDGE('',*,*,#738,.F.);
#2608=ORIENTED_EDGE('',*,*,#2389,.F.);
#2609=EDGE_LOOP('',(#2607,#2608));
#2610=FACE_BOUND('',#2609,.T.);
#2611=ADVANCED_FACE('F1174',(#2606,#2610),#2580,.F.);
#2612=CARTESIAN_POINT('',(8.90327741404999E-13,85.,85.));
#2613=DIRECTION('',(0.,-1.,0.));
#2614=DIRECTION('',(0.,0.,-1.));
#2615=AXIS2_PLACEMENT_3D('',#2612,#2613,#2614);
#2616=CYLINDRICAL_SURFACE('',#2615,7.5);
#2617=ORIENTED_EDGE('',*,*,#662,.F.);
#2618=ORIENTED_EDGE('',*,*,#1562,.T.);
#2619=DIRECTION('',(0.,-1.,0.));
#2620=VECTOR('',#2619,1.);
#2621=CARTESIAN_POINT('',(-4.30182327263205,85.,78.8563596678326));
#2622=LINE('',#2621,#2620);
#2623=EDGE_CURVE('E1326',#1504,#2596,#2622,.T.);
#2624=ORIENTED_EDGE('',*,*,#2623,.T.);
#2625=ORIENTED_EDGE('',*,*,#2597,.T.);
#2626=EDGE_LOOP('',(#2617,#2618,#2624,#2625));
#2627=FACE_BOUND('',#2626,.T.);
#2628=ADVANCED_FACE('F1177',(#2627),#2616,.F.);
#2629=CARTESIAN_POINT('',(-4.30182327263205,85.,78.8563596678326));
#2630=DIRECTION('',(-0.57357643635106,0.,-0.819152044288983));
#2631=DIRECTION('',(-0.819152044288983,0.,0.57357643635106));
#2632=AXIS2_PLACEMENT_3D('',#2629,#2630,#2631);
#2633=PLANE('',#2632);
#2634=ORIENTED_EDGE('',*,*,#1505,.T.);
#2635=ORIENTED_EDGE('',*,*,#2603,.T.);
#2636=ORIENTED_EDGE('',*,*,#2623,.F.);
#2637=EDGE_LOOP('',(#2634,#2635,#2636));
#2638=FACE_BOUND('',#2637,.T.);
#2639=ADVANCED_FACE('F1678',(#2638),#2633,.F.);
#2640=CARTESIAN_POINT('',(4.3018232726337,85.,78.8563596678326));
#2641=DIRECTION('',(0.573576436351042,0.,-0.819152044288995));
#2642=DIRECTION('',(0.,-1.,0.));
#2643=AXIS2_PLACEMENT_3D('',#2640,#2641,#2642);
#2644=PLANE('',#2643);
#2645=ORIENTED_EDGE('',*,*,#1065,.T.);
#2646=ORIENTED_EDGE('',*,*,#677,.T.);
#2647=ORIENTED_EDGE('',*,*,#2587,.T.);
#2648=EDGE_LOOP('',(#2645,#2646,#2647));
#2649=FACE_BOUND('',#2648,.T.);
#2650=ADVANCED_FACE('F1454',(#2649),#2644,.F.);
#2651=CARTESIAN_POINT('',(0.,10.7023274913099,0.));
#2652=DIRECTION('',(0.,-1.,0.));
#2653=DIRECTION('',(0.,0.,-1.));
#2654=AXIS2_PLACEMENT_3D('',#2651,#2652,#2653);
#2655=TOROIDAL_SURFACE('',#2654,75.,20.);
#2656=ORIENTED_EDGE('',*,*,#470,.F.);
#2657=ORIENTED_EDGE('',*,*,#1485,.F.);
#2658=ORIENTED_EDGE('',*,*,#573,.T.);
#2659=ORIENTED_EDGE('',*,*,#1033,.F.);
#2660=EDGE_LOOP('',(#2656,#2657,#2658,#2659));
#2661=FACE_BOUND('',#2660,.T.);
#2662=ADVANCED_FACE('F2100',(#2661),#2655,.T.);
#2663=CARTESIAN_POINT('',(-42.4264068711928,10.,-70.7106781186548));
#2664=DIRECTION('',(0.,-1.,0.));
#2665=DIRECTION('',(0.,0.,-1.));
#2666=AXIS2_PLACEMENT_3D('',#2663,#2664,#2665);
#2667=CYLINDRICAL_SURFACE('',#2666,4.);
#2668=ORIENTED_EDGE('',*,*,#427,.F.);
#2669=CARTESIAN_POINT('',(-42.4264068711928,10.,-70.7106781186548));
#2670=DIRECTION('',(0.,-1.,0.));
#2671=DIRECTION('',(0.,0.,-1.));
#2672=AXIS2_PLACEMENT_3D('',#2669,#2670,#2671);
#2673=CIRCLE('',#2672,4.);
#2674=EDGE_CURVE('E746',#418,#416,#2673,.T.);
#2675=ORIENTED_EDGE('',*,*,#2674,.F.);
#2676=ORIENTED_EDGE('',*,*,#442,.T.);
#2677=ORIENTED_EDGE('',*,*,#1916,.T.);
#2678=EDGE_LOOP('',(#2668,#2675,#2676,#2677));
#2679=FACE_BOUND('',#2678,.T.);
#2680=ADVANCED_FACE('F1337',(#2679),#2667,.F.);
#2681=CARTESIAN_POINT('',(-42.4264068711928,10.,-70.7106781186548));
#2682=DIRECTION('',(0.,-1.,0.));
#2683=DIRECTION('',(0.,0.,-1.));
#2684=AXIS2_PLACEMENT_3D('',#2681,#2682,#2683);
#2685=PLANE('',#2684);
#2686=ORIENTED_EDGE('',*,*,#2674,.T.);
#2687=ORIENTED_EDGE('',*,*,#419,.T.);
#2688=EDGE_LOOP('',(#2686,#2687));
#2689=FACE_BOUND('',#2688,.T.);
#2690=ADVANCED_FACE('F1207',(#2689),#2685,.T.);
#2691=CARTESIAN_POINT('',(71.4177848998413,10.,43.1335136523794));
#2692=DIRECTION('',(0.,-1.,0.));
#2693=DIRECTION('',(0.,0.,-1.));
#2694=AXIS2_PLACEMENT_3D('',#2691,#2692,#2693);
#2695=CYLINDRICAL_SURFACE('',#2694,4.);
#2696=ORIENTED_EDGE('',*,*,#1885,.T.);
#2697=DIRECTION('',(0.,-1.,0.));
#2698=VECTOR('',#2697,1.);
#2699=CARTESIAN_POINT('',(68.5893577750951,10.,45.9619407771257));
#2700=LINE('',#2699,#2698);
#2701=CARTESIAN_POINT('',(68.5893577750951,10.,45.9619407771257));
#2702=VERTEX_POINT('',#2701);
#2703=EDGE_CURVE('E913',#2702,#1884,#2700,.T.);
#2704=ORIENTED_EDGE('',*,*,#2703,.F.);
#2705=CARTESIAN_POINT('',(71.4177848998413,10.,43.1335136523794));
#2706=DIRECTION('',(0.,-1.,0.));
#2707=DIRECTION('',(0.,0.,-1.));
#2708=AXIS2_PLACEMENT_3D('',#2705,#2706,#2707);
#2709=CIRCLE('',#2708,4.);
#2710=CARTESIAN_POINT('',(74.2462120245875,10.,40.3050865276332));
#2711=VERTEX_POINT('',#2710);
#2712=EDGE_CURVE('E1307',#2711,#2702,#2709,.T.);
#2713=ORIENTED_EDGE('',*,*,#2712,.F.);
#2714=DIRECTION('',(0.,-1.,0.));
#2715=VECTOR('',#2714,1.);
#2716=CARTESIAN_POINT('',(74.2462120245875,10.,40.3050865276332));
#2717=LINE('',#2716,#2715);
#2718=EDGE_CURVE('E593',#2711,#1882,#2717,.T.);
#2719=ORIENTED_EDGE('',*,*,#2718,.T.);
#2720=EDGE_LOOP('',(#2696,#2704,#2713,#2719));
#2721=FACE_BOUND('',#2720,.T.);
#2722=ADVANCED_FACE('F1115',(#2721),#2695,.F.);
#2723=CARTESIAN_POINT('',(74.2462120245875,10.,40.3050865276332));
#2724=DIRECTION('',(0.707106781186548,0.,-0.707106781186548));
#2725=DIRECTION('',(0.,-1.,0.));
#2726=AXIS2_PLACEMENT_3D('',#2723,#2724,#2725);
#2727=PLANE('',#2726);
#2728=ORIENTED_EDGE('',*,*,#1891,.T.);
#2729=ORIENTED_EDGE('',*,*,#2718,.F.);
#2730=DIRECTION('',(0.707106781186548,0.,0.707106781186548));
#2731=VECTOR('',#2730,1.);
#2732=CARTESIAN_POINT('',(74.2462120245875,10.,40.3050865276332));
#2733=LINE('',#2732,#2731);
#2734=EDGE_CURVE('E675',#376,#2711,#2733,.T.);
#2735=ORIENTED_EDGE('',*,*,#2734,.F.);
#2736=ORIENTED_EDGE('',*,*,#400,.T.);
#2737=EDGE_LOOP('',(#2728,#2729,#2735,#2736));
#2738=FACE_BOUND('',#2737,.T.);
#2739=ADVANCED_FACE('F1194',(#2738),#2727,.F.);
#2740=CARTESIAN_POINT('',(70.0035713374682,10.,41.7193000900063));
#2741=DIRECTION('',(0.,-1.,0.));
#2742=DIRECTION('',(0.,0.,-1.));
#2743=AXIS2_PLACEMENT_3D('',#2740,#2741,#2742);
#2744=CYLINDRICAL_SURFACE('',#2743,4.);
#2745=ORIENTED_EDGE('',*,*,#385,.F.);
#2746=CARTESIAN_POINT('',(70.0035713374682,10.,41.7193000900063));
#2747=DIRECTION('',(0.,-1.,0.));
#2748=DIRECTION('',(0.,0.,-1.));
#2749=AXIS2_PLACEMENT_3D('',#2746,#2747,#2748);
#2750=CIRCLE('',#2749,4.);
#2751=CARTESIAN_POINT('',(67.175144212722,10.,44.5477272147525));
#2752=VERTEX_POINT('',#2751);
#2753=EDGE_CURVE('E674',#2752,#374,#2750,.T.);
#2754=ORIENTED_EDGE('',*,*,#2753,.F.);
#2755=DIRECTION('',(0.,-1.,0.));
#2756=VECTOR('',#2755,1.);
#2757=CARTESIAN_POINT('',(67.175144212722,10.,44.5477272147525));
#2758=LINE('',#2757,#2756);
#2759=EDGE_CURVE('E598',#2752,#1900,#2758,.T.);
#2760=ORIENTED_EDGE('',*,*,#2759,.T.);
#2761=ORIENTED_EDGE('',*,*,#1901,.T.);
#2762=EDGE_LOOP('',(#2745,#2754,#2760,#2761));
#2763=FACE_BOUND('',#2762,.T.);
#2764=ADVANCED_FACE('F1196',(#2763),#2744,.F.);
#2765=CARTESIAN_POINT('',(68.5893577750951,10.,45.9619407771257));
#2766=DIRECTION('',(-0.707106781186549,0.,0.707106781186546));
#2767=DIRECTION('',(0.,1.,0.));
#2768=AXIS2_PLACEMENT_3D('',#2765,#2766,#2767);
#2769=PLANE('',#2768);
#2770=ORIENTED_EDGE('',*,*,#1907,.T.);
#2771=ORIENTED_EDGE('',*,*,#2759,.F.);
#2772=DIRECTION('',(-0.707106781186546,0.,-0.707106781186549));
#2773=VECTOR('',#2772,1.);
#2774=CARTESIAN_POINT('',(68.5893577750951,10.,45.9619407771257));
#2775=LINE('',#2774,#2773);
#2776=EDGE_CURVE('E684',#2702,#2752,#2775,.T.);
#2777=ORIENTED_EDGE('',*,*,#2776,.F.);
#2778=ORIENTED_EDGE('',*,*,#2703,.T.);
#2779=EDGE_LOOP('',(#2770,#2771,#2777,#2778));
#2780=FACE_BOUND('',#2779,.T.);
#2781=ADVANCED_FACE('F1204',(#2780),#2769,.F.);
#2782=CARTESIAN_POINT('',(71.4177848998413,10.,43.1335136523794));
#2783=DIRECTION('',(0.,-1.,0.));
#2784=DIRECTION('',(0.,0.,-1.));
#2785=AXIS2_PLACEMENT_3D('',#2782,#2783,#2784);
#2786=PLANE('',#2785);
#2787=ORIENTED_EDGE('',*,*,#2712,.T.);
#2788=ORIENTED_EDGE('',*,*,#2776,.T.);
#2789=ORIENTED_EDGE('',*,*,#2753,.T.);
#2790=ORIENTED_EDGE('',*,*,#377,.T.);
#2791=ORIENTED_EDGE('',*,*,#2734,.T.);
#2792=EDGE_LOOP('',(#2787,#2788,#2789,#2790,#2791));
#2793=FACE_BOUND('',#2792,.T.);
#2794=ADVANCED_FACE('F1054',(#2793),#2786,.T.);
#2795=CARTESIAN_POINT('',(0.,7.,0.));
#2796=DIRECTION('',(0.707106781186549,0.,-0.707106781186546));
#2797=DIRECTION('',(-0.707106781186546,0.,-0.707106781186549));
#2798=AXIS2_PLACEMENT_3D('',#2795,#2796,#2797);
#2799=CYLINDRICAL_SURFACE('',#2798,6.);
#2800=ORIENTED_EDGE('',*,*,#996,.F.);
#2801=ORIENTED_EDGE('',*,*,#557,.F.);
#2802=DIRECTION('',(0.707106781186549,0.,-0.707106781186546));
#2803=VECTOR('',#2802,1.);
#2804=CARTESIAN_POINT('',(0.,13.,0.));
#2805=LINE('',#2804,#2803);
#2806=EDGE_CURVE('E670',#2065,#517,#2805,.T.);
#2807=ORIENTED_EDGE('',*,*,#2806,.F.);
#2808=ORIENTED_EDGE('',*,*,#2066,.F.);
#2809=ORIENTED_EDGE('',*,*,#2201,.F.);
#2810=EDGE_LOOP('',(#2800,#2801,#2807,#2808,#2809));
#2811=FACE_BOUND('',#2810,.T.);
#2812=ADVANCED_FACE('F1043',(#2811),#2799,.F.);
#2813=CARTESIAN_POINT('',(0.,7.,0.));
#2814=DIRECTION('',(-0.707106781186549,0.,0.707106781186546));
#2815=DIRECTION('',(0.707106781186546,0.,0.707106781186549));
#2816=AXIS2_PLACEMENT_3D('',#2813,#2814,#2815);
#2817=CYLINDRICAL_SURFACE('',#2816,6.);
#2818=ORIENTED_EDGE('',*,*,#1779,.F.);
#2819=ORIENTED_EDGE('',*,*,#2232,.F.);
#2820=ORIENTED_EDGE('',*,*,#2137,.F.);
#2821=ORIENTED_EDGE('',*,*,#2806,.T.);
#2822=ORIENTED_EDGE('',*,*,#518,.F.);
#2823=EDGE_LOOP('',(#2818,#2819,#2820,#2821,#2822));
#2824=FACE_BOUND('',#2823,.T.);
#2825=ADVANCED_FACE('F1053',(#2824),#2817,.F.);
#2826=CARTESIAN_POINT('',(0.,2.5,0.));
#2827=DIRECTION('',(0.,-1.,0.));
#2828=DIRECTION('',(0.,0.,-1.));
#2829=AXIS2_PLACEMENT_3D('',#2826,#2827,#2828);
#2830=PLANE('',#2829);
#2831=DIRECTION('',(0.707106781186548,0.,0.707106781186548));
#2832=VECTOR('',#2831,1.);
#2833=CARTESIAN_POINT('',(43.1335136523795,2.5,-71.4177848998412));
#2834=LINE('',#2833,#2832);
#2835=CARTESIAN_POINT('',(67.8822509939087,2.5,-46.669047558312));
#2836=VERTEX_POINT('',#2835);
#2837=EDGE_CURVE('E631',#2218,#2836,#2834,.T.);
#2838=ORIENTED_EDGE('',*,*,#2837,.T.);
#2839=CARTESIAN_POINT('',(64.3467170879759,2.5,-43.1335136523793));
#2840=DIRECTION('',(0.,-1.,0.));
#2841=DIRECTION('',(0.,0.,-1.));
#2842=AXIS2_PLACEMENT_3D('',#2839,#2840,#2841);
#2843=CIRCLE('',#2842,5.);
#2844=CARTESIAN_POINT('',(67.8822509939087,2.5,-39.5979797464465));
#2845=VERTEX_POINT('',#2844);
#2846=EDGE_CURVE('E627',#2836,#2845,#2843,.T.);
#2847=ORIENTED_EDGE('',*,*,#2846,.T.);
#2848=DIRECTION('',(-0.707106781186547,0.,0.707106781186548));
#2849=VECTOR('',#2848,1.);
#2850=CARTESIAN_POINT('',(55.8614357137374,2.5,-27.5771644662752));
#2851=LINE('',#2850,#2849);
#2852=EDGE_CURVE('E632',#2845,#2153,#2851,.T.);
#2853=ORIENTED_EDGE('',*,*,#2852,.T.);
#2854=ORIENTED_EDGE('',*,*,#2154,.F.);
#2855=ORIENTED_EDGE('',*,*,#2225,.T.);
#2856=EDGE_LOOP('',(#2838,#2847,#2853,#2854,#2855));
#2857=FACE_BOUND('',#2856,.T.);
#2858=CARTESIAN_POINT('',(63.6396103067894,2.5,-42.4264068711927));
#2859=DIRECTION('',(0.,-1.,0.));
#2860=DIRECTION('',(0.,0.,-1.));
#2861=AXIS2_PLACEMENT_3D('',#2858,#2859,#2860);
#2862=CIRCLE('',#2861,1.24999999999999);
#2863=EDGE_CURVE('E849',#263,#254,#2862,.T.);
#2864=ORIENTED_EDGE('',*,*,#2863,.F.);
#2865=ORIENTED_EDGE('',*,*,#264,.F.);
#2866=EDGE_LOOP('',(#2864,#2865));
#2867=FACE_BOUND('',#2866,.T.);
#2868=ADVANCED_FACE('F1451',(#2857,#2867),#2830,.T.);
#2869=CARTESIAN_POINT('',(43.1335136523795,2.5,-71.4177848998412));
#2870=DIRECTION('',(0.707106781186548,0.,-0.707106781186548));
#2871=DIRECTION('',(0.,-1.,0.));
#2872=AXIS2_PLACEMENT_3D('',#2869,#2870,#2871);
#2873=PLANE('',#2872);
#2874=ORIENTED_EDGE('',*,*,#1840,.T.);
#2875=DIRECTION('',(0.,1.,0.));
#2876=VECTOR('',#2875,1.);
#2877=CARTESIAN_POINT('',(67.8822509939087,2.5,-46.669047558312));
#2878=LINE('',#2877,#2876);
#2879=EDGE_CURVE('E926',#1831,#2836,#2878,.T.);
#2880=ORIENTED_EDGE('',*,*,#2879,.T.);
#2881=ORIENTED_EDGE('',*,*,#2837,.F.);
#2882=ORIENTED_EDGE('',*,*,#2219,.F.);
#2883=EDGE_LOOP('',(#2874,#2880,#2881,#2882));
#2884=FACE_BOUND('',#2883,.T.);
#2885=ADVANCED_FACE('F1954',(#2884),#2873,.F.);
#2886=CARTESIAN_POINT('',(55.8614357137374,2.5,-27.5771644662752));
#2887=DIRECTION('',(0.707106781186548,0.,0.707106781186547));
#2888=DIRECTION('',(0.,-1.,0.));
#2889=AXIS2_PLACEMENT_3D('',#2886,#2887,#2888);
#2890=PLANE('',#2889);
#2891=ORIENTED_EDGE('',*,*,#2852,.F.);
#2892=DIRECTION('',(0.,-1.,0.));
#2893=VECTOR('',#2892,1.);
#2894=CARTESIAN_POINT('',(67.8822509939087,0.,-39.5979797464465));
#2895=LINE('',#2894,#2893);
#2896=EDGE_CURVE('E840',#2845,#1822,#2895,.T.);
#2897=ORIENTED_EDGE('',*,*,#2896,.T.);
#2898=ORIENTED_EDGE('',*,*,#1823,.T.);
#2899=ORIENTED_EDGE('',*,*,#2160,.T.);
#2900=EDGE_LOOP('',(#2891,#2897,#2898,#2899));
#2901=FACE_BOUND('',#2900,.T.);
#2902=ADVANCED_FACE('F1949',(#2901),#2890,.F.);
#2903=CARTESIAN_POINT('',(43.1335136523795,2.5,-71.4177848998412));
#2904=DIRECTION('',(0.707106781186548,0.,-0.707106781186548));
#2905=DIRECTION('',(0.,-1.,0.));
#2906=AXIS2_PLACEMENT_3D('',#2903,#2904,#2905);
#2907=PLANE('',#2906);
#2908=DIRECTION('',(0.707106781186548,0.,0.707106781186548));
#2909=VECTOR('',#2908,1.);
#2910=CARTESIAN_POINT('',(43.1335136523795,2.5,-71.4177848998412));
#2911=LINE('',#2910,#2909);
#2912=CARTESIAN_POINT('',(46.6690475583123,2.5,-67.8822509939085));
#2913=VERTEX_POINT('',#2912);
#2914=EDGE_CURVE('E858',#2913,#2186,#2911,.T.);
#2915=ORIENTED_EDGE('',*,*,#2914,.F.);
#2916=DIRECTION('',(0.,-1.,0.));
#2917=VECTOR('',#2916,1.);
#2918=CARTESIAN_POINT('',(46.6690475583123,0.,-67.8822509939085));
#2919=LINE('',#2918,#2917);
#2920=EDGE_CURVE('E821',#2913,#1864,#2919,.T.);
#2921=ORIENTED_EDGE('',*,*,#2920,.T.);
#2922=ORIENTED_EDGE('',*,*,#1865,.T.);
#2923=ORIENTED_EDGE('',*,*,#2193,.F.);
#2924=EDGE_LOOP('',(#2915,#2921,#2922,#2923));
#2925=FACE_BOUND('',#2924,.T.);
#2926=ADVANCED_FACE('F1975',(#2925),#2907,.F.);
#2927=CARTESIAN_POINT('',(0.,2.5,0.));
#2928=DIRECTION('',(0.,-1.,0.));
#2929=DIRECTION('',(0.,0.,-1.));
#2930=AXIS2_PLACEMENT_3D('',#2927,#2928,#2929);
#2931=PLANE('',#2930);
#2932=DIRECTION('',(0.707106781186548,0.,-0.707106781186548));
#2933=VECTOR('',#2932,1.);
#2934=CARTESIAN_POINT('',(27.5771644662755,2.5,-55.8614357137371));
#2935=LINE('',#2934,#2933);
#2936=CARTESIAN_POINT('',(39.5979797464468,2.5,-67.8822509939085));
#2937=VERTEX_POINT('',#2936);
#2938=EDGE_CURVE('E661',#1977,#2937,#2935,.T.);
#2939=ORIENTED_EDGE('',*,*,#2938,.T.);
#2940=CARTESIAN_POINT('',(43.1335136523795,2.5,-64.3467170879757));
#2941=DIRECTION('',(0.,-1.,0.));
#2942=DIRECTION('',(0.,0.,-1.));
#2943=AXIS2_PLACEMENT_3D('',#2940,#2941,#2942);
#2944=CIRCLE('',#2943,5.);
#2945=EDGE_CURVE('E666',#2937,#2913,#2944,.T.);
#2946=ORIENTED_EDGE('',*,*,#2945,.T.);
#2947=ORIENTED_EDGE('',*,*,#2914,.T.);
#2948=ORIENTED_EDGE('',*,*,#2187,.T.);
#2949=ORIENTED_EDGE('',*,*,#1987,.F.);
#2950=EDGE_LOOP('',(#2939,#2946,#2947,#2948,#2949));
#2951=FACE_BOUND('',#2950,.T.);
#2952=CARTESIAN_POINT('',(42.4264068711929,2.5,-63.6396103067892));
#2953=DIRECTION('',(0.,-1.,0.));
#2954=DIRECTION('',(0.,0.,-1.));
#2955=AXIS2_PLACEMENT_3D('',#2952,#2953,#2954);
#2956=CIRCLE('',#2955,1.24999999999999);
#2957=EDGE_CURVE('E751',#328,#319,#2956,.T.);
#2958=ORIENTED_EDGE('',*,*,#2957,.F.);
#2959=ORIENTED_EDGE('',*,*,#329,.F.);
#2960=EDGE_LOOP('',(#2958,#2959));
#2961=FACE_BOUND('',#2960,.T.);
#2962=ADVANCED_FACE('F1679',(#2951,#2961),#2931,.T.);
#2963=CARTESIAN_POINT('',(27.5771644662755,2.5,-55.8614357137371));
#2964=DIRECTION('',(-0.707106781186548,0.,-0.707106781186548));
#2965=DIRECTION('',(-0.707106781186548,0.,0.707106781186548));
#2966=AXIS2_PLACEMENT_3D('',#2963,#2964,#2965);
#2967=PLANE('',#2966);
#2968=ORIENTED_EDGE('',*,*,#1798,.T.);
#2969=DIRECTION('',(0.,1.,0.));
#2970=VECTOR('',#2969,1.);
#2971=CARTESIAN_POINT('',(39.5979797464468,2.5,-67.8822509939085));
#2972=LINE('',#2971,#2970);
#2973=EDGE_CURVE('E806',#1797,#2937,#2972,.T.);
#2974=ORIENTED_EDGE('',*,*,#2973,.T.);
#2975=ORIENTED_EDGE('',*,*,#2938,.F.);
#2976=ORIENTED_EDGE('',*,*,#1978,.T.);
#2977=EDGE_LOOP('',(#2968,#2974,#2975,#2976));
#2978=FACE_BOUND('',#2977,.T.);
#2979=ADVANCED_FACE('F1962',(#2978),#2967,.F.);
#2980=CARTESIAN_POINT('',(43.1335136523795,2.5,-64.3467170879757));
#2981=DIRECTION('',(0.,1.,0.));
#2982=DIRECTION('',(0.,0.,1.));
#2983=AXIS2_PLACEMENT_3D('',#2980,#2981,#2982);
#2984=CYLINDRICAL_SURFACE('',#2983,5.);
#2985=ORIENTED_EDGE('',*,*,#2945,.F.);
#2986=ORIENTED_EDGE('',*,*,#2973,.F.);
#2987=ORIENTED_EDGE('',*,*,#1872,.F.);
#2988=ORIENTED_EDGE('',*,*,#2920,.F.);
#2989=EDGE_LOOP('',(#2985,#2986,#2987,#2988));
#2990=FACE_BOUND('',#2989,.T.);
#2991=ADVANCED_FACE('F1958',(#2990),#2984,.F.);
#2992=CARTESIAN_POINT('',(64.3467170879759,2.5,-43.1335136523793));
#2993=DIRECTION('',(0.,1.,0.));
#2994=DIRECTION('',(0.,0.,1.));
#2995=AXIS2_PLACEMENT_3D('',#2992,#2993,#2994);
#2996=CYLINDRICAL_SURFACE('',#2995,5.);
#2997=ORIENTED_EDGE('',*,*,#2846,.F.);
#2998=ORIENTED_EDGE('',*,*,#2879,.F.);
#2999=ORIENTED_EDGE('',*,*,#1832,.F.);
#3000=ORIENTED_EDGE('',*,*,#2896,.F.);
#3001=EDGE_LOOP('',(#2997,#2998,#2999,#3000));
#3002=FACE_BOUND('',#3001,.T.);
#3003=ADVANCED_FACE('F1961',(#3002),#2996,.F.);
#3004=CARTESIAN_POINT('',(42.4264068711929,10.,-63.6396103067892));
#3005=DIRECTION('',(0.,-1.,0.));
#3006=DIRECTION('',(0.,0.,-1.));
#3007=AXIS2_PLACEMENT_3D('',#3004,#3005,#3006);
#3008=CONICAL_SURFACE('',#3007,1.24999999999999,1.02974425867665);
#3009=ORIENTED_EDGE('',*,*,#357,.F.);
#3010=ORIENTED_EDGE('',*,*,#351,.T.);
#3011=CARTESIAN_POINT('',(42.4264068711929,10.,-63.6396103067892));
#3012=DIRECTION('',(0.,-1.,0.));
#3013=DIRECTION('',(0.,0.,-1.));
#3014=AXIS2_PLACEMENT_3D('',#3011,#3012,#3013);
#3015=CIRCLE('',#3014,1.24999999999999);
#3016=EDGE_CURVE('E750',#311,#309,#3015,.T.);
#3017=ORIENTED_EDGE('',*,*,#3016,.T.);
#3018=EDGE_LOOP('',(#3009,#3010,#3017));
#3019=FACE_BOUND('',#3018,.T.);
#3020=ADVANCED_FACE('F17',(#3019),#3008,.F.);
#3021=CARTESIAN_POINT('',(42.4264068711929,2.5,-63.6396103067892));
#3022=DIRECTION('',(0.,-1.,0.));
#3023=DIRECTION('',(0.,0.,-1.));
#3024=AXIS2_PLACEMENT_3D('',#3021,#3022,#3023);
#3025=CYLINDRICAL_SURFACE('',#3024,1.24999999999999);
#3026=ORIENTED_EDGE('',*,*,#320,.F.);
#3027=ORIENTED_EDGE('',*,*,#3016,.F.);
#3028=ORIENTED_EDGE('',*,*,#335,.T.);
#3029=ORIENTED_EDGE('',*,*,#2957,.T.);
#3030=EDGE_LOOP('',(#3026,#3027,#3028,#3029));
#3031=FACE_BOUND('',#3030,.T.);
#3032=ADVANCED_FACE('F2106',(#3031),#3025,.F.);
#3033=CARTESIAN_POINT('',(63.6396103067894,10.,-42.4264068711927));
#3034=DIRECTION('',(0.,-1.,0.));
#3035=DIRECTION('',(0.,0.,-1.));
#3036=AXIS2_PLACEMENT_3D('',#3033,#3034,#3035);
#3037=CONICAL_SURFACE('',#3036,1.24999999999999,1.02974425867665);
#3038=ORIENTED_EDGE('',*,*,#292,.F.);
#3039=ORIENTED_EDGE('',*,*,#286,.T.);
#3040=CARTESIAN_POINT('',(63.6396103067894,10.,-42.4264068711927));
#3041=DIRECTION('',(0.,-1.,0.));
#3042=DIRECTION('',(0.,0.,-1.));
#3043=AXIS2_PLACEMENT_3D('',#3040,#3041,#3042);
#3044=CIRCLE('',#3043,1.24999999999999);
#3045=EDGE_CURVE('E890',#246,#244,#3044,.T.);
#3046=ORIENTED_EDGE('',*,*,#3045,.T.);
#3047=EDGE_LOOP('',(#3038,#3039,#3046));
#3048=FACE_BOUND('',#3047,.T.);
#3049=ADVANCED_FACE('F2103',(#3048),#3037,.F.);
#3050=CARTESIAN_POINT('',(63.6396103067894,2.5,-42.4264068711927));
#3051=DIRECTION('',(0.,-1.,0.));
#3052=DIRECTION('',(0.,0.,-1.));
#3053=AXIS2_PLACEMENT_3D('',#3050,#3051,#3052);
#3054=CYLINDRICAL_SURFACE('',#3053,1.24999999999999);
#3055=ORIENTED_EDGE('',*,*,#255,.F.);
#3056=ORIENTED_EDGE('',*,*,#3045,.F.);
#3057=ORIENTED_EDGE('',*,*,#270,.T.);
#3058=ORIENTED_EDGE('',*,*,#2863,.T.);
#3059=EDGE_LOOP('',(#3055,#3056,#3057,#3058));
#3060=FACE_BOUND('',#3059,.T.);
#3061=ADVANCED_FACE('F1491',(#3060),#3054,.F.);
#3062=CARTESIAN_POINT('',(0.,84.8,0.));
#3063=DIRECTION('',(0.,1.,0.));
#3064=DIRECTION('',(0.,0.,1.));
#3065=AXIS2_PLACEMENT_3D('',#3062,#3063,#3064);
#3066=PLANE('',#3065);
#3067=ORIENTED_EDGE('',*,*,#33,.T.);
#3068=ORIENTED_EDGE('',*,*,#165,.T.);
#3069=ORIENTED_EDGE('',*,*,#220,.F.);
#3070=EDGE_LOOP('',(#3067,#3068,#3069));
#3071=FACE_BOUND('',#3070,.T.);
#3072=ORIENTED_EDGE('',*,*,#124,.T.);
#3073=ORIENTED_EDGE('',*,*,#140,.T.);
#3074=EDGE_LOOP('',(#3072,#3073));
#3075=FACE_BOUND('',#3074,.T.);
#3076=ADVANCED_FACE('F2137',(#3071,#3075),#3066,.T.);
#3077=CARTESIAN_POINT('',(0.,15.,0.));
#3078=DIRECTION('',(0.,-1.,0.));
#3079=DIRECTION('',(0.,0.,-1.));
#3080=AXIS2_PLACEMENT_3D('',#3077,#3078,#3079);
#3081=PLANE('',#3080);
#3082=ORIENTED_EDGE('',*,*,#1968,.T.);
#3083=ORIENTED_EDGE('',*,*,#916,.T.);
#3084=EDGE_LOOP('',(#3082,#3083));
#3085=FACE_BOUND('',#3084,.T.);
#3086=ADVANCED_FACE('F532',(#3085),#3081,.T.);
#3087=CLOSED_SHELL('',(#83,#152,#208,#232,#274,#297,#339,#362,#404,#446,#577,#681,#723,#765,
#807,#849,#893,#935,#1006,#1037,#1331,#1382,#1720,#1784,#1961,#2165,#2175,#2206,#2237,#2249,
#2261,#2279,#2315,#2337,#2348,#2359,#2377,#2395,#2413,#2450,#2473,#2484,#2495,#2531,#2553,#2564,
#2575,#2611,#2628,#2639,#2650,#2662,#2680,#2690,#2722,#2739,#2764,#2781,#2794,#2812,#2825,#2868,
#2885,#2902,#2926,#2962,#2979,#2991,#3003,#3020,#3032,#3049,#3061,#3076,#3086));
#3088=MANIFOLD_SOLID_BREP('B1',#3087);
#3089=ADVANCED_BREP_SHAPE_REPRESENTATION('',(#18,#3088),#14);
#3090=SHAPE_DEFINITION_REPRESENTATION(#9,#3089);
ENDSEC;
END-ISO-10303-21;
